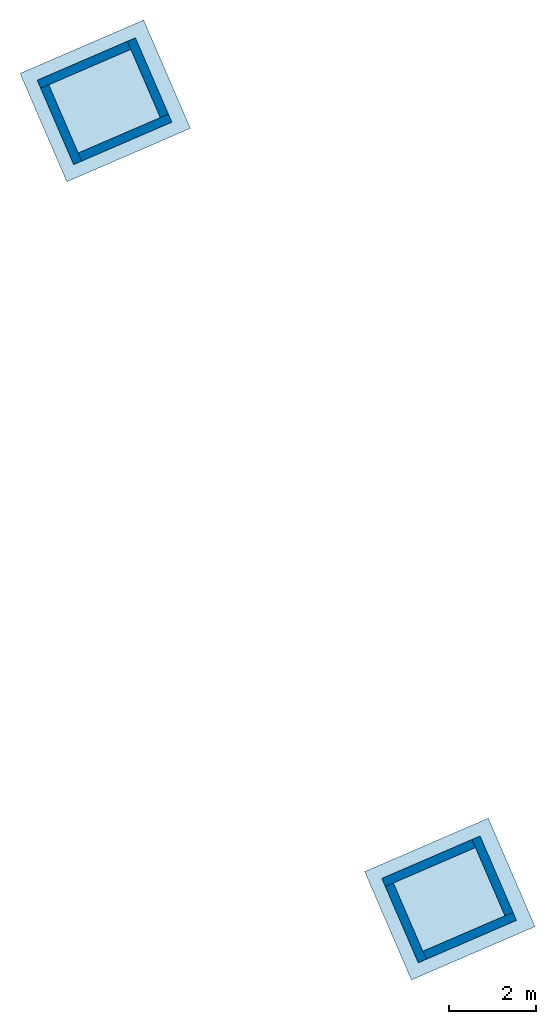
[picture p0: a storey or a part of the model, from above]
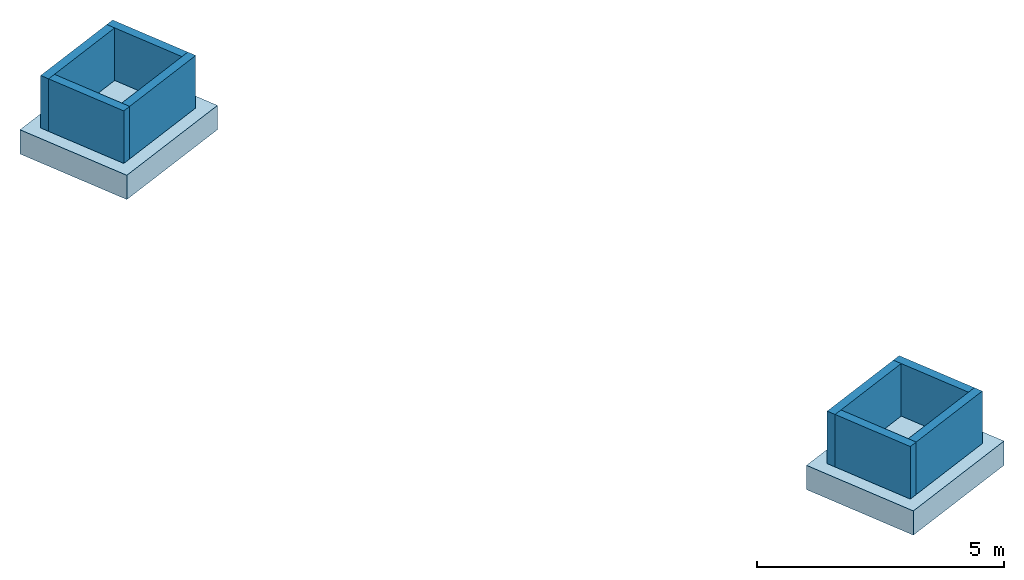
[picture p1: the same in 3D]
Properties of the parts of a building model (IFC4), part 1 of 4

# File
Description: ViewDefinition [ReferenceView_V1.2], RevitIdentifiers [ContentGUID: 2a206dc6-7e01-43c7-bab8-63df62a23673, VersionGUID: 60f15de3-2201-4711-b6eb-78f04dd25c04, NumberOfSaves: 5], CoordinateReference [CoordinateBase: Shared Coordinates, ProjectSite: Interno]
File name: C:\Users\Joaquin\Dropbox\BuildingProjects\2024 - Construcción Cesfam Coyhaique Con Sar Adosado\2_Modelos\all_models_2025-1-24_23.4.48\CCY_COOR-CCY_EST_Enriched.ifc
Time: 2025-11-28T11:11:42-03:00
Written by: IfcOpenShell 0.8.3-post1
Made in: Bonsai 0.8.3-post1

# IfcProject, 2016_03
LongName: CESFAM Coyhaique; Phase: 3

# IfcSite, Default
RefLatitude: 42, 21, 31, 181945; RefLongitude: -71, -3, -24, -263305; RefElevation: 0 m
Pset_SiteCommon - Reference: Project Information
Other - Category: Project Information; Client Name: Servicio de Salud Aysén; Project Address: Calle 2, s/n. Lote 1C.; Project Issue Date: Marzo 2017; Project Name: CESFAM Coyhaique; Project Number: 2016_03; Project Status: 3
Identity Data - Author: Astudillo y Aparicio Asociados Ltda.; Building Name: CESFAM Coyhaique; Organization Description: Arquitectura e ingeniería integrada; Organization Name: Astudillo y Aparicio Asociados Ltda.

# IfcBuilding, CESFAM Coyhaique
LongName: CESFAM Coyhaique
Pset_BuildingCommon - Reference: Project Information; NumberOfStoreys: 7
Pset_BuildingElementProxyCommon - Reference: Project Information; IsExternal: no
Pset_BuildingSystemCommon - Reference: Project Information
Other - Category: Project Information; Client Name: Servicio de Salud Aysén; Project Address: Calle 2, s/n. Lote 1C.; Project Issue Date: Marzo 2017; Project Name: CESFAM Coyhaique; Project Number: 2016_03; Project Status: 3
Identity Data - Author: Astudillo y Aparicio Asociados Ltda.; Building Name: CESFAM Coyhaique; Organization Description: Arquitectura e ingeniería integrada; Organization Name: Astudillo y Aparicio Asociados Ltda.

# IfcBuildingStorey: Level:8mm Head (7)
In: CESFAM Coyhaique
Other - Category: Levels; Family: Level; Family and Type: Level: 8mm Head; Type: 8mm Head; Type Id: 27
Dimensions - Computation Height: 0 m
Identity Data - Structural: no; Building Story: yes
Other(Type) - Category: Levels; Family Name: Level
Constraints(Type) - Elevation Base: Survey Point
Graphics(Type) - Color: 0; Line Pattern: Center; Line Weight: 1; Symbol: M_Level Head - Circle; Symbol at End 1 Default: no; Symbol at End 2 Default: yes
Identity Data(Type) - Type Name: 8mm Head
Name | LongName = Name | Elevation (m) | Constraints, Elevation (m)
Subterráneo 1 | Subterráneo 1 | -4.3 | 312.85
Base MHA ASC | Base MHA ASC | -1.35 | 315.8
d_Fundaciones | d_Fundaciones | -0.95 | 316.2
Nivel 1 | Nivel 1 | -0.05 | 317.1
Nivel 2 | Nivel 2 | 4.2 | 321.35
Nivel 3 | Nivel 3 | 8.45 | 325.6
Nivel 4 | Nivel 4 | 12.7 | 329.85

# IfcBeam: M_Concrete-Rectangular Beam:200 x 600mm (109)
In: d_Fundaciones
Type - PredefinedType: BEAM; Material: HA
Type - Other - Category: Structural Framing; Family Name: M_Concrete-Rectangular Beam
Type - Dimensions - b: 0.2 m; h: 0.6 m
Type - Identity Data - OmniClass Number: 23.25.30.11.14.14; OmniClass Title: Beams; Type Name: 200 x 600mm
Type - Structural - Section Shape: 0
Type - Pset_BeamCommon - LoadBearing: yes
Material: HA; HA
Pset_BeamCommon - IsExternal: no; Slope: 0 deg; Roll: 0 deg; Reference: M_Concrete-Rectangular Beam:200 x 600mm
Pset_EnvironmentalImpactIndicators - Reference: M_Concrete-Rectangular Beam:200 x 600mm; sets with these values: 2
Other - Family: M_Concrete-Rectangular Beam; Family and Type: M_Concrete-Rectangular Beam: 200 x 600mm; Type: 200 x 600mm; Type Id: 843100
Constraints - Cross-Section Rotation: 0 deg; End Level Offset: 0 m; Orientation: Normal; Start Level Offset: 0 m; Reference Level: d_Fundaciones; Reference Level Elevation: -0.95 m; Work Plane: Level : d_Fundaciones
Dimensions - Elevation at Bottom: -1.55 m; Elevation at Top: -0.95 m
Materials and Finishes - Structural Material: HA
Phasing - Phase Created: New Construction
Structural - Rebar Cover - Bottom Face: Rebar Cover 1 <25 mm>; Rebar Cover - Other Faces: Rebar Cover 1 <25 mm>; Rebar Cover - Top Face: Rebar Cover 1 <25 mm>; Structural Usage: Other
Geometric Position - Join Status: Both joins enabled; y Justification: Origin; yz Justification: Uniform; z Justification: Top; y Offset Value: 0 m; z Offset Value: 0 m
AboveGround - AboveGround: no
Name (M_Concrete-Rectangular Beam:200 x 600mm:...) | Span (m) = Qto_BeamBaseQuantities, Length (m) = Dimensions, Length (m) | CrossSectionArea (m2) | OuterSurfaceArea (m2) | GrossSurfaceArea (m2) = NetSurfaceArea (m2) | GrossVolume (m3) = NetVolume (m3) = Volume (m3) | Cut Length (m)
843053 | 7 | 0.12 | 7.44 | 7.68 | 0.558 | 4.65
843332 | 7.2 | 0.12 | 7.2 | 7.44 | 0.54 | 4.5
843365 | 7.2 | 0.12 | 7.84 | 8.08 | 0.588 | 4.9
843410 | 6 | 0.12 | 4.88 | 5.12 | 0.366 | 3.05
843443 | 4.8 | 0.12 | 3.36 | 3.6 | 0.252 | 2.1
843482 | 7.2 | 0.12 | 7.44 | 7.68 | 0.558 | 4.65
843516 | 7.2 | 0.12 | 6.8 | 7.04 | 0.51 | 4.25
843540 | 7.2 | 0.12 | 7.84 | 8.08 | 0.588 | 4.9
843578 | 6 | 0.12 | 5.52 | 5.76 | 0.414 | 3.45
843604 | 4.8 | 0.12 | 3.6 | 3.84 | 0.27 | 2.25
843622 | 7.2 | 0.12 | 7.04 | 7.28 | 0.528 | 4.4
843652 | 6 | 0.12 | 5.52 | 5.76 | 0.414 | 3.45
843674 | 4.8 | 0.12 | 3.6 | 3.84 | 0.27 | 2.25
843701 | 7.2 | 0.12 | 7.84 | 8.08 | 0.588 | 4.9
843743 | 7.2 | 0.12 | 7.44 | 7.68 | 0.558 | 4.65
843768 | 7.2 | 0.12 | 7.84 | 8.08 | 0.588 | 4.9
843804 | 3.6 | 0.12 | 2.08 | 2.32 | 0.156 | 1.3
843864 | 6 | 0.12 | 5.92 | 6.16 | 0.444 | 3.7
843889 | 4.8 | 0.12 | 4 | 4.24 | 0.3 | 2.5
843927 | 6 | 0.12 | 5.92 | 6.16 | 0.444 | 3.7
843970 | 6 | 0.12 | 5.92 | 6.16 | 0.444 | 3.7
843991 | 6 | 0.12 | 5.92 | 6.16 | 0.444 | 3.7
844033 | 6 | 0.12 | 5.92 | 6.16 | 0.444 | 3.7
844074 | 4.8 | 0.12 | 4 | 4.24 | 0.3 | 2.5
844154 | 7.2 | 0.12 | 7.2 | 7.44 | 0.54 | 4.5
844311 | 4.8 | 0.12 | 3.36 | 3.6 | 0.252 | 2.1
844338 | 6 | 0.12 | 5.28 | 5.52 | 0.396 | 3.3
844367 | 7.2 | 0.12 | 7.84 | 8.08 | 0.588 | 4.9
844407 | 7.2 | 0.12 | 6.8 | 7.04 | 0.51 | 4.25
844441 | 7.2 | 0.12 | 7.84 | 8.08 | 0.588 | 4.9
844473 | 4.8 | 0.12 | 3.6 | 3.84 | 0.27 | 2.25
844492 | 6 | 0.12 | 5.52 | 5.76 | 0.414 | 3.45
844532 | 7.2 | 0.12 | 7.04 | 7.28 | 0.528 | 4.4
844560 | 4.8 | 0.12 | 3.6 | 3.84 | 0.27 | 2.25
844590 | 6 | 0.12 | 5.52 | 5.76 | 0.414 | 3.45
844635 | 7.2 | 0.12 | 7.44 | 7.68 | 0.558 | 4.65
844664 | 7.2 | 0.12 | 4.72 | 4.96 | 0.354 | 2.95
844701 | 7.2 | 0.12 | 7.84 | 8.08 | 0.588 | 4.9
844761 | 3.6 | 0.12 | 2.08 | 2.32 | 0.156 | 1.3
844792 | 4.8 | 0.12 | 4 | 4.24 | 0.3 | 2.5
844820 | 6 | 0.12 | 5.92 | 6.16 | 0.444 | 3.7
844853 | 6 | 0.12 | 5.92 | 6.16 | 0.444 | 3.7
844994 | 6 | 0.12 | 5.92 | 6.16 | 0.444 | 3.7
845025 | 6 | 0.12 | 5.76 | 6 | 0.432 | 3.6
845063 | 6 | 0.12 | 5.72 | 5.96 | 0.429 | 3.575
845094 | 4.8 | 0.12 | 4 | 4.24 | 0.3 | 2.5
845142 | 3.85 | 0.12 | 2.48 | 2.72 | 0.186 | 1.55
845171 | 4.8 | 0.12 | 4 | 4.24 | 0.3 | 2.5
845220 | 6 | 0.12 | 5.92 | 6.16 | 0.444 | 3.7
845252 | 3.85 | 0.12 | 2.32 | 2.56 | 0.174 | 1.45
845282 | 3.95 | 0.12 | 2.64 | 2.88 | 0.198 | 1.65
845419 | 3.3 | 0.12 | 1.6 | 1.84 | 0.12 | 1
845455 | 3.3 | 0.12 | 1.6 | 1.84 | 0.12 | 1
845500 | 3.3 | 0.12 | 1.6 | 1.84 | 0.12 | 1
845532 | 4.8 | 0.12 | 4 | 4.24 | 0.3 | 2.5
845568 | 6 | 0.12 | 5.92 | 6.16 | 0.444 | 3.7
845618 | 7.2 | 0.12 | 7.84 | 8.08 | 0.588 | 4.9
845651 | 7.2 | 0.12 | 7.2 | 7.44 | 0.54 | 4.5
845681 | 7.2 | 0.12 | 7.84 | 8.08 | 0.588 | 4.9
845713 | 4.8 | 0.12 | 3.36 | 3.6 | 0.252 | 2.1
845773 | 6 | 0.12 | 5.28 | 5.52 | 0.396 | 3.3
845806 | 7.2 | 0.12 | 7.84 | 8.08 | 0.588 | 4.9
845851 | 7.2 | 0.12 | 6.8 | 7.04 | 0.51 | 4.25
845873 | 7.2 | 0.12 | 7.84 | 8.08 | 0.588 | 4.9
845921 | 6 | 0.12 | 5.52 | 5.76 | 0.414 | 3.45
845947 | 4.8 | 0.12 | 3.6 | 3.84 | 0.27 | 2.25
845974 | 7.2 | 0.12 | 7.04 | 7.28 | 0.528 | 4.4
846006 | 4.8 | 0.12 | 3.6 | 3.84 | 0.27 | 2.25
846026 | 6 | 0.12 | 5.52 | 5.76 | 0.414 | 3.45
846069 | 7.2 | 0.12 | 7.84 | 8.08 | 0.588 | 4.9
846101 | 7.2 | 0.12 | 7.44 | 7.68 | 0.558 | 4.65
846126 | 7.2 | 0.12 | 7.84 | 8.08 | 0.588 | 4.9
846211 | 3.6 | 0.12 | 2.08 | 2.32 | 0.156 | 1.3
846246 | 4.8 | 0.12 | 4 | 4.24 | 0.3 | 2.5
846265 | 6 | 0.12 | 5.927 | 6.167 | 0.444525 | 3.70437
846297 | 6 | 0.12 | 5.92 | 6.16 | 0.444 | 3.7
846333 | 6 | 0.12 | 5.92 | 6.16 | 0.444 | 3.7
846361 | 6 | 0.12 | 5.52 | 5.76 | 0.414 | 3.45
846392 | 4.8 | 0.12 | 3.6 | 3.84 | 0.27 | 2.25
846412 | 6 | 0.12 | 5.92 | 6.16 | 0.444 | 3.7
846469 | 3.85 | 0.12 | 2.48 | 2.72 | 0.186 | 1.55
846499 | 3.85 | 0.12 | 2.08 | 2.32 | 0.156 | 1.3
846534 | 3.85 | 0.12 | 2.48 | 2.72 | 0.186 | 1.55
846567 | 4.8 | 0.12 | 4 | 4.24 | 0.3 | 2.5
846587 | 6 | 0.12 | 5.92 | 6.16 | 0.444 | 3.7
846627 | 3.95 | 0.12 | 2.64 | 2.88 | 0.198 | 1.65
846676 | 3.95 | 0.12 | 2.64 | 2.88 | 0.198 | 1.65
846719 | 6 | 0.12 | 5.92 | 6.16 | 0.444 | 3.7
846754 | 3.95 | 0.12 | 2.64 | 2.88 | 0.198 | 1.65
846782 | 4.8 | 0.12 | 4 | 4.24 | 0.3 | 2.5
846829 | 8.55 | 0.12 | 9.4 | 9.64 | 0.705 | 5.875
846872 | 4.05 | 0.12 | 2.8 | 3.04 | 0.21 | 1.75
846899 | 4.5 | 0.12 | 3.52 | 3.76 | 0.264 | 2.2
846937 | 3.95 | 0.12 | 2.64 | 2.88 | 0.198 | 1.65
846964 | 4.05 | 0.12 | 2.8 | 3.04 | 0.21 | 1.75
846994 | 4.5 | 0.12 | 3.52 | 3.76 | 0.264 | 2.2
847058 | 8.55 | 0.12 | 10 | 10.24 | 0.75 | 6.25
847085 | 8.55 | 3.21002 | 2.82 | 9.24004 | 0.642004 | 6.25
847120 | 9 | 0.12 | 10.72 | 10.96 | 0.804 | 6.7
847147 | 9 | 0.12 | 10.72 | 10.96 | 0.804 | 6.7
847185 | 8.55 | 0.12 | 10 | 10.24 | 0.75 | 6.25
847220 | 9 | 0.12 | 10 | 10.24 | 0.75 | 6.25
847305 | 8.55 | 0.12 | 9.99988 | 10.2399 | 0.749991 | 6.24992
847336 | 8.55 | 0.12 | 10 | 10.24 | 0.75 | 6.25
847376 | 8.55 | 3.21002 | 2.82 | 9.24004 | 0.642004 | 6.25
847405 | 8.55 | 0.12 | 10 | 10.24 | 0.75 | 6.25
847433 | 8.55 | 0.12 | 10.72 | 10.96 | 0.804 | 6.7
847527 | 8.55 | 0.12 | 9.99988 | 10.2399 | 0.749991 | 6.24992
847567 | 8.55 | 0.12 | 9.99988 | 10.2399 | 0.749991 | 6.24992

# IfcBeam: M_Concrete-Rectangular Beam:300 x 500mm (6)
In: Nivel 2
Type - PredefinedType: BEAM; Material: HA
Type - Other - Category: Structural Framing; Family Name: M_Concrete-Rectangular Beam
Type - Dimensions - b: 0.3 m; h: 0.5 m
Type - Identity Data - OmniClass Number: 23.25.30.11.14.14; OmniClass Title: Beams; Type Name: 300 x 500mm
Type - Structural - Section Shape: 0
Type - Pset_BeamCommon - LoadBearing: yes
Classification: B1042 (FEMAP58); Material: HA; HA
Pset_BeamCommon - IsExternal: no; Roll: 0 deg; Reference: M_Concrete-Rectangular Beam:300 x 500mm
Pset_EnvironmentalImpactIndicators - Reference: M_Concrete-Rectangular Beam:300 x 500mm; sets with these values: 2
Other - Family: M_Concrete-Rectangular Beam; Family and Type: M_Concrete-Rectangular Beam: 300 x 500mm; Type: 300 x 500mm; Type Id: 856726
Constraints - Cross-Section Rotation: 0 deg; Reference Level: Nivel 2; Reference Level Elevation: 4.2 m
Materials and Finishes - Structural Material: HA
Phasing - Phase Created: New Construction
Structural - Rebar Cover - Other Faces: Rebar Cover 1 <25 mm>; Structural Usage: Other
Geometric Position - Join Status: Both joins enabled; y Justification: Origin; yz Justification: Uniform; z Justification: Top; y Offset Value: 0 m
AboveGround - AboveGround: yes
Name (M_Concrete-Rectangular Beam:300 x 500mm:...) | Span (m) = Qto_BeamBaseQuantities, Length (m) = Dimensions, Length (m) | Slope (deg) | CrossSectionArea (m2) | NetSurfaceArea (m2) | NetVolume (m3) = Volume (m3) | End Level Offset (m) | Start Level Offset (m) | Cut Length (m) | z Offset Value (m)
856684 | 15.1906 | 2.98107 | 12.3027 | 24.6053 | 2.27745 | -0.8 | -0.01 | 15.1906 | -0.15
858273 | 7.28375 | 3.00467 | 5.97751 | 11.955 | 1.09168 | -0.388481 | -0.00668652 | 7.28375 | -0.15
858695 | 8.16657 | 2.88408 | 6.68318 | 13.3664 | 1.225 | -0.799386 | -0.388481 | 8.16657 | -0.15 | Dimensions - Keep Concentric: yes
859191 | 3.8 | 0 | 2.91229 | 5.82458 | 0.507902 | -0.05 | -0.05 | 3.46459 | -0.72 | Dimensions - Elevation at Bottom: 2.93 m; Elevation at Top: 3.43 m; Structural - Rebar Cover - Bottom Face: Rebar Cover 1 <25 mm>; Rebar Cover - Top Face: Rebar Cover 1 <25 mm>
861732 | 3.8 | 0 | 2.91229 | 5.82458 | 0.507902 | -0.2 | -0.2 | 3.46459 | -0.85 | Dimensions - Elevation at Bottom: 2.65 m; Elevation at Top: 3.15 m; Structural - Rebar Cover - Bottom Face: Rebar Cover 1 <25 mm>; Rebar Cover - Top Face: Rebar Cover 1 <25 mm>
864425 | 5.88816 | 0 | 4.91817 | 9.83634 | 0.84127 | 0 | 0 | 5.88816 | -0.95 | Dimensions - Elevation at Bottom: 2.75 m; Elevation at Top: 3.25 m; Structural - Rebar Cover - Bottom Face: Rebar Cover 1 <25 mm>; Rebar Cover - Top Face: Rebar Cover 1 <25 mm>; Constraints - Orientation: Normal; Work Plane: Level : Nivel 2

# IfcBeam: M_W Shapes:W220X120mm (14)
Type - PredefinedType: BEAM; Material: Steel, 45-345
Type - Other - Category: Structural Framing; Family Name: M_W Shapes
Type - Identity Data - Code Name: AISC 14.1; OmniClass Number: 23.25.30.11.14.14; OmniClass Title: Beams; Section Name Key: W12x26; Type Name: W220X120mm
Type - Structural - Section Shape: 6
Type - Structural Analysis - Elastic Modulus strong axis: 0.000547 m3; Elastic Modulus weak axis: 0.0000875 m3; Moment of Inertia strong axis: 0.0000849 m4; Moment of Inertia weak axis: 0.0000072 m4; Nominal Weight: 379.516 kg/s2; Perimeter: 1.25 m; Plastic Modulus strong axis: 0.00061 m3; Plastic Modulus weak axis: 0.000134 m3; Section Area: 0.00494 m2; Torsional Moment of Inertia: 1.25e-07 m4; Warping Constant: 1.63e-07 m6
Type - Structural Section Geometry - Centroid Horizontal: 0.06 m; Centroid Vertical: 0.11 m; Flange Thickness: 0.00965 m; Height: 0.22 m; Web Fillet: 0.00765 m; Web Thickness: 0.00584 m; Width: 0.12 m
Type - Pset_BeamCommon - LoadBearing: yes
Classification: B103 (FEMAP58); Material: Steel, 45-345; Steel, 45-345
Pset_BeamCommon - IsExternal: no; Slope: 0 deg; Roll: 0 deg; Reference: M_W Shapes:W220X120mm
Pset_EnvironmentalImpactIndicators - Reference: M_W Shapes:W220X120mm; sets with these values: 2
Qto_BeamBaseQuantities - CrossSectionArea: 0.00353838 m2
Other - Family: M_W Shapes; Family and Type: M_W Shapes: W220X120mm; Type: W220X120mm; Type Id: 916167
Constraints - Cross-Section Rotation: 0 deg; End Level Offset: 0 m; Orientation: Normal; Start Level Offset: 0 m
Materials and Finishes - Structural Material: Steel, 45-345
Phasing - Phase Created: New Construction
Structural - End Attachment Type: End Elevation; Start Attachment Type: End Elevation; Stick Symbol Location: Center of Geometry; Structural Usage: Primary
Geometric Position - Join Status: Both joins enabled; Start Extension: 0 m; y Justification: Origin; yz Justification: Uniform; z Justification: Top; y Offset Value: 0 m; z Offset Value: -0.15 m
AboveGround - AboveGround: yes
Name (M_W Shapes:W220X120mm:...) | In | Span (m) = Qto_BeamBaseQuantities, Length (m) = Dimensions, Length (m) | OuterSurfaceArea (m2) | GrossSurfaceArea (m2) = NetSurfaceArea (m2) | GrossVolume (m3) | NetVolume (m3) = Volume (m3) | Reference Level | Reference Level Elevation (m) | Work Plane | Elevation at Bottom (m) | Elevation at Top (m) | Cut Length (m) | Weight (kg) | End Extension (m) | End Join Cutback (m) | Start Join Cutback (m) | Group
915953 | Nivel 2 | 1.9962 | 1.51027 | 1.51735 | 0.0059696 | 0.00596952 | Nivel 2 | 4.2 | Level : Nivel 2 | 3.83 | 4.05 | 1.6871 | 65.4161 | 0 | 0 | 0.0127 | Model Group:CAJA ASCENSOR (members excluded):916446
916065 | Nivel 2 | 2.245 | 1.81929 | 1.82636 | 0.00719104 | 0.00719095 | Nivel 2 | 4.2 | Level : Nivel 2 | 3.83 | 4.05 | 2.0323 | 78.801 | -0.476298 | 0.0127 | 0 | Model Group:CAJA ASCENSOR (members excluded):916446
916246 | Nivel 2 | 2.245 | 1.81929 | 1.82636 | 0.00719104 | 0.00719095 | Nivel 2 | 4.2 | Level : Nivel 2 | 3.83 | 4.05 | 2.0323 | 78.801 | -0.476298 | 0.0127 | 0 | Model Group:CAJA ASCENSOR (members excluded):916446
916312 | Nivel 2 | 1.8999 | 1.51036 | 1.51744 | 0.00596995 | 0.00596987 | Nivel 2 | 4.2 | Level : Nivel 2 | 3.83 | 4.05 | 1.6872 | 65.42 | 0 | 0 | 0.0127
916414 | Nivel 3 | 1.9962 | 1.51027 | 1.51735 | 0.0059696 | 0.00596952 | Nivel 3 | 8.45 | Level : Nivel 3 | 8.08 | 8.3 | 1.6871 | 65.4161 | 0 | 0 | 0.0127 | Model Group:CAJA ASCENSOR (members excluded):916446
916416 | Nivel 3 | 2.245 | 1.81929 | 1.82636 | 0.00719104 | 0.00719095 | Nivel 3 | 8.45 | Level : Nivel 3 | 8.08 | 8.3 | 2.0323 | 78.801 | -0.476298 | 0.0127 | 0 | Model Group:CAJA ASCENSOR (members excluded):916446
916418 | Nivel 3 | 2.245 | 1.81929 | 1.82636 | 0.00719104 | 0.00719095 | Nivel 3 | 8.45 | Level : Nivel 3 | 8.08 | 8.3 | 2.0323 | 78.801 | -0.476298 | 0.0127 | 0 | Model Group:CAJA ASCENSOR (members excluded):916446
916420 | Nivel 3 | 1.8999 | 1.51036 | 1.51744 | 0.00596995 | 0.00596987 | Nivel 3 | 8.45 | Level : Nivel 3 | 8.08 | 8.3 | 1.6872 | 65.42 | 0 | 0 | 0.0127
916597 | Nivel 2 | 1.9962 | 1.51027 | 1.51735 | 0.0059696 | 0.00596952 | Nivel 2 | 4.2 | Level : Nivel 2 | 3.83 | 4.05 | 1.6871 | 65.4161 | 0 | 0 | 0.0127 | Model Group:CAJA ASCENSOR (members excluded):916610
916599 | Nivel 2 | 2.245 | 1.81929 | 1.82636 | 0.00719104 | 0.00719095 | Nivel 2 | 4.2 | Level : Nivel 2 | 3.83 | 4.05 | 2.0323 | 78.801 | -0.476298 | 0.0127 | 0 | Model Group:CAJA ASCENSOR (members excluded):916610
916601 | Nivel 2 | 2.245 | 1.81929 | 1.82636 | 0.00719104 | 0.00719095 | Nivel 2 | 4.2 | Level : Nivel 2 | 3.83 | 4.05 | 2.0323 | 78.801 | -0.476298 | 0.0127 | 0 | Model Group:CAJA ASCENSOR (members excluded):916610
916604 | Nivel 3 | 1.9962 | 1.51027 | 1.51735 | 0.0059696 | 0.00596952 | Nivel 3 | 8.45 | Level : Nivel 3 | 8.08 | 8.3 | 1.6871 | 65.4161 | 0 | 0 | 0.0127 | Model Group:CAJA ASCENSOR (members excluded):916610
916606 | Nivel 3 | 2.245 | 1.81929 | 1.82636 | 0.00719104 | 0.00719095 | Nivel 3 | 8.45 | Level : Nivel 3 | 8.08 | 8.3 | 2.0323 | 78.801 | -0.476298 | 0.0127 | 0 | Model Group:CAJA ASCENSOR (members excluded):916610
916608 | Nivel 3 | 2.245 | 1.81929 | 1.82636 | 0.00719104 | 0.00719095 | Nivel 3 | 8.45 | Level : Nivel 3 | 8.08 | 8.3 | 2.0323 | 78.801 | -0.476298 | 0.0127 | 0 | Model Group:CAJA ASCENSOR (members excluded):916610

# IfcBeam: M_W Shapes:W240X120mm (40)
In: Nivel 3
Type - PredefinedType: BEAM; Material: Steel, 45-345
Type - Other - Category: Structural Framing; Family Name: M_W Shapes
Type - Identity Data - Code Name: AISC 14.1; OmniClass Number: 23.25.30.11.14.14; OmniClass Title: Beams; Section Name Key: W12x26; Type Name: W240X120mm
Type - Structural - Section Shape: 6
Type - Structural Analysis - Elastic Modulus strong axis: 0.000547 m3; Elastic Modulus weak axis: 0.0000875 m3; Moment of Inertia strong axis: 0.0000849 m4; Moment of Inertia weak axis: 0.0000072 m4; Nominal Weight: 379.516 kg/s2; Perimeter: 1.25 m; Plastic Modulus strong axis: 0.00061 m3; Plastic Modulus weak axis: 0.000134 m3; Section Area: 0.00494 m2; Torsional Moment of Inertia: 1.25e-07 m4; Warping Constant: 1.63e-07 m6
Type - Structural Section Geometry - Centroid Horizontal: 0.06 m; Centroid Vertical: 0.12 m; Flange Thickness: 0.00965 m; Height: 0.24 m; Web Fillet: 0.00765 m; Web Thickness: 0.00584 m; Width: 0.12 m
Type - Pset_BeamCommon - LoadBearing: yes
Classification: B103 (FEMAP58); Material: Steel, 45-345; Steel, 45-345
Pset_BeamCommon - IsExternal: no; Slope: 0 deg; Roll: 0 deg; Reference: M_W Shapes:W240X120mm
Pset_EnvironmentalImpactIndicators - Reference: M_W Shapes:W240X120mm; sets with these values: 2
Qto_BeamBaseQuantities - CrossSectionArea: 0.00365518 m2
Other - Family: M_W Shapes; Family and Type: M_W Shapes: W240X120mm; Type: W240X120mm; Type Id: 906066
Constraints - Cross-Section Rotation: 0 deg; End Level Offset: 0 m; Orientation: Normal; Start Level Offset: 0 m; Reference Level: Nivel 3; Reference Level Elevation: 8.45 m; Work Plane: Level : Nivel 3
Dimensions - Elevation at Bottom: 8.06 m; Elevation at Top: 8.3 m
Materials and Finishes - Structural Material: Steel, 45-345
Phasing - Phase Created: New Construction
Structural - Stick Symbol Location: Center of Geometry; Structural Usage: Primary
Geometric Position - End Extension: 0 m; Join Status: Both joins enabled; Start Extension: 0 m; y Justification: Origin; yz Justification: Uniform; z Justification: Top; y Offset Value: 0 m; End Join Cutback: 0.0127 m; Start Join Cutback: 0.0127 m; z Offset Value: -0.15 m
AboveGround - AboveGround: yes
Name (M_W Shapes:W240X120mm:...) | Span (m) = Qto_BeamBaseQuantities, Length (m) = Dimensions, Length (m) | OuterSurfaceArea (m2) | GrossSurfaceArea (m2) | NetSurfaceArea (m2) | GrossVolume (m3) | NetVolume (m3) = Volume (m3) | Cut Length (m) | Weight (kg)
906035 | 4.905 | 4.38565 | 4.39296 | 4.39296 | 0.0171413 | 0.0171445 | 4.6896 | 181.836
906178 | 4.905 | 4.38565 | 4.39296 | 4.39296 | 0.0171413 | 0.0171445 | 4.6896 | 181.836
906230 | 4.8 | 4.38565 | 4.39296 | 4.39296 | 0.0171413 | 0.0171411 | 4.6896 | 181.836
906250 | 4.8 | 4.38565 | 4.39296 | 4.39296 | 0.0171413 | 0.0171411 | 4.6896 | 181.836
906271 | 4.8 | 4.38565 | 4.39296 | 4.39296 | 0.0171413 | 0.0171411 | 4.6896 | 181.836
906292 | 4.8 | 4.38565 | 4.39296 | 4.39296 | 0.0171413 | 0.0171411 | 4.6896 | 181.836
906311 | 4.795 | 4.38097 | 4.38828 | 4.38829 | 0.0171231 | 0.0171262 | 4.6846 | 181.642
906331 | 4.795 | 4.38097 | 4.38828 | 4.38829 | 0.0171231 | 0.0171262 | 4.6846 | 181.642
906350 | 4.8 | 4.28746 | 4.29477 | 4.29477 | 0.0167575 | 0.0167606 | 4.5846 | 177.765
906371 | 4.8 | 4.28746 | 4.29477 | 4.29477 | 0.0167575 | 0.0167606 | 4.5846 | 177.765
906721 | 4.8 | 4.28746 | 4.29477 | 4.29477 | 0.0167575 | 0.0167606 | 4.5846 | 177.765
907510 | 4.8 | 4.28746 | 4.29477 | 4.29477 | 0.0167575 | 0.0167606 | 4.5846 | 177.765
907512 | 4.8 | 4.28746 | 4.29477 | 4.29477 | 0.0167575 | 0.0167606 | 4.5846 | 177.765
907595 | 4.795 | 4.38097 | 4.38828 | 4.38828 | 0.0171231 | 0.0171228 | 4.6846 | 181.642
907615 | 4.795 | 4.38097 | 4.38828 | 4.38828 | 0.0171231 | 0.0171228 | 4.6846 | 181.642
907634 | 4.8 | 4.38565 | 4.39296 | 4.39296 | 0.0171413 | 0.0171445 | 4.6896 | 181.836
907655 | 4.8 | 4.38565 | 4.39296 | 4.39296 | 0.0171413 | 0.0171445 | 4.6896 | 181.836
907674 | 4.8 | 4.38565 | 4.39296 | 4.39296 | 0.0171413 | 0.0171445 | 4.6896 | 181.836
907695 | 4.8 | 4.38565 | 4.39296 | 4.39296 | 0.0171413 | 0.0171445 | 4.6896 | 181.836
907716 | 4.905 | 4.38565 | 4.39296 | 4.39296 | 0.0171413 | 0.0171445 | 4.6896 | 181.836
907735 | 4.905 | 4.38565 | 4.39296 | 4.39296 | 0.0171413 | 0.0171445 | 4.6896 | 181.836
907754 | 4.905 | 4.38565 | 4.39296 | 4.39296 | 0.0171413 | 0.0171445 | 4.6896 | 181.836
907773 | 4.8 | 4.38565 | 4.39296 | 4.39296 | 0.0171413 | 0.0171445 | 4.6896 | 181.836
908223 | 4.8 | 4.28746 | 4.29477 | 4.29477 | 0.0167575 | 0.0167606 | 4.5846 | 177.765
908298 | 4.8 | 4.28746 | 4.29477 | 4.29477 | 0.0167575 | 0.0167606 | 4.5846 | 177.765
908426 | 4.8 | 4.28746 | 4.29477 | 4.29477 | 0.0167575 | 0.0167606 | 4.5846 | 177.765
908464 | 4.8 | 4.28746 | 4.29477 | 4.29477 | 0.0167575 | 0.0167606 | 4.5846 | 177.765
908757 | 4.8 | 4.28746 | 4.29477 | 4.29477 | 0.0167575 | 0.0167606 | 4.5846 | 177.765
908776 | 4.795 | 4.38097 | 4.38828 | 4.38828 | 0.0171231 | 0.0171228 | 4.6846 | 181.642
908795 | 4.795 | 4.38097 | 4.38828 | 4.38828 | 0.0171231 | 0.0171228 | 4.6846 | 181.642
908814 | 4.8 | 4.38565 | 4.39296 | 4.39296 | 0.0171413 | 0.0171445 | 4.6896 | 181.836
908835 | 4.8 | 4.38565 | 4.39296 | 4.39296 | 0.0171413 | 0.0171445 | 4.6896 | 181.836
908854 | 4.8 | 4.38565 | 4.39296 | 4.39296 | 0.0171413 | 0.0171445 | 4.6896 | 181.836
908873 | 4.8 | 4.38565 | 4.39296 | 4.39296 | 0.0171413 | 0.0171445 | 4.6896 | 181.836
908892 | 4.8 | 4.28746 | 4.29477 | 4.29477 | 0.0167575 | 0.0167606 | 4.5846 | 177.765
909061 | 4.8 | 4.28746 | 4.29477 | 4.29477 | 0.0167575 | 0.0167606 | 4.5846 | 177.765
909212 | 4.8 | 4.28746 | 4.29477 | 4.29477 | 0.0167575 | 0.0167606 | 4.5846 | 177.765
909256 | 1.5699 | 1.33217 | 1.33948 | 1.33948 | 0.0052068 | 0.00520673 | 1.4245 | 55.234
909343 | 1.5699 | 1.33217 | 1.33948 | 1.33948 | 0.0052068 | 0.00520673 | 1.4245 | 55.234
909404 | 4.8 | 4.38565 | 4.39296 | 4.39296 | 0.0171413 | 0.0171445 | 4.6896 | 181.836

# IfcBeam: M_W Shapes:W270X140mm (61)
Type - PredefinedType: BEAM; Material: Steel, 45-345
Type - Other - Category: Structural Framing; Family Name: M_W Shapes
Type - Identity Data - Code Name: AISC 14.1; OmniClass Number: 23.25.30.11.14.14; OmniClass Title: Beams; Section Name Key: W12x26; Type Name: W270X140mm
Type - Structural - Section Shape: 6
Type - Structural Analysis - Elastic Modulus strong axis: 0.000547 m3; Elastic Modulus weak axis: 0.0000875 m3; Moment of Inertia strong axis: 0.0000849 m4; Moment of Inertia weak axis: 0.0000072 m4; Nominal Weight: 379.516 kg/s2; Perimeter: 1.25 m; Plastic Modulus strong axis: 0.00061 m3; Plastic Modulus weak axis: 0.000134 m3; Section Area: 0.00494 m2; Torsional Moment of Inertia: 1.25e-07 m4; Warping Constant: 1.63e-07 m6
Type - Structural Section Geometry - Centroid Horizontal: 0.07 m; Centroid Vertical: 0.135 m; Flange Thickness: 0.00965 m; Height: 0.27 m; Web Fillet: 0.00765 m; Web Thickness: 0.00584 m; Width: 0.14 m
Type - Pset_BeamCommon - LoadBearing: yes
Classification: B103 (FEMAP58); Material: Steel, 45-345; Steel, 45-345
Pset_BeamCommon - IsExternal: no; Slope: 0 deg; Roll: 0 deg; Reference: M_W Shapes:W270X140mm
Pset_EnvironmentalImpactIndicators - Reference: M_W Shapes:W270X140mm; sets with these values: 2
Qto_BeamBaseQuantities - CrossSectionArea: 0.00421638 m2
Other - Family: M_W Shapes; Family and Type: M_W Shapes: W270X140mm; Type: W270X140mm; Type Id: 901091
Constraints - Cross-Section Rotation: 0 deg; End Level Offset: 0 m; Orientation: Normal; Start Level Offset: 0 m
Materials and Finishes - Structural Material: Steel, 45-345
Phasing - Phase Created: New Construction
Structural - Stick Symbol Location: Center of Geometry; Structural Usage: Primary
Geometric Position - Join Status: Both joins enabled; Start Extension: 0 m; y Justification: Origin; yz Justification: Uniform; z Justification: Top; z Offset Value: -0.15 m
AboveGround - AboveGround: yes
Name (M_W Shapes:W270X140mm:...) | In | Span (m) = Qto_BeamBaseQuantities, Length (m) = Dimensions, Length (m) | OuterSurfaceArea (m2) | GrossSurfaceArea (m2) | NetSurfaceArea (m2) | GrossVolume (m3) | NetVolume (m3) = Volume (m3) | Reference Level | Reference Level Elevation (m) | Work Plane | Elevation at Bottom (m) | Elevation at Top (m) | Cut Length (m) | Weight (kg) | End Extension (m) | y Offset Value (m) | End Join Cutback (m) | Start Join Cutback (m)
901071 | Nivel 2 | 4.9 | 5.03682 | 5.04525 | 5.04526 | 0.0197521 | 0.0197552 | Nivel 2 | 4.2 | Level : Nivel 2 | 3.78 | 4.05 | 4.6846 | 181.642 | 0 | 0 | 0.0127 | 0.0127
901157 | Nivel 2 | 4.9 | 5.03682 | 5.04525 | 5.04526 | 0.0197521 | 0.0197552 | Nivel 2 | 4.2 | Level : Nivel 2 | 3.78 | 4.05 | 4.6846 | 181.642 | 0 | 0 | 0.0127 | 0.0127
901209 | Nivel 2 | 4.9 | 5.03682 | 5.04525 | 5.04526 | 0.0197521 | 0.0197552 | Nivel 2 | 4.2 | Level : Nivel 2 | 3.78 | 4.05 | 4.6846 | 181.642 | 0 | 0 | 0.0127 | 0.0127
901268 | Nivel 2 | 4.8 | 4.9293 | 4.93773 | 4.93773 | 0.0193304 | 0.0193302 | Nivel 2 | 4.2 | Level : Nivel 2 | 3.78 | 4.05 | 4.5846 | 177.765 | 0 | 0 | 0.0127 | 0.0127
901272 | Nivel 2 | 4.8 | 4.9293 | 4.93773 | 4.93773 | 0.0193304 | 0.0193302 | Nivel 2 | 4.2 | Level : Nivel 2 | 3.78 | 4.05 | 4.5846 | 177.765 | 0 | 0 | 0.0127 | 0.0127
901384 | Nivel 2 | 4.8 | 4.9293 | 4.93773 | 4.93774 | 0.0193304 | 0.0193335 | Nivel 2 | 4.2 | Level : Nivel 2 | 3.78 | 4.05 | 4.5846 | 177.765 | 0 | 0 | 0.0127 | 0.0127
903800 | Nivel 2 | 4.9 | 5.03682 | 5.04525 | 5.04526 | 0.0197521 | 0.0197552 | Nivel 2 | 4.2 | Level : Nivel 2 | 3.78 | 4.05 | 4.6846 | 181.642 | 0 | 0 | 0.0127 | 0.0127
903885 | Nivel 2 | 4.795 | 5.03682 | 5.04525 | 5.04526 | 0.0197521 | 0.0197552 | Nivel 2 | 4.2 | Level : Nivel 2 | 3.78 | 4.05 | 4.6846 | 181.642 | 0 | 0 | 0.0127 | 0.0127
904811 | Nivel 2 | 4.9 | 5.15262 | 5.16105 | 5.16105 | 0.0202062 | 0.0202059 | Nivel 2 | 4.2 | Level : Nivel 2 | 3.78 | 4.05 | 4.7923 | 185.818 | 0 | 0 | 0.0127
904834 | Nivel 2 | 4.9 | 5.15262 | 5.16105 | 5.16105 | 0.0202062 | 0.0202059 | Nivel 2 | 4.2 | Level : Nivel 2 | 3.78 | 4.05 | 4.7923 | 185.818 | 0 | 0 | 0.0127
904853 | Nivel 2 | 4.8 | 5.04219 | 5.05063 | 5.05063 | 0.0197732 | 0.0197763 | Nivel 2 | 4.2 | Level : Nivel 2 | 3.78 | 4.05 | 4.6896 | 181.836 | 0 | 0 | 0.0127 | 0.0127
904873 | Nivel 2 | 4.8 | 5.04219 | 5.05063 | 5.05063 | 0.0197732 | 0.0197763 | Nivel 2 | 4.2 | Level : Nivel 2 | 3.78 | 4.05 | 4.6896 | 181.836 | 0 | 0 | 0.0127 | 0.0127
904892 | Nivel 2 | 4.795 | 5.03682 | 5.04525 | 5.04526 | 0.0197521 | 0.0197552 | Nivel 2 | 4.2 | Level : Nivel 2 | 3.78 | 4.05 | 4.6846 | 181.642 | 0 | 0 | 0.0127 | 0.0127
904911 | Nivel 2 | 4.795 | 5.03682 | 5.04525 | 5.04526 | 0.0197521 | 0.0197552 | Nivel 2 | 4.2 | Level : Nivel 2 | 3.78 | 4.05 | 4.6846 | 181.642 | 0 | 0 | 0.0127 | 0.0127
904930 | Nivel 2 | 4.795 | 5.03682 | 5.04525 | 5.04526 | 0.0197521 | 0.0197552 | Nivel 2 | 4.2 | Level : Nivel 2 | 3.78 | 4.05 | 4.6846 | 181.642 | 0 | 0 | 0.0127 | 0.0127
904949 | Nivel 2 | 4.795 | 5.03972 | 5.04815 | 5.04816 | 0.0197635 | 0.0197666 | Nivel 2 | 4.2 | Level : Nivel 2 | 3.78 | 4.05 | 4.6873 | 181.747 | 0 | 0 | 0.0127
904970 | Nivel 2 | 4.795 | 5.03972 | 5.04815 | 5.04816 | 0.0197635 | 0.0197666 | Nivel 2 | 4.2 | Level : Nivel 2 | 3.78 | 4.05 | 4.6873 | 181.747 | 0 | 0 | 0.0127
905678 | Nivel 3 | 5.995 | 6.32704 | 6.33547 | 6.33547 | 0.0248117 | 0.0248114 | Nivel 3 | 8.45 | Level : Nivel 3 | 8.03 | 8.3 | 5.8846 | 228.171 | 0 | 0 | 0.0127 | 0.0127
905768 | Nivel 3 | 5.995 | 6.32704 | 6.33547 | 6.33547 | 0.0248117 | 0.0248114 | Nivel 3 | 8.45 | Level : Nivel 3 | 8.03 | 8.3 | 5.8846 | 228.171 | 0 | 0 | 0.0127 | 0.0127
905816 | Nivel 3 | 1.24 | 1.1554 | 1.16383 | 1.16383 | 0.00453093 | 0.00453087 | Nivel 3 | 8.45 | Level : Nivel 3 | 8.03 | 8.3 | 1.0746 | 41.6669 | 0 | 0.105 | 0.0127 | 0.0127
905939 | Nivel 3 | 5.995 | 6.32704 | 6.33547 | 6.33547 | 0.0248117 | 0.0248114 | Nivel 3 | 8.45 | Level : Nivel 3 | 8.03 | 8.3 | 5.8846 | 228.171 | 0 | 0 | 0.0127 | 0.0127
906228 | Nivel 3 | 5.995 | 6.32704 | 6.33547 | 6.33547 | 0.0248117 | 0.0248114 | Nivel 3 | 8.45 | Level : Nivel 3 | 8.03 | 8.3 | 5.8846 | 228.171 | 0 | 0 | 0.0127 | 0.0127
906248 | Nivel 3 | 5.995 | 6.32704 | 6.33547 | 6.33547 | 0.0248117 | 0.0248114 | Nivel 3 | 8.45 | Level : Nivel 3 | 8.03 | 8.3 | 5.8846 | 228.171 | 0 | 0 | 0.0127 | 0.0127
906269 | Nivel 3 | 5.995 | 6.32704 | 6.33547 | 6.33547 | 0.0248117 | 0.0248114 | Nivel 3 | 8.45 | Level : Nivel 3 | 8.03 | 8.3 | 5.8846 | 228.171 | 0 | 0 | 0.0127 | 0.0127
906290 | Nivel 3 | 5.995 | 6.32704 | 6.33547 | 6.33547 | 0.0248117 | 0.0248114 | Nivel 3 | 8.45 | Level : Nivel 3 | 8.03 | 8.3 | 5.8846 | 228.171 | 0 | 0 | 0.0127 | 0.0127
906309 | Nivel 3 | 5.995 | 6.32704 | 6.33547 | 6.33547 | 0.0248117 | 0.0248114 | Nivel 3 | 8.45 | Level : Nivel 3 | 8.03 | 8.3 | 5.8846 | 228.171 | 0 | 0 | 0.0127 | 0.0127
906329 | Nivel 3 | 5.995 | 6.32704 | 6.33547 | 6.33547 | 0.0248117 | 0.0248114 | Nivel 3 | 8.45 | Level : Nivel 3 | 8.03 | 8.3 | 5.8846 | 228.171 | 0 | 0 | 0.0127 | 0.0127
906348 | Nivel 3 | 5.995 | 6.32704 | 6.33547 | 6.33547 | 0.0248117 | 0.0248114 | Nivel 3 | 8.45 | Level : Nivel 3 | 8.03 | 8.3 | 5.8846 | 228.171 | 0 | 0 | 0.0127 | 0.0127
906369 | Nivel 3 | 4.2 | 4.39999 | 4.40842 | 4.40842 | 0.0172547 | 0.0172574 | Nivel 3 | 8.45 | Level : Nivel 3 | 8.03 | 8.3 | 4.0923 | 158.676 | 0 | 0 | 0.0127
906641 | Nivel 3 | 6.1 | 6.44284 | 6.45127 | 6.45128 | 0.0252658 | 0.0252698 | Nivel 3 | 8.45 | Level : Nivel 3 | 8.03 | 8.3 | 5.9923 | 232.347 | 0 | 0 | 0.0127
906776 | Nivel 3 | 6.105 | 6.33242 | 6.34085 | 6.34085 | 0.0248328 | 0.0248367 | Nivel 3 | 8.45 | Level : Nivel 3 | 8.03 | 8.3 | 5.8896 | 228.365 | 0 | 0 | 0.0127 | 0.0127
906865 | Nivel 3 | 5.995 | 6.32704 | 6.33547 | 6.33547 | 0.0248117 | 0.0248114 | Nivel 3 | 8.45 | Level : Nivel 3 | 8.03 | 8.3 | 5.8846 | 228.171 | 0 | 0 | 0.0127 | 0.0127
906944 | Nivel 3 | 1.44 | 1.37043 | 1.37887 | 1.37887 | 0.0053742 | 0.00537505 | Nivel 3 | 8.45 | Level : Nivel 3 | 8.03 | 8.3 | 1.2746 | 49.4217 | 0 | 0 | 0.0127 | 0.0127
907386 | Nivel 3 | 1.6995 | 1.82728 | 1.83571 | 1.83572 | 0.00716575 | 0.00716687 | Nivel 3 | 8.45 | Level : Nivel 3 | 8.03 | 8.3 | 1.6995 | 65.8969 | 0 | 0.105
907451 | Nivel 3 | 6.105 | 6.33242 | 6.34085 | 6.34085 | 0.0248328 | 0.0248367 | Nivel 3 | 8.45 | Level : Nivel 3 | 8.03 | 8.3 | 5.8896 | 228.365 | 0 | 0 | 0.0127 | 0.0127
907465 | Nivel 3 | 6.105 | 6.33242 | 6.34085 | 6.34085 | 0.0248328 | 0.0248367 | Nivel 3 | 8.45 | Level : Nivel 3 | 8.03 | 8.3 | 5.8896 | 228.365 | 0 | 0 | 0.0127 | 0.0127
907593 | Nivel 3 | 5.995 | 6.32704 | 6.33547 | 6.33547 | 0.0248117 | 0.0248114 | Nivel 3 | 8.45 | Level : Nivel 3 | 8.03 | 8.3 | 5.8846 | 228.171 | 0 | 0 | 0.0127 | 0.0127
907613 | Nivel 3 | 5.995 | 6.32704 | 6.33547 | 6.33547 | 0.0248117 | 0.0248114 | Nivel 3 | 8.45 | Level : Nivel 3 | 8.03 | 8.3 | 5.8846 | 228.171 | 0 | 0 | 0.0127 | 0.0127
907632 | Nivel 3 | 6 | 6.33242 | 6.34085 | 6.34085 | 0.0248328 | 0.0248367 | Nivel 3 | 8.45 | Level : Nivel 3 | 8.03 | 8.3 | 5.8896 | 228.365 | 0 | 0 | 0.0127 | 0.0127
907653 | Nivel 3 | 6 | 6.33242 | 6.34085 | 6.34085 | 0.0248328 | 0.0248367 | Nivel 3 | 8.45 | Level : Nivel 3 | 8.03 | 8.3 | 5.8896 | 228.365 | 0 | 0 | 0.0127 | 0.0127
907672 | Nivel 3 | 6 | 6.33242 | 6.34085 | 6.34085 | 0.0248328 | 0.0248367 | Nivel 3 | 8.45 | Level : Nivel 3 | 8.03 | 8.3 | 5.8896 | 228.365 | 0 | 0 | 0.0127 | 0.0127
907693 | Nivel 3 | 6 | 6.33242 | 6.34085 | 6.34085 | 0.0248328 | 0.0248367 | Nivel 3 | 8.45 | Level : Nivel 3 | 8.03 | 8.3 | 5.8896 | 228.365 | 0 | 0 | 0.0127 | 0.0127
907714 | Nivel 3 | 6.105 | 6.33242 | 6.34085 | 6.34085 | 0.0248328 | 0.0248367 | Nivel 3 | 8.45 | Level : Nivel 3 | 8.03 | 8.3 | 5.8896 | 228.365 | 0 | 0 | 0.0127 | 0.0127
907733 | Nivel 3 | 6.105 | 6.33242 | 6.34085 | 6.34085 | 0.0248328 | 0.0248367 | Nivel 3 | 8.45 | Level : Nivel 3 | 8.03 | 8.3 | 5.8896 | 228.365 | 0 | 0 | 0.0127 | 0.0127
907752 | Nivel 3 | 6.105 | 6.33242 | 6.34085 | 6.34085 | 0.0248328 | 0.0248367 | Nivel 3 | 8.45 | Level : Nivel 3 | 8.03 | 8.3 | 5.8896 | 228.365 | 0 | 0 | 0.0127 | 0.0127
907771 | Nivel 3 | 6.105 | 6.33242 | 6.34085 | 6.34085 | 0.0248328 | 0.0248367 | Nivel 3 | 8.45 | Level : Nivel 3 | 8.03 | 8.3 | 5.8896 | 228.365 | 0 | 0 | 0.0127 | 0.0127
908346 | Nivel 3 | 5.995 | 6.32704 | 6.33547 | 6.33547 | 0.0248117 | 0.0248114 | Nivel 3 | 8.45 | Level : Nivel 3 | 8.03 | 8.3 | 5.8846 | 228.171 | 0 | 0 | 0.0127 | 0.0127
908428 | Nivel 3 | 5.995 | 6.32704 | 6.33547 | 6.33547 | 0.0248117 | 0.0248114 | Nivel 3 | 8.45 | Level : Nivel 3 | 8.03 | 8.3 | 5.8846 | 228.171 | 0 | 0 | 0.0127 | 0.0127
908466 | Nivel 3 | 4.12 | 4.2143 | 4.22273 | 4.22273 | 0.0165265 | 0.0165263 | Nivel 3 | 8.45 | Level : Nivel 3 | 8.03 | 8.3 | 3.9196 | 151.98 | 0 | 0 | 0.0127 | 0.0127
908759 | Nivel 3 | 6 | 6.33242 | 6.34085 | 6.34085 | 0.0248328 | 0.0248367 | Nivel 3 | 8.45 | Level : Nivel 3 | 8.03 | 8.3 | 5.8896 | 228.365 | 0 | 0 | 0.0127 | 0.0127
908778 | Nivel 3 | 5.995 | 6.32704 | 6.33547 | 6.33547 | 0.0248117 | 0.0248114 | Nivel 3 | 8.45 | Level : Nivel 3 | 8.03 | 8.3 | 5.8846 | 228.171 | 0 | 0 | 0.0127 | 0.0127
908797 | Nivel 3 | 5.995 | 6.32704 | 6.33547 | 6.33547 | 0.0248117 | 0.0248114 | Nivel 3 | 8.45 | Level : Nivel 3 | 8.03 | 8.3 | 5.8846 | 228.171 | 0 | 0 | 0.0127 | 0.0127
908816 | Nivel 3 | 5.995 | 6.32704 | 6.33547 | 6.33547 | 0.0248117 | 0.0248114 | Nivel 3 | 8.45 | Level : Nivel 3 | 8.03 | 8.3 | 5.8846 | 228.171 | 0 | 0 | 0.0127 | 0.0127
908837 | Nivel 3 | 5.995 | 6.32704 | 6.33547 | 6.33547 | 0.0248117 | 0.0248114 | Nivel 3 | 8.45 | Level : Nivel 3 | 8.03 | 8.3 | 5.8846 | 228.171 | 0 | 0 | 0.0127 | 0.0127
908856 | Nivel 3 | 5.995 | 6.32704 | 6.33547 | 6.33547 | 0.0248117 | 0.0248114 | Nivel 3 | 8.45 | Level : Nivel 3 | 8.03 | 8.3 | 5.8846 | 228.171 | 0 | 0 | 0.0127 | 0.0127
908875 | Nivel 3 | 5.995 | 6.32704 | 6.33547 | 6.33547 | 0.0248117 | 0.0248114 | Nivel 3 | 8.45 | Level : Nivel 3 | 8.03 | 8.3 | 5.8846 | 228.171 | 0 | 0 | 0.0127 | 0.0127
908894 | Nivel 3 | 5.995 | 6.32704 | 6.33547 | 6.33547 | 0.0248117 | 0.0248114 | Nivel 3 | 8.45 | Level : Nivel 3 | 8.03 | 8.3 | 5.8846 | 228.171 | 0 | 0 | 0.0127 | 0.0127
908947 | Nivel 3 | 5.995 | 6.32704 | 6.33547 | 6.33547 | 0.0248117 | 0.0248114 | Nivel 3 | 8.45 | Level : Nivel 3 | 8.03 | 8.3 | 5.8846 | 228.171 | 0 | 0 | 0.0127 | 0.0127
909406 | Nivel 3 | 5.995 | 6.32704 | 6.33547 | 6.33547 | 0.0248117 | 0.0248114 | Nivel 3 | 8.45 | Level : Nivel 3 | 8.03 | 8.3 | 5.8846 | 228.171 | 0 | 0 | 0.0127 | 0.0127
909448 | Nivel 3 | 2.3998 | 2.37552 | 2.38395 | 2.38395 | 0.00931568 | 0.00931556 | Nivel 3 | 8.45 | Level : Nivel 3 | 8.03 | 8.3 | 2.2094 | 85.6679 | 0 | 0 | 0.0127 | 0.0127
909899 | Nivel 3 | 0.6569 | 0.502005 | 0.510437 | 0.510437 | 0.00196863 | 0.00196861 | Nivel 3 | 8.45 | Level : Nivel 3 | 8.03 | 8.3 | 0.4669 | 18.1037 | -0.095 | 0 |  | 0

# IfcBeam: M_W Shapes:W330X160mm (89)
Type - PredefinedType: BEAM; Material: Steel, 45-345
Type - Other - Category: Structural Framing; Family Name: M_W Shapes
Type - Identity Data - Code Name: AISC 14.1; OmniClass Number: 23.25.30.11.14.14; OmniClass Title: Beams; Section Name Key: W12x26; Type Name: W330X160mm
Type - Structural - Section Shape: 6
Type - Structural Analysis - Elastic Modulus strong axis: 0.000547 m3; Elastic Modulus weak axis: 0.0000875 m3; Moment of Inertia strong axis: 0.0000849 m4; Moment of Inertia weak axis: 0.0000072 m4; Nominal Weight: 379.516 kg/s2; Perimeter: 1.25 m; Plastic Modulus strong axis: 0.00061 m3; Plastic Modulus weak axis: 0.000134 m3; Section Area: 0.00494 m2; Torsional Moment of Inertia: 1.25e-07 m4; Warping Constant: 1.63e-07 m6
Type - Structural Section Geometry - Centroid Horizontal: 0.08 m; Centroid Vertical: 0.165 m; Flange Thickness: 0.00965 m; Height: 0.33 m; Web Fillet: 0.00765 m; Web Thickness: 0.00584 m; Width: 0.16 m
Type - Pset_BeamCommon - LoadBearing: yes
Classification: B103 (FEMAP58); Material: Steel, 45-345; Steel, 45-345
Pset_BeamCommon - IsExternal: no; Slope: 0 deg; Roll: 0 deg; Reference: M_W Shapes:W330X160mm
Pset_EnvironmentalImpactIndicators - Reference: M_W Shapes:W330X160mm; sets with these values: 2
Qto_BeamBaseQuantities - CrossSectionArea: 0.00495279 m2
Other - Family: M_W Shapes; Family and Type: M_W Shapes: W330X160mm; Type: W330X160mm; Type Id: 901017
Constraints - Cross-Section Rotation: 0 deg; End Level Offset: 0 m; Orientation: Normal; Start Level Offset: 0 m
Materials and Finishes - Structural Material: Steel, 45-345
Phasing - Phase Created: New Construction
Structural - Stick Symbol Location: Center of Geometry; Structural Usage: Primary
Geometric Position - End Extension: 0 m; Join Status: Both joins enabled; Start Extension: 0 m; y Justification: Origin; yz Justification: Uniform; z Justification: Top; z Offset Value: -0.15 m
AboveGround - AboveGround: yes
Name (M_W Shapes:W330X160mm:...) | In | Span (m) = Qto_BeamBaseQuantities, Length (m) = Dimensions, Length (m) | OuterSurfaceArea (m2) | GrossSurfaceArea (m2) | NetSurfaceArea (m2) | GrossVolume (m3) | NetVolume (m3) = Volume (m3) | Reference Level | Reference Level Elevation (m) | Work Plane | Elevation at Bottom (m) | Elevation at Top (m) | Cut Length (m) | Weight (kg) | y Offset Value (m) | End Join Cutback (m) | Start Join Cutback (m)
900224 | Nivel 2 | 3.595 | 4.43076 | 4.44067 | 4.44067 | 0.017209 | 0.0172088 | Nivel 2 | 4.2 | Level : Nivel 2 | 3.72 | 4.05 | 3.4746 | 134.725 | 0 | 0.0127 | 0.0127
900366 | Nivel 2 | 3.595 | 4.43076 | 4.44067 | 4.44067 | 0.017209 | 0.0172088 | Nivel 2 | 4.2 | Level : Nivel 2 | 3.72 | 4.05 | 3.4746 | 134.725 | 0 | 0.0127 | 0.0127
900405 | Nivel 2 | 2.85 | 3.38855 | 3.39846 | 3.39846 | 0.0131611 | 0.0131609 | Nivel 2 | 4.2 | Level : Nivel 2 | 3.72 | 4.05 | 2.6573 | 103.035 | 0 | 0 | 0.0127
900452 | Nivel 2 | 2.95 | 3.51607 | 3.52598 | 3.52598 | 0.0136563 | 0.0136562 | Nivel 2 | 4.2 | Level : Nivel 2 | 3.72 | 4.05 | 2.7573 | 106.912 | 0 | 0.0127 | 0
900538 | Nivel 2 | 2.954 | 3.64525 | 3.65515 | 3.65515 | 0.0141581 | 0.0141579 | Nivel 2 | 4.2 | Level : Nivel 2 | 3.72 | 4.05 | 2.8586 | 110.84 | 0 | 0.0127 | 0.0127
900741 | Nivel 2 | 4.045 | 5.13836 | 5.14827 | 5.14827 | 0.0199573 | 0.019957 | Nivel 2 | 4.2 | Level : Nivel 2 | 3.72 | 4.05 | 4.0295 | 156.241 | 0 | 0.0127 | 0.0127
900743 | Nivel 2 | 4.5 | 5.58468 | 5.59458 | 5.59458 | 0.0216908 | 0.0216905 | Nivel 2 | 4.2 | Level : Nivel 2 | 3.72 | 4.05 | 4.3795 | 169.812 | 0 | 0.0127 | 0.0127
900796 | Nivel 2 | 4.8 | 5.84622 | 5.85613 | 5.85613 | 0.0227066 | 0.0227063 | Nivel 2 | 4.2 | Level : Nivel 2 | 3.72 | 4.05 | 4.5846 | 177.765 | 0 | 0.0127 | 0.0127
900834 | Nivel 2 | 5.995 | 7.50396 | 7.51387 | 7.51387 | 0.0291452 | 0.0291448 | Nivel 2 | 4.2 | Level : Nivel 2 | 3.72 | 4.05 | 5.8846 | 228.171 | 0 | 0.0127 | 0.0127
900915 | Nivel 2 | 3.595 | 4.43076 | 4.44067 | 4.44067 | 0.017209 | 0.0172088 | Nivel 2 | 4.2 | Level : Nivel 2 | 3.72 | 4.05 | 3.4746 | 134.725 | 0 | 0.0127 | 0.0127
900919 | Nivel 2 | 3.85 | 4.62204 | 4.63195 | 4.63195 | 0.0179519 | 0.0179517 | Nivel 2 | 4.2 | Level : Nivel 2 | 3.72 | 4.05 | 3.6246 | 140.541 | 0 | 0.0127 | 0.0127
900983 | Nivel 2 | 3.595 | 4.43076 | 4.44067 | 4.44067 | 0.017209 | 0.0172088 | Nivel 2 | 4.2 | Level : Nivel 2 | 3.72 | 4.05 | 3.4746 | 134.725 | 0 | 0.0127 | 0.0127
900985 | Nivel 2 | 3.85 | 4.62204 | 4.63195 | 4.63195 | 0.0179519 | 0.0179517 | Nivel 2 | 4.2 | Level : Nivel 2 | 3.72 | 4.05 | 3.6246 | 140.541 | 0 | 0.0127 | 0.0127
901073 | Nivel 2 | 6.1 | 7.50396 | 7.51387 | 7.51387 | 0.0291452 | 0.0291448 | Nivel 2 | 4.2 | Level : Nivel 2 | 3.72 | 4.05 | 5.8846 | 228.171 | 0 | 0.0127 | 0.0127
901159 | Nivel 2 | 6.1 | 7.50396 | 7.51387 | 7.51387 | 0.0291452 | 0.0291448 | Nivel 2 | 4.2 | Level : Nivel 2 | 3.72 | 4.05 | 5.8846 | 228.171 | 0 | 0.0127 | 0.0127
901211 | Nivel 2 | 6.1 | 7.50396 | 7.51387 | 7.51387 | 0.0291452 | 0.0291448 | Nivel 2 | 4.2 | Level : Nivel 2 | 3.72 | 4.05 | 5.8846 | 228.171 | 0 | 0.0127 | 0.0127
901266 | Nivel 2 | 6.1 | 7.6413 | 7.6512 | 7.6512 | 0.0296786 | 0.0296783 | Nivel 2 | 4.2 | Level : Nivel 2 | 3.72 | 4.05 | 5.9923 | 232.347 | 0 | 0.0127
901270 | Nivel 2 | 4.12 | 4.99822 | 5.00813 | 5.00813 | 0.019413 | 0.0194127 | Nivel 2 | 4.2 | Level : Nivel 2 | 3.72 | 4.05 | 3.9196 | 151.98 | 0 | 0.0127 | 0.0127
901326 | Nivel 2 | 4.8 | 5.84622 | 5.85613 | 5.85613 | 0.0227066 | 0.0227096 | Nivel 2 | 4.2 | Level : Nivel 2 | 3.72 | 4.05 | 4.5846 | 177.765 | 0 | 0.0127 | 0.0127
901328 | Nivel 2 | 5.995 | 7.50396 | 7.51387 | 7.51387 | 0.0291452 | 0.0291448 | Nivel 2 | 4.2 | Level : Nivel 2 | 3.72 | 4.05 | 5.8846 | 228.171 | 0 | 0.0127 | 0.0127
901818 | Nivel 2 | 5.995 | 7.50396 | 7.51387 | 7.51387 | 0.0291452 | 0.0291448 | Nivel 2 | 4.2 | Level : Nivel 2 | 3.72 | 4.05 | 5.8846 | 228.171 | 0 | 0.0127 | 0.0127
901820 | Nivel 2 | 4.9 | 5.97374 | 5.98364 | 5.98365 | 0.0232019 | 0.0232049 | Nivel 2 | 4.2 | Level : Nivel 2 | 3.72 | 4.05 | 4.6846 | 181.642 | 0 | 0.0127 | 0.0127
901872 | Nivel 2 | 5.995 | 7.50396 | 7.51387 | 7.51387 | 0.0291452 | 0.0291448 | Nivel 2 | 4.2 | Level : Nivel 2 | 3.72 | 4.05 | 5.8846 | 228.171 | 0 | 0.0127 | 0.0127
901874 | Nivel 2 | 4.9 | 5.97374 | 5.98364 | 5.98365 | 0.0232019 | 0.0232049 | Nivel 2 | 4.2 | Level : Nivel 2 | 3.72 | 4.05 | 4.6846 | 181.642 | 0 | 0.0127 | 0.0127
901908 | Nivel 2 | 5.995 | 7.50396 | 7.51387 | 7.51387 | 0.0291452 | 0.0291448 | Nivel 2 | 4.2 | Level : Nivel 2 | 3.72 | 4.05 | 5.8846 | 228.171 | 0 | 0.0127 | 0.0127
901910 | Nivel 2 | 4.795 | 5.97374 | 5.98364 | 5.98365 | 0.0232019 | 0.0232049 | Nivel 2 | 4.2 | Level : Nivel 2 | 3.72 | 4.05 | 4.6846 | 181.642 | 0 | 0.0127 | 0.0127
901927 | Nivel 2 | 5.995 | 7.50396 | 7.51387 | 7.51387 | 0.0291452 | 0.0291448 | Nivel 2 | 4.2 | Level : Nivel 2 | 3.72 | 4.05 | 5.8846 | 228.171 | 0 | 0.0127 | 0.0127
901929 | Nivel 2 | 4.795 | 5.97374 | 5.98364 | 5.98365 | 0.0232019 | 0.0232049 | Nivel 2 | 4.2 | Level : Nivel 2 | 3.72 | 4.05 | 4.6846 | 181.642 | 0 | 0.0127 | 0.0127
901945 | Nivel 2 | 5.995 | 7.50396 | 7.51387 | 7.51387 | 0.0291452 | 0.0291448 | Nivel 2 | 4.2 | Level : Nivel 2 | 3.72 | 4.05 | 5.8846 | 228.171 | 0 | 0.0127 | 0.0127
901947 | Nivel 2 | 4.795 | 5.97374 | 5.98364 | 5.98365 | 0.0232019 | 0.0232049 | Nivel 2 | 4.2 | Level : Nivel 2 | 3.72 | 4.05 | 4.6846 | 181.642 | 0 | 0.0127 | 0.0127
901965 | Nivel 2 | 5.995 | 7.50396 | 7.51387 | 7.51387 | 0.0291452 | 0.0291448 | Nivel 2 | 4.2 | Level : Nivel 2 | 3.72 | 4.05 | 5.8846 | 228.171 | 0 | 0.0127 | 0.0127
901967 | Nivel 2 | 4.795 | 5.97374 | 5.98364 | 5.98365 | 0.0232019 | 0.0232049 | Nivel 2 | 4.2 | Level : Nivel 2 | 3.72 | 4.05 | 4.6846 | 181.642 | 0 | 0.0127 | 0.0127
901983 | Nivel 2 | 5.995 | 7.50396 | 7.51387 | 7.51387 | 0.0291452 | 0.0291448 | Nivel 2 | 4.2 | Level : Nivel 2 | 3.72 | 4.05 | 5.8846 | 228.171 | 0 | 0.0127 | 0.0127
901985 | Nivel 2 | 4.795 | 5.97374 | 5.98364 | 5.98365 | 0.0232019 | 0.0232049 | Nivel 2 | 4.2 | Level : Nivel 2 | 3.72 | 4.05 | 4.6846 | 181.642 | 0 | 0.0127 | 0.0127
902001 | Nivel 2 | 5.995 | 7.50396 | 7.51387 | 7.51387 | 0.0291452 | 0.0291448 | Nivel 2 | 4.2 | Level : Nivel 2 | 3.72 | 4.05 | 5.8846 | 228.171 | 0 | 0.0127 | 0.0127
902003 | Nivel 2 | 4.795 | 5.97374 | 5.98364 | 5.98365 | 0.0232019 | 0.0232049 | Nivel 2 | 4.2 | Level : Nivel 2 | 3.72 | 4.05 | 4.6846 | 181.642 | 0 | 0.0127 | 0.0127
902019 | Nivel 2 | 5.995 | 7.50396 | 7.51387 | 7.51387 | 0.0291452 | 0.0291448 | Nivel 2 | 4.2 | Level : Nivel 2 | 3.72 | 4.05 | 5.8846 | 228.171 | 0 | 0.0127 | 0.0127
902021 | Nivel 2 | 4.8 | 5.84622 | 5.85613 | 5.85613 | 0.0227066 | 0.0227096 | Nivel 2 | 4.2 | Level : Nivel 2 | 3.72 | 4.05 | 4.5846 | 177.765 | 0 | 0.0127 | 0.0127
902037 | Nivel 2 | 5.995 | 7.50396 | 7.51387 | 7.51387 | 0.0291452 | 0.0291448 | Nivel 2 | 4.2 | Level : Nivel 2 | 3.72 | 4.05 | 5.8846 | 228.171 | 0 | 0.0127 | 0.0127
902039 | Nivel 2 | 4.8 | 5.84622 | 5.85613 | 5.85613 | 0.0227066 | 0.0227096 | Nivel 2 | 4.2 | Level : Nivel 2 | 3.72 | 4.05 | 4.5846 | 177.765 | 0 | 0.0127 | 0.0127
902055 | Nivel 2 | 5.3106 | 6.65035 | 6.66026 | 6.66026 | 0.0258298 | 0.0258332 | Nivel 2 | 4.2 | Level : Nivel 2 | 3.72 | 4.05 | 5.2152 | 202.216 | 0 | 0.0127 | 0.0127
902057 | Nivel 2 | 4.8 | 5.84622 | 5.85613 | 5.85613 | 0.0227066 | 0.0227096 | Nivel 2 | 4.2 | Level : Nivel 2 | 3.72 | 4.05 | 4.5846 | 177.765 | 0 | 0.0127 | 0.0127
902101 | Nivel 2 | 3.315 | 4.10559 | 4.1155 | 4.1155 | 0.015946 | 0.0159481 | Nivel 2 | 4.2 | Level : Nivel 2 | 3.72 | 4.05 | 3.2196 | 124.838 | 0 | 0.0127 | 0.0127
902190 | Nivel 2 | 4.795 | 5.97374 | 5.98364 | 5.98365 | 0.0232019 | 0.0232049 | Nivel 2 | 4.2 | Level : Nivel 2 | 3.72 | 4.05 | 4.6846 | 181.642 | 0 | 0.0127 | 0.0127
902805 | Nivel 2 | 6.1 | 7.50396 | 7.51387 | 7.51387 | 0.0291452 | 0.0291448 | Nivel 2 | 4.2 | Level : Nivel 2 | 3.72 | 4.05 | 5.8846 | 228.171 | 0 | 0.0127 | 0.0127
903025 | Nivel 2 | 5.995 | 7.50396 | 7.51387 | 7.51387 | 0.0291452 | 0.0291448 | Nivel 2 | 4.2 | Level : Nivel 2 | 3.72 | 4.05 | 5.8846 | 228.171 | 0 | 0.0127 | 0.0127
903113 | Nivel 2 | 5.995 | 7.50396 | 7.51387 | 7.51387 | 0.0291452 | 0.0291448 | Nivel 2 | 4.2 | Level : Nivel 2 | 3.72 | 4.05 | 5.8846 | 228.171 | 0 | 0.0127 | 0.0127
903159 | Nivel 2 | 4.8 | 5.84622 | 5.85613 | 5.85613 | 0.0227066 | 0.0227096 | Nivel 2 | 4.2 | Level : Nivel 2 | 3.72 | 4.05 | 4.5846 | 177.765 | 0 | 0.0127 | 0.0127
903281 | Nivel 2 | 4 | 4.8452 | 4.8551 | 4.8551 | 0.0188186 | 0.0188184 | Nivel 2 | 4.2 | Level : Nivel 2 | 3.72 | 4.05 | 3.7996 | 147.327 | 0 | 0.0127 | 0.0127
903349 | Nivel 2 | 1.8749 | 2.26919 | 2.2791 | 2.2791 | 0.0088135 | 0.00881339 | Nivel 2 | 4.2 | Level : Nivel 2 | 3.72 | 4.05 | 1.7795 | 68.9989 | 0 | 0.0127 | 0.0127
903640 | Nivel 2 | 5.995 | 7.50396 | 7.51387 | 7.51387 | 0.0291452 | 0.0291448 | Nivel 2 | 4.2 | Level : Nivel 2 | 3.72 | 4.05 | 5.8846 | 228.171 | 0 | 0.0127 | 0.0127
903642 | Nivel 2 | 4.795 | 5.97374 | 5.98364 | 5.98365 | 0.0232019 | 0.0232049 | Nivel 2 | 4.2 | Level : Nivel 2 | 3.72 | 4.05 | 4.6846 | 181.642 | 0 | 0.0127 | 0.0127
903705 | Nivel 2 | 5.995 | 7.50396 | 7.51387 | 7.51387 | 0.0291452 | 0.0291448 | Nivel 2 | 4.2 | Level : Nivel 2 | 3.72 | 4.05 | 5.8846 | 228.171 | 0 | 0.0127 | 0.0127
903707 | Nivel 2 | 4.795 | 5.97374 | 5.98364 | 5.98365 | 0.0232019 | 0.0232049 | Nivel 2 | 4.2 | Level : Nivel 2 | 3.72 | 4.05 | 4.6846 | 181.642 | 0 | 0.0127 | 0.0127
903726 | Nivel 2 | 5.995 | 7.50396 | 7.51387 | 7.51387 | 0.0291452 | 0.0291448 | Nivel 2 | 4.2 | Level : Nivel 2 | 3.72 | 4.05 | 5.8846 | 228.171 | 0 | 0.0127 | 0.0127
903728 | Nivel 2 | 4.795 | 5.97374 | 5.98364 | 5.98365 | 0.0232019 | 0.0232049 | Nivel 2 | 4.2 | Level : Nivel 2 | 3.72 | 4.05 | 4.6846 | 181.642 | 0 | 0.0127 | 0.0127
903744 | Nivel 2 | 5.995 | 7.50396 | 7.51387 | 7.51387 | 0.0291452 | 0.0291448 | Nivel 2 | 4.2 | Level : Nivel 2 | 3.72 | 4.05 | 5.8846 | 228.171 | 0 | 0.0127 | 0.0127
903746 | Nivel 2 | 4.795 | 5.97374 | 5.98364 | 5.98365 | 0.0232019 | 0.0232049 | Nivel 2 | 4.2 | Level : Nivel 2 | 3.72 | 4.05 | 4.6846 | 181.642 | 0 | 0.0127 | 0.0127
903762 | Nivel 2 | 5.995 | 7.50396 | 7.51387 | 7.51387 | 0.0291452 | 0.0291448 | Nivel 2 | 4.2 | Level : Nivel 2 | 3.72 | 4.05 | 5.8846 | 228.171 | 0 | 0.0127 | 0.0127
903764 | Nivel 2 | 4.795 | 5.97374 | 5.98364 | 5.98365 | 0.0232019 | 0.0232049 | Nivel 2 | 4.2 | Level : Nivel 2 | 3.72 | 4.05 | 4.6846 | 181.642 | 0 | 0.0127 | 0.0127
903780 | Nivel 2 | 5.995 | 7.50396 | 7.51387 | 7.51387 | 0.0291452 | 0.0291448 | Nivel 2 | 4.2 | Level : Nivel 2 | 3.72 | 4.05 | 5.8846 | 228.171 | 0 | 0.0127 | 0.0127
903782 | Nivel 2 | 4.795 | 5.97374 | 5.98364 | 5.98365 | 0.0232019 | 0.0232049 | Nivel 2 | 4.2 | Level : Nivel 2 | 3.72 | 4.05 | 4.6846 | 181.642 | 0 | 0.0127 | 0.0127
903798 | Nivel 2 | 5.995 | 7.50396 | 7.51387 | 7.51387 | 0.0291452 | 0.0291448 | Nivel 2 | 4.2 | Level : Nivel 2 | 3.72 | 4.05 | 5.8846 | 228.171 | 0 | 0.0127 | 0.0127
903816 | Nivel 2 | 5.995 | 7.50396 | 7.51387 | 7.51387 | 0.0291452 | 0.0291448 | Nivel 2 | 4.2 | Level : Nivel 2 | 3.72 | 4.05 | 5.8846 | 228.171 | 0 | 0.0127 | 0.0127
903818 | Nivel 2 | 4.9 | 5.97374 | 5.98364 | 5.98365 | 0.0232019 | 0.0232049 | Nivel 2 | 4.2 | Level : Nivel 2 | 3.72 | 4.05 | 4.6846 | 181.642 | 0 | 0.0127 | 0.0127
903834 | Nivel 2 | 5.995 | 7.50396 | 7.51387 | 7.51387 | 0.0291452 | 0.0291448 | Nivel 2 | 4.2 | Level : Nivel 2 | 3.72 | 4.05 | 5.8846 | 228.171 | 0 | 0.0127 | 0.0127
903836 | Nivel 2 | 4.795 | 5.97374 | 5.98364 | 5.98365 | 0.0232019 | 0.0232049 | Nivel 2 | 4.2 | Level : Nivel 2 | 3.72 | 4.05 | 4.6846 | 181.642 | 0 | 0.0127 | 0.0127
903955 | Nivel 2 | 4.12 | 5.11643 | 5.12634 | 5.12634 | 0.0198721 | 0.0198718 | Nivel 2 | 4.2 | Level : Nivel 2 | 3.72 | 4.05 | 4.0123 | 155.574 | 0 |  | 0.0127
904002 | Nivel 2 | 2.38 | 2.7794 | 2.7893 | 2.7893 | 0.0107951 | 0.010795 | Nivel 2 | 4.2 | Level : Nivel 2 | 3.72 | 4.05 | 2.1796 | 84.5124 | -0.105 | 0.0127 | 0.0127
904813 | Nivel 2 | 6 | 7.51034 | 7.52024 | 7.52025 | 0.02917 | 0.0291738 | Nivel 2 | 4.2 | Level : Nivel 2 | 3.72 | 4.05 | 5.8896 | 228.365 | 0 | 0.0127 | 0.0127
904836 | Nivel 2 | 6 | 7.51034 | 7.52024 | 7.52025 | 0.02917 | 0.0291738 | Nivel 2 | 4.2 | Level : Nivel 2 | 3.72 | 4.05 | 5.8896 | 228.365 | 0 | 0.0127 | 0.0127
904855 | Nivel 2 | 5.995 | 7.50396 | 7.51387 | 7.51387 | 0.0291452 | 0.0291448 | Nivel 2 | 4.2 | Level : Nivel 2 | 3.72 | 4.05 | 5.8846 | 228.171 | 0 | 0.0127 | 0.0127
904875 | Nivel 2 | 5.995 | 7.50396 | 7.51387 | 7.51387 | 0.0291452 | 0.0291448 | Nivel 2 | 4.2 | Level : Nivel 2 | 3.72 | 4.05 | 5.8846 | 228.171 | 0 | 0.0127 | 0.0127
904894 | Nivel 2 | 5.995 | 7.50396 | 7.51387 | 7.51387 | 0.0291452 | 0.0291448 | Nivel 2 | 4.2 | Level : Nivel 2 | 3.72 | 4.05 | 5.8846 | 228.171 | 0 | 0.0127 | 0.0127
904913 | Nivel 2 | 5.995 | 7.50396 | 7.51387 | 7.51387 | 0.0291452 | 0.0291448 | Nivel 2 | 4.2 | Level : Nivel 2 | 3.72 | 4.05 | 5.8846 | 228.171 | 0 | 0.0127 | 0.0127
904932 | Nivel 2 | 5.995 | 7.5074 | 7.51731 | 7.51731 | 0.0291586 | 0.0291624 | Nivel 2 | 4.2 | Level : Nivel 2 | 3.72 | 4.05 | 5.8873 | 228.276 | 0 |  | 0.0127
904951 | Nivel 2 | 5.995 | 7.5074 | 7.51731 | 7.51731 | 0.0291586 | 0.0291624 | Nivel 2 | 4.2 | Level : Nivel 2 | 3.72 | 4.05 | 5.8873 | 228.276 | 0 |  | 0.0127
904972 | Nivel 2 | 5.995 | 7.5074 | 7.51731 | 7.51731 | 0.0291586 | 0.0291624 | Nivel 2 | 4.2 | Level : Nivel 2 | 3.72 | 4.05 | 5.8873 | 228.276 | 0 |  | 0.0127
905135 | Nivel 2 | 1.02 | 1.06427 | 1.07418 | 1.07418 | 0.0041336 | 0.00413355 | Nivel 2 | 4.2 | Level : Nivel 2 | 3.72 | 4.05 | 0.8346 | 32.361 | 0 | 0.0127 | 0.0127
906447 | Nivel 3 | 2.98 | 3.54451 | 3.55441 | 3.55442 | 0.0137668 | 0.0137686 | Nivel 3 | 8.45 | Level : Nivel 3 | 7.97 | 8.3 | 2.7796 | 107.777 | 0.105 | 0.0127 | 0.0127
906533 | Nivel 3 | 5.995 | 7.50396 | 7.51387 | 7.51387 | 0.0291452 | 0.0291448 | Nivel 3 | 8.45 | Level : Nivel 3 | 7.97 | 8.3 | 5.8846 | 228.171 | 0 | 0.0127 | 0.0127
907869 | Nivel 3 | 3.595 | 4.44351 | 4.45342 | 4.45342 | 0.0172585 | 0.0172608 | Nivel 3 | 8.45 | Level : Nivel 3 | 7.97 | 8.3 | 3.4846 | 135.113 | 0 | 0.0127 | 0.0127
907975 | Nivel 3 | 3.595 | 4.44351 | 4.45342 | 4.45342 | 0.0172585 | 0.0172608 | Nivel 3 | 8.45 | Level : Nivel 3 | 7.97 | 8.3 | 3.4846 | 135.113 | 0 | 0.0127 | 0.0127
908051 | Nivel 3 | 3.595 | 4.44351 | 4.45342 | 4.45342 | 0.0172585 | 0.0172608 | Nivel 3 | 8.45 | Level : Nivel 3 | 7.97 | 8.3 | 3.4846 | 135.113 | 0 | 0.0127 | 0.0127
908055 | Nivel 3 | 3.85 | 4.76869 | 4.77859 | 4.7786 | 0.0185215 | 0.0185239 | Nivel 3 | 8.45 | Level : Nivel 3 | 7.97 | 8.3 | 3.7396 | 145 | 0 | 0.0127 | 0.0127
908160 | Nivel 3 | 3.595 | 4.44351 | 4.45342 | 4.45342 | 0.0172585 | 0.0172608 | Nivel 3 | 8.45 | Level : Nivel 3 | 7.97 | 8.3 | 3.4846 | 135.113 | 0 | 0.0127 | 0.0127
908164 | Nivel 3 | 3.85 | 4.76869 | 4.77859 | 4.7786 | 0.0185215 | 0.0185239 | Nivel 3 | 8.45 | Level : Nivel 3 | 7.97 | 8.3 | 3.7396 | 145 | 0 | 0.0127 | 0.0127
908447 | Nivel 3 | 5.995 | 7.50396 | 7.51387 | 7.51387 | 0.0291452 | 0.0291448 | Nivel 3 | 8.45 | Level : Nivel 3 | 7.97 | 8.3 | 5.8846 | 228.171 | 0 | 0.0127 | 0.0127
908528 | Nivel 3 | 2.98 | 3.54451 | 3.55441 | 3.55442 | 0.0137668 | 0.0137686 | Nivel 3 | 8.45 | Level : Nivel 3 | 7.97 | 8.3 | 2.7796 | 107.777 | 0 | 0.0127 | 0.0127

# IfcBeam: M_W Shapes:W360X170mm (8)
Type - PredefinedType: BEAM; Material: Steel, 45-345
Type - Other - Category: Structural Framing; Family Name: M_W Shapes
Type - Identity Data - Code Name: AISC 14.1; OmniClass Number: 23.25.30.11.14.14; OmniClass Title: Beams; Section Name Key: W12x26; Type Name: W360X170mm
Type - Structural - Section Shape: 6
Type - Structural Analysis - Elastic Modulus strong axis: 0.000547 m3; Elastic Modulus weak axis: 0.0000875 m3; Moment of Inertia strong axis: 0.0000849 m4; Moment of Inertia weak axis: 0.0000072 m4; Nominal Weight: 379.516 kg/s2; Perimeter: 1.25 m; Plastic Modulus strong axis: 0.00061 m3; Plastic Modulus weak axis: 0.000134 m3; Section Area: 0.00494 m2; Torsional Moment of Inertia: 1.25e-07 m4; Warping Constant: 1.63e-07 m6
Type - Structural Section Geometry - Centroid Horizontal: 0.085 m; Centroid Vertical: 0.18 m; Flange Thickness: 0.00965 m; Height: 0.36 m; Web Fillet: 0.00765 m; Web Thickness: 0.00584 m; Width: 0.17 m
Type - Pset_BeamCommon - LoadBearing: yes
Classification: B103 (FEMAP58); Material: Steel, 45-345; Steel, 45-345
Pset_BeamCommon - IsExternal: no; Slope: 0 deg; Roll: 0 deg; Reference: M_W Shapes:W360X170mm
Pset_EnvironmentalImpactIndicators - Reference: M_W Shapes:W360X170mm; sets with these values: 2
Qto_BeamBaseQuantities - CrossSectionArea: 0.005321 m2
Other - Family: M_W Shapes; Family and Type: M_W Shapes: W360X170mm; Type: W360X170mm; Type Id: 903538
Constraints - Cross-Section Rotation: 0 deg; End Level Offset: 0 m; Orientation: Normal; Start Level Offset: 0 m
Materials and Finishes - Structural Material: Steel, 45-345
Phasing - Phase Created: New Construction
Structural - Stick Symbol Location: Center of Geometry; Structural Usage: Primary
Geometric Position - End Extension: 0 m; Join Status: Both joins enabled; Start Extension: 0 m; y Justification: Origin; yz Justification: Uniform; z Justification: Top; y Offset Value: 0 m; End Join Cutback: 0.0127 m; Start Join Cutback: 0.0127 m; z Offset Value: -0.15 m
AboveGround - AboveGround: yes
Name (M_W Shapes:W360X170mm:...) | In | Span (m) = Qto_BeamBaseQuantities, Length (m) = Dimensions, Length (m) | OuterSurfaceArea (m2) | GrossSurfaceArea (m2) = NetSurfaceArea (m2) | GrossVolume (m3) | NetVolume (m3) = Volume (m3) | Reference Level | Reference Level Elevation (m) | Work Plane | Elevation at Bottom (m) | Elevation at Top (m) | Cut Length (m) | Weight (kg)
900226 | Nivel 2 | 5.995 | 8.07867 | 8.08931 | 0.0312587 | 0.0312583 | Nivel 2 | 4.2 | Level : Nivel 2 | 3.69 | 4.05 | 5.8746 | 227.783
900368 | Nivel 2 | 5.995 | 8.07867 | 8.08931 | 0.0312587 | 0.0312583 | Nivel 2 | 4.2 | Level : Nivel 2 | 3.69 | 4.05 | 5.8746 | 227.783
900917 | Nivel 2 | 6 | 7.9274 | 7.93804 | 0.0306734 | 0.030673 | Nivel 2 | 4.2 | Level : Nivel 2 | 3.69 | 4.05 | 5.7646 | 223.518
900987 | Nivel 2 | 6 | 7.9274 | 7.93804 | 0.0306734 | 0.030673 | Nivel 2 | 4.2 | Level : Nivel 2 | 3.69 | 4.05 | 5.7646 | 223.518
907871 | Nivel 3 | 6 | 8.0993 | 8.10994 | 0.0313386 | 0.0313382 | Nivel 3 | 8.45 | Level : Nivel 3 | 7.94 | 8.3 | 5.8896 | 228.365
907977 | Nivel 3 | 6 | 8.0993 | 8.10994 | 0.0313386 | 0.0313382 | Nivel 3 | 8.45 | Level : Nivel 3 | 7.94 | 8.3 | 5.8896 | 228.365
908053 | Nivel 3 | 6 | 7.9549 | 7.96555 | 0.0307798 | 0.0307795 | Nivel 3 | 8.45 | Level : Nivel 3 | 7.94 | 8.3 | 5.7846 | 224.294
908162 | Nivel 3 | 6 | 7.9549 | 7.96555 | 0.0307798 | 0.0307795 | Nivel 3 | 8.45 | Level : Nivel 3 | 7.94 | 8.3 | 5.7846 | 224.294

# IfcBeam: M_W Shapes:W450X190mm (285)
Type - PredefinedType: BEAM; Material: Steel, 45-345
Type - Other - Category: Structural Framing; Family Name: M_W Shapes
Type - Identity Data - Code Name: AISC 14.1; OmniClass Number: 23.25.30.11.14.14; OmniClass Title: Beams; Section Name Key: W12x26; Type Name: W450X190mm
Type - Structural - Section Shape: 6
Type - Structural Analysis - Elastic Modulus strong axis: 0.000547 m3; Elastic Modulus weak axis: 0.0000875 m3; Moment of Inertia strong axis: 0.0000849 m4; Moment of Inertia weak axis: 0.0000072 m4; Nominal Weight: 379.516 kg/s2; Perimeter: 1.25 m; Plastic Modulus strong axis: 0.00061 m3; Plastic Modulus weak axis: 0.000134 m3; Section Area: 0.00494 m2; Torsional Moment of Inertia: 1.25e-07 m4; Warping Constant: 1.63e-07 m6
Type - Structural Section Geometry - Centroid Horizontal: 0.095 m; Centroid Vertical: 0.225 m; Flange Thickness: 0.00965 m; Height: 0.45 m; Web Fillet: 0.00765 m; Web Thickness: 0.00584 m; Width: 0.19 m
Type - Pset_BeamCommon - LoadBearing: yes
Classification: B103 (FEMAP58); Material: Steel, 45-345; Steel, 45-345
Pset_BeamCommon - IsExternal: no; Reference: M_W Shapes:W450X190mm; Slope: 0 deg; Roll: 0 deg
Pset_EnvironmentalImpactIndicators - Reference: M_W Shapes:W450X190mm; sets with these values: 2
Qto_BeamBaseQuantities - CrossSectionArea: 0.00623261 m2
Other - Family: M_W Shapes; Family and Type: M_W Shapes: W450X190mm; Type: W450X190mm; Type Id: 809586
Constraints - Cross-Section Rotation: 0 deg; End Level Offset: 0 m; Orientation: Normal; Start Level Offset: 0 m
Materials and Finishes - Structural Material: Steel, 45-345
Phasing - Phase Created: New Construction
Structural - Stick Symbol Location: Center of Geometry; Structural Usage: Primary
Geometric Position - Join Status: Both joins enabled; y Justification: Origin; yz Justification: Uniform; z Justification: Top; z Offset Value: -0.15 m
AboveGround - AboveGround: yes
Name (M_W Shapes:W450X190mm:...) | In | Span (m) = Qto_BeamBaseQuantities, Length (m) = Dimensions, Length (m) | OuterSurfaceArea (m2) | GrossSurfaceArea (m2) | NetSurfaceArea (m2) | GrossVolume (m3) | NetVolume (m3) = Volume (m3) | Reference Level | Reference Level Elevation (m) | Work Plane | Elevation at Bottom (m) | Elevation at Top (m) | Cut Length (m) | End Attachment Type | Start Attachment Type | Weight (kg) | End Extension (m) | End Join Cutback (m) | Start Extension (m) | Start Join Cutback (m) | y Offset Value (m)
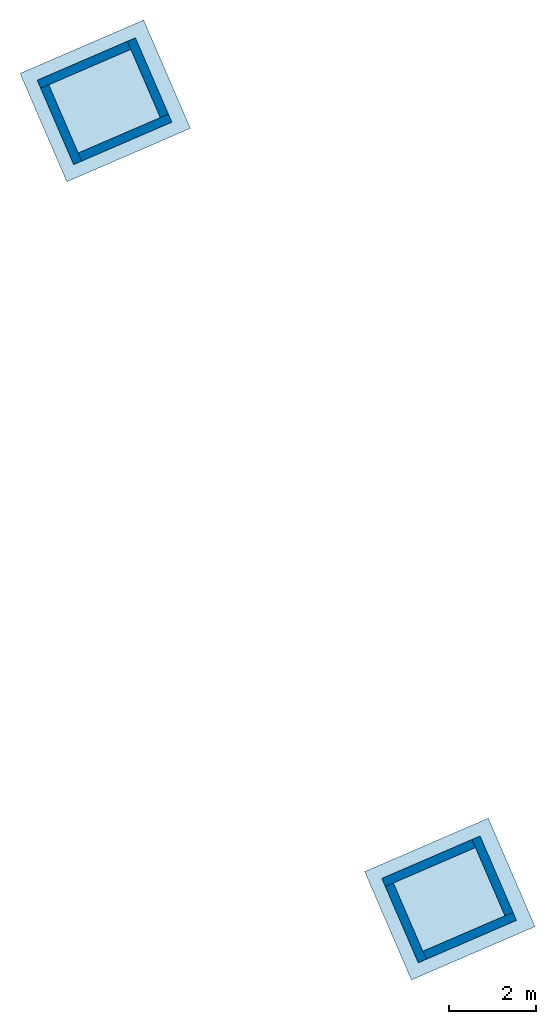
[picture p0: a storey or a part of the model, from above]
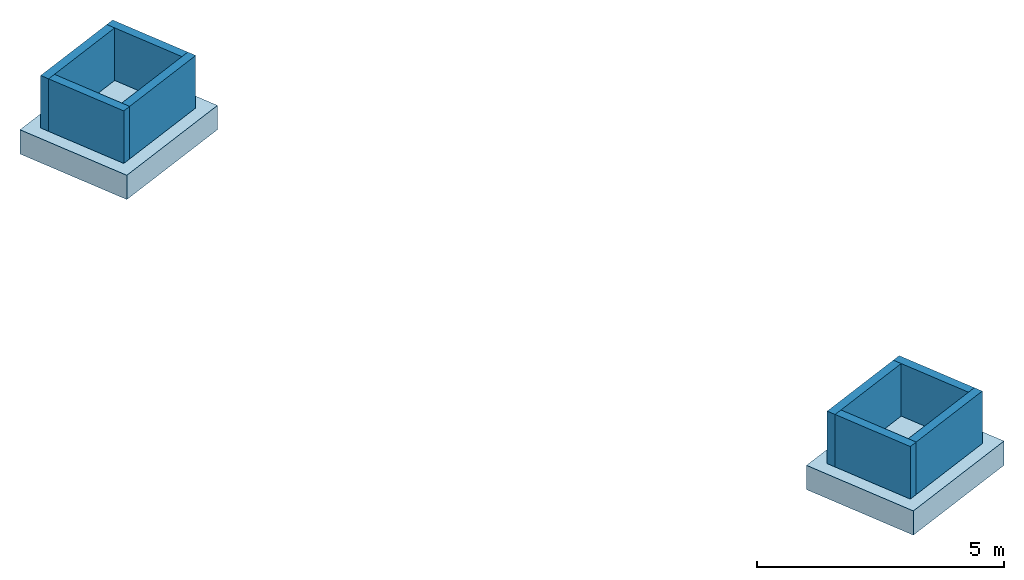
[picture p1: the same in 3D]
Properties of the parts of a building model (IFC4), part 2 of 4

# IfcBeam: M_W Shapes:W450X190mm (285)
Name (M_W Shapes:W450X190mm:...) | In | Span (m) = Qto_BeamBaseQuantities, Length (m) = Dimensions, Length (m) | OuterSurfaceArea (m2) | GrossSurfaceArea (m2) | NetSurfaceArea (m2) | GrossVolume (m3) | NetVolume (m3) = Volume (m3) | Reference Level | Reference Level Elevation (m) | Work Plane | Elevation at Bottom (m) | Elevation at Top (m) | Cut Length (m) | End Attachment Type | Start Attachment Type | Weight (kg) | End Extension (m) | End Join Cutback (m) | Start Extension (m) | Start Join Cutback (m) | y Offset Value (m)
763880 | Nivel 2 | 6 | 9.11551 | 9.12798 | 9.12798 | 0.0347443 | 0.0347439 | Nivel 2 | 4.2 | Level : Nivel 2 | 3.6 | 4.05 | 5.5746 | End Elevation | End Elevation | 216.151 | 0 | 0.0127 | 0 | 0.0127 | 0.105
763954 | Nivel 2 | 6 | 9.11551 | 9.12798 | 9.12798 | 0.0347443 | 0.0347439 | Nivel 2 | 4.2 | Level : Nivel 2 | 3.6 | 4.05 | 5.5746 | End Elevation | End Elevation | 216.151 | 0 | 0.0127 | 0 | 0.0127 | 0
763964 | Nivel 2 | 6 | 9.11551 | 9.12798 | 9.12798 | 0.0347443 | 0.0347439 | Nivel 2 | 4.2 | Level : Nivel 2 | 3.6 | 4.05 | 5.5746 | End Elevation | End Elevation | 216.151 | 0 | 0.0127 | 0 | 0.0127 | 0
763974 | Nivel 2 | 6 | 9.11551 | 9.12798 | 9.12798 | 0.0347443 | 0.0347439 | Nivel 2 | 4.2 | Level : Nivel 2 | 3.6 | 4.05 | 5.5746 | End Elevation | End Elevation | 216.151 | 0 | 0.0127 | 0 | 0.0127 | 0
763986 | Nivel 2 | 4.14 | 5.4429 | 5.45537 | 5.45537 | 0.020746 | 0.0207457 | Nivel 2 | 4.2 | Level : Nivel 2 | 3.6 | 4.05 | 3.32861 |  | End Elevation | 129.065 | -0.598686 |  | 0 | 0.0127 | 0
763996 | Nivel 2 | 6 | 9.11551 | 9.12798 | 9.12798 | 0.0347443 | 0.0347439 | Nivel 2 | 4.2 | Level : Nivel 2 | 3.6 | 4.05 | 5.5746 | End Elevation | End Elevation | 216.151 | 0 | 0.0127 | 0 | 0.0127 | -0.105
764055 | Nivel 2 | 4.8 | 7.15329 | 7.16575 | 7.16576 | 0.0272652 | 0.027268 | Nivel 2 | 4.2 | Level : Nivel 2 | 3.6 | 4.05 | 4.3746 | End Elevation | End Elevation | 169.622 | 0 | 0.0127 | 0 | 0.0127 | 0.105
764114 | Nivel 2 | 4.8 | 7.15329 | 7.16575 | 7.16576 | 0.0272652 | 0.027268 | Nivel 2 | 4.2 | Level : Nivel 2 | 3.6 | 4.05 | 4.3746 | End Elevation | End Elevation | 169.622 | 0 | 0.0127 | 0 | 0.0127 | 0
764124 | Nivel 2 | 4.8 | 7.15329 | 7.16575 | 7.16576 | 0.0272652 | 0.027268 | Nivel 2 | 4.2 | Level : Nivel 2 | 3.6 | 4.05 | 4.3746 | End Elevation | End Elevation | 169.622 | 0 | 0.0127 | 0 | 0.0127 | 0
764134 | Nivel 2 | 4.8 | 7.15329 | 7.16575 | 7.16576 | 0.0272652 | 0.027268 | Nivel 2 | 4.2 | Level : Nivel 2 | 3.6 | 4.05 | 4.3746 | End Elevation | End Elevation | 169.622 | 0 | 0.0127 | 0 | 0.0127 | 0
764146 | Nivel 2 | 4.8 | 7.15329 | 7.16575 | 7.16576 | 0.0272652 | 0.027268 | Nivel 2 | 4.2 | Level : Nivel 2 | 3.6 | 4.05 | 4.3746 | End Elevation | End Elevation | 169.622 | 0 | 0.0127 | 0 | 0.0127 | 0
764156 | Nivel 2 | 4.8 | 7.15329 | 7.16575 | 7.16576 | 0.0272652 | 0.027268 | Nivel 2 | 4.2 | Level : Nivel 2 | 3.6 | 4.05 | 4.3746 | End Elevation | End Elevation | 169.622 | 0 | 0.0127 | 0 | 0.0127 | -0.105
764197 | Nivel 2 | 7.2 | 11.0777 | 11.0902 | 11.0902 | 0.0422235 | 0.0422278 | Nivel 2 | 4.2 | Level : Nivel 2 | 3.6 | 4.05 | 6.7746 | End Elevation | End Elevation | 262.68 | 0 | 0.0127 | 0 | 0.0127 | 0.105
764254 | Nivel 2 | 7.2 | 11.0777 | 11.0902 | 11.0902 | 0.0422235 | 0.0422278 | Nivel 2 | 4.2 | Level : Nivel 2 | 3.6 | 4.05 | 6.7746 | End Elevation | End Elevation | 262.68 | 0 | 0.0127 | 0 | 0.0127 | 0
764262 | Nivel 2 | 7.2 | 11.0777 | 11.0902 | 11.0902 | 0.0422235 | 0.0422278 | Nivel 2 | 4.2 | Level : Nivel 2 | 3.6 | 4.05 | 6.7746 | End Elevation | End Elevation | 262.68 | 0 | 0.0127 | 0 | 0.0127 | 0
764272 | Nivel 2 | 7.2 | 11.0777 | 11.0902 | 11.0902 | 0.0422235 | 0.0422278 | Nivel 2 | 4.2 | Level : Nivel 2 | 3.6 | 4.05 | 6.7746 | End Elevation | End Elevation | 262.68 | 0 | 0.0127 | 0 | 0.0127 | 0
764282 | Nivel 2 | 7.2 | 11.0777 | 11.0902 | 11.0902 | 0.0422235 | 0.0422278 | Nivel 2 | 4.2 | Level : Nivel 2 | 3.6 | 4.05 | 6.7746 | End Elevation | End Elevation | 262.68 | 0 | 0.0127 | 0 | 0.0127 | 0
764292 | Nivel 2 | 7.2 | 11.0777 | 11.0902 | 11.0902 | 0.0422235 | 0.0422278 | Nivel 2 | 4.2 | Level : Nivel 2 | 3.6 | 4.05 | 6.7746 | End Elevation | End Elevation | 262.68 | 0 | 0.0127 | 0 | 0.0127 | 0
764302 | Nivel 2 | 7.2 | 11.0777 | 11.0902 | 11.0902 | 0.0422235 | 0.0422278 | Nivel 2 | 4.2 | Level : Nivel 2 | 3.6 | 4.05 | 6.7746 | End Elevation | End Elevation | 262.68 | 0 | 0.0127 | 0 | 0.0127 | 0
764312 | Nivel 2 | 7.2 | 11.0777 | 11.0902 | 11.0902 | 0.0422235 | 0.0422278 | Nivel 2 | 4.2 | Level : Nivel 2 | 3.6 | 4.05 | 6.7746 | End Elevation | End Elevation | 262.68 | 0 | 0.0127 | 0 | 0.0127 | 0
764320 | Nivel 2 | 7.2 | 11.0777 | 11.0902 | 11.0902 | 0.0422235 | 0.0422278 | Nivel 2 | 4.2 | Level : Nivel 2 | 3.6 | 4.05 | 6.7746 | End Elevation | End Elevation | 262.68 | 0 | 0.0127 | 0 | 0.0127 | -0.105
764577 | Nivel 2 | 8.55 | 13.2852 | 13.2977 | 13.2977 | 0.0506375 | 0.0506426 | Nivel 2 | 4.2 | Level : Nivel 2 | 3.6 | 4.05 | 8.1246 | End Elevation | End Elevation | 315.026 | 0 | 0.0127 | 0 | 0.0127 | 0.105
764587 | Nivel 2 | 8.55 | 13.2852 | 13.2977 | 13.2977 | 0.0506375 | 0.0506426 | Nivel 2 | 4.2 | Level : Nivel 2 | 3.6 | 4.05 | 8.1246 | End Elevation | End Elevation | 315.026 | 0 | 0.0127 | 0 | 0.0127 | -0.105
764649 | Nivel 2 | 4.8 | 7.15329 | 7.16575 | 7.16576 | 0.0272652 | 0.027268 | Nivel 2 | 4.2 | Level : Nivel 2 | 3.6 | 4.05 | 4.3746 | End Elevation | End Elevation | 169.622 | 0 | 0.0127 | 0 | 0.0127 | 0.105
764709 | Nivel 2 | 4.8 | 7.15329 | 7.16575 | 7.16576 | 0.0272652 | 0.027268 | Nivel 2 | 4.2 | Level : Nivel 2 | 3.6 | 4.05 | 4.3746 | End Elevation | End Elevation | 169.622 | 0 | 0.0127 | 0 | 0.0127 | 0
764719 | Nivel 2 | 4.8 | 7.15329 | 7.16575 | 7.16576 | 0.0272652 | 0.027268 | Nivel 2 | 4.2 | Level : Nivel 2 | 3.6 | 4.05 | 4.3746 | End Elevation | End Elevation | 169.622 | 0 | 0.0127 | 0 | 0.0127 | 0
764729 | Nivel 2 | 4.8 | 7.15329 | 7.16575 | 7.16576 | 0.0272652 | 0.027268 | Nivel 2 | 4.2 | Level : Nivel 2 | 3.6 | 4.05 | 4.3746 | End Elevation | End Elevation | 169.622 | 0 | 0.0127 | 0 | 0.0127 | 0
764741 | Nivel 2 | 4.8 | 7.15329 | 7.16575 | 7.16576 | 0.0272652 | 0.027268 | Nivel 2 | 4.2 | Level : Nivel 2 | 3.6 | 4.05 | 4.3746 | End Elevation | End Elevation | 169.622 | 0 | 0.0127 | 0 | 0.0127 | 0
764751 | Nivel 2 | 4.8 | 7.15329 | 7.16575 | 7.16576 | 0.0272652 | 0.027268 | Nivel 2 | 4.2 | Level : Nivel 2 | 3.6 | 4.05 | 4.3746 | End Elevation | End Elevation | 169.622 | 0 | 0.0127 | 0 | 0.0127 | 0
764818 | Nivel 2 | 7.2 | 11.0777 | 11.0902 | 11.0902 | 0.0422235 | 0.0422278 | Nivel 2 | 4.2 | Level : Nivel 2 | 3.6 | 4.05 | 6.7746 | End Elevation | End Elevation | 262.68 | 0 | 0.0127 | 0 | 0.0127 | 0.105
764847 | Nivel 2 | 7.2 | 11.0777 | 11.0902 | 11.0902 | 0.0422235 | 0.0422278 | Nivel 2 | 4.2 | Level : Nivel 2 | 3.6 | 4.05 | 6.7746 | End Elevation | End Elevation | 262.68 | 0 | 0.0127 | 0 | 0.0127 | 0
764890 | Nivel 2 | 7.2 | 11.0777 | 11.0902 | 11.0902 | 0.0422235 | 0.0422278 | Nivel 2 | 4.2 | Level : Nivel 2 | 3.6 | 4.05 | 6.7746 | End Elevation | End Elevation | 262.68 | 0 | 0.0127 | 0 | 0.0127 | -0.105
764938 | Nivel 2 | 7.2 | 11.0777 | 11.0902 | 11.0902 | 0.0422235 | 0.0422278 | Nivel 2 | 4.2 | Level : Nivel 2 | 3.6 | 4.05 | 6.7746 | End Elevation | End Elevation | 262.68 | 0 | 0.0127 | 0 | 0.0127 | 0.105
764963 | Nivel 2 | 7.2 | 11.0777 | 11.0902 | 11.0902 | 0.0422235 | 0.0422278 | Nivel 2 | 4.2 | Level : Nivel 2 | 3.6 | 4.05 | 6.7746 | End Elevation | End Elevation | 262.68 | 0 | 0.0127 | 0 | 0.0127 | 0
765004 | Nivel 2 | 7.2 | 11.0777 | 11.0902 | 11.0902 | 0.0422235 | 0.0422278 | Nivel 2 | 4.2 | Level : Nivel 2 | 3.6 | 4.05 | 6.7746 | End Elevation | End Elevation | 262.68 | 0 | 0.0127 | 0 | 0.0127 | -0.105
765054 | Nivel 2 | 7.2 | 11.0777 | 11.0902 | 11.0902 | 0.0422235 | 0.0422278 | Nivel 2 | 4.2 | Level : Nivel 2 | 3.6 | 4.05 | 6.7746 | End Elevation | End Elevation | 262.68 | 0 | 0.0127 | 0 | 0.0127 | 0.105
765076 | Nivel 2 | 7.2 | 11.0777 | 11.0902 | 11.0902 | 0.0422235 | 0.0422278 | Nivel 2 | 4.2 | Level : Nivel 2 | 3.6 | 4.05 | 6.7746 | End Elevation | End Elevation | 262.68 | 0 | 0.0127 | 0 | 0.0127 | 0
765108 | Nivel 2 | 7.2 | 11.0777 | 11.0902 | 11.0902 | 0.0422235 | 0.0422278 | Nivel 2 | 4.2 | Level : Nivel 2 | 3.6 | 4.05 | 6.7746 | End Elevation | End Elevation | 262.68 | 0 | 0.0127 | 0 | 0.0127 | -0.105
765156 | Nivel 2 | 7.2 | 11.0777 | 11.0902 | 11.0902 | 0.0422235 | 0.0422278 | Nivel 2 | 4.2 | Level : Nivel 2 | 3.6 | 4.05 | 6.7746 | End Elevation | End Elevation | 262.68 | 0 | 0.0127 | 0 | 0.0127 | 0.105
765182 | Nivel 2 | 7.2 | 11.0777 | 11.0902 | 11.0902 | 0.0422235 | 0.0422278 | Nivel 2 | 4.2 | Level : Nivel 2 | 3.6 | 4.05 | 6.7746 | End Elevation | End Elevation | 262.68 | 0 | 0.0127 | 0 | 0.0127 | 0
765227 | Nivel 2 | 3.6 | 5.19106 | 5.20353 | 5.20353 | 0.019786 | 0.0197881 | Nivel 2 | 4.2 | Level : Nivel 2 | 3.6 | 4.05 | 3.1746 | End Elevation | End Elevation | 123.093 | 0 | 0.0127 | 0 | 0.0127 | 0.105
765250 | Nivel 2 | 3.6 | 5.19106 | 5.20353 | 5.20353 | 0.019786 | 0.0197881 | Nivel 2 | 4.2 | Level : Nivel 2 | 3.6 | 4.05 | 3.1746 | End Elevation | End Elevation | 123.093 | 0 | 0.0127 | 0 | 0.0127 | 0
765292 | Nivel 2 | 3.6 | 5.19106 | 5.20353 | 5.20353 | 0.019786 | 0.0197881 | Nivel 2 | 4.2 | Level : Nivel 2 | 3.6 | 4.05 | 3.1746 | End Elevation | End Elevation | 123.093 | 0 | 0.0127 | 0 | 0.0127 | 0
765330 | Nivel 2 | 3.6 | 5.19106 | 5.20353 | 5.20353 | 0.019786 | 0.0197881 | Nivel 2 | 4.2 | Level : Nivel 2 | 3.6 | 4.05 | 3.1746 | End Elevation | End Elevation | 123.093 | 0 | 0.0127 | 0 | 0.0127 | 0
765367 | Nivel 2 | 3.6 | 5.19106 | 5.20353 | 5.20353 | 0.019786 | 0.0197881 | Nivel 2 | 4.2 | Level : Nivel 2 | 3.6 | 4.05 | 3.1746 | End Elevation | End Elevation | 123.093 | 0 | 0.0127 | 0 | 0.0127 | 0
765454 | Nivel 2 | 7.2 | 11.0777 | 11.0902 | 11.0902 | 0.0422235 | 0.0422278 | Nivel 2 | 4.2 | Level : Nivel 2 | 3.6 | 4.05 | 6.7746 | End Elevation | End Elevation | 262.68 | 0 | 0.0127 | 0 | 0.0127 | 0.105
765499 | Nivel 2 | 7.2 | 11.0777 | 11.0902 | 11.0902 | 0.0422235 | 0.0422278 | Nivel 2 | 4.2 | Level : Nivel 2 | 3.6 | 4.05 | 6.7746 | End Elevation | End Elevation | 262.68 | 0 | 0.0127 | 0 | 0.0127 | 0
765533 | Nivel 2 | 7.2 | 11.0777 | 11.0902 | 11.0902 | 0.0422235 | 0.0422278 | Nivel 2 | 4.2 | Level : Nivel 2 | 3.6 | 4.05 | 6.7746 | End Elevation | End Elevation | 262.68 | 0 | 0.0127 | 0 | 0.0127 | 0.105
765563 | Nivel 2 | 7.2 | 11.0777 | 11.0902 | 11.0902 | 0.0422235 | 0.0422278 | Nivel 2 | 4.2 | Level : Nivel 2 | 3.6 | 4.05 | 6.7746 | End Elevation | End Elevation | 262.68 | 0 | 0.0127 | 0 | 0.0127 | 0
765614 | Nivel 2 | 2.25 | 3.14708 | 3.15954 | 3.15955 | 0.0119953 | 0.0119965 | Nivel 2 | 4.2 | Level : Nivel 2 | 3.6 | 4.05 | 1.9246 | End Elevation | End Elevation | 74.625 | 0 | 0.0127 | 0 | 0.0127 | 0.105
765671 | Nivel 2 | 6 | 9.11551 | 9.12798 | 9.12798 | 0.0347443 | 0.0347439 | Nivel 2 | 4.2 | Level : Nivel 2 | 3.6 | 4.05 | 5.5746 | End Elevation | End Elevation | 216.151 | 0 | 0.0127 | 0 | 0.0127 | 0
765694 | Nivel 2 | 7.2 | 11.0777 | 11.0902 | 11.0902 | 0.0422235 | 0.0422278 | Nivel 2 | 4.2 | Level : Nivel 2 | 3.6 | 4.05 | 6.7746 | End Elevation | End Elevation | 262.68 | 0 | 0.0127 | 0 | 0.0127 | -0.105
765727 | Nivel 2 | 6 | 9.11551 | 9.12798 | 9.12798 | 0.0347443 | 0.0347439 | Nivel 2 | 4.2 | Level : Nivel 2 | 3.6 | 4.05 | 5.5746 | End Elevation | End Elevation | 216.151 | 0 | 0.0127 | 0 | 0.0127 | 0
765763 | Nivel 2 | 7.2 | 11.0777 | 11.0902 | 11.0902 | 0.0422235 | 0.0422278 | Nivel 2 | 4.2 | Level : Nivel 2 | 3.6 | 4.05 | 6.7746 | End Elevation | End Elevation | 262.68 | 0 | 0.0127 | 0 | 0.0127 | -0.105
765788 | Nivel 2 | 6 | 9.11551 | 9.12798 | 9.12798 | 0.0347443 | 0.0347439 | Nivel 2 | 4.2 | Level : Nivel 2 | 3.6 | 4.05 | 5.5746 | End Elevation | End Elevation | 216.151 | 0 | 0.0127 | 0 | 0.0127 | 0
765824 | Nivel 2 | 6 | 9.11551 | 9.12798 | 9.12798 | 0.0347443 | 0.0347439 | Nivel 2 | 4.2 | Level : Nivel 2 | 3.6 | 4.05 | 5.5746 | End Elevation | End Elevation | 216.151 | 0 | 0.0127 | 0 | 0.0127 | 0
765852 | Nivel 2 | 7.2 | 11.0777 | 11.0902 | 11.0902 | 0.0422235 | 0.0422278 | Nivel 2 | 4.2 | Level : Nivel 2 | 3.6 | 4.05 | 6.7746 | End Elevation | End Elevation | 262.68 | 0 | 0.0127 | 0 | 0.0127 | -0.105
765930 | Nivel 2 | 7.2 | 11.0777 | 11.0902 | 11.0902 | 0.0422235 | 0.0422278 | Nivel 2 | 4.2 | Level : Nivel 2 | 3.6 | 4.05 | 6.7746 | End Elevation | End Elevation | 262.68 | 0 | 0.0127 | 0 | 0.0127 | 0.105
765937 | Nivel 2 | 7.2 | 11.0777 | 11.0902 | 11.0902 | 0.0422235 | 0.0422278 | Nivel 2 | 4.2 | Level : Nivel 2 | 3.6 | 4.05 | 6.7746 | End Elevation | End Elevation | 262.68 | 0 | 0.0127 | 0 | 0.0127 | 0
765946 | Nivel 2 | 7.2 | 11.0777 | 11.0902 | 11.0902 | 0.0422235 | 0.0422278 | Nivel 2 | 4.2 | Level : Nivel 2 | 3.6 | 4.05 | 6.7746 | End Elevation | End Elevation | 262.68 | 0 | 0.0127 | 0 | 0.0127 | -0.105
765999 | Nivel 2 | 3.6 | 5.19106 | 5.20353 | 5.20353 | 0.019786 | 0.0197881 | Nivel 2 | 4.2 | Level : Nivel 2 | 3.6 | 4.05 | 3.1746 | End Elevation | End Elevation | 123.093 | 0 | 0.0127 | 0 | 0.0127 | 0
766023 | Nivel 2 | 3.6 | 5.19106 | 5.20353 | 5.20353 | 0.019786 | 0.0197881 | Nivel 2 | 4.2 | Level : Nivel 2 | 3.6 | 4.05 | 3.1746 | End Elevation | End Elevation | 123.093 | 0 | 0.0127 | 0 | 0.0127 | 0
766033 | Nivel 2 | 3.6 | 5.19106 | 5.20353 | 5.20353 | 0.019786 | 0.0197881 | Nivel 2 | 4.2 | Level : Nivel 2 | 3.6 | 4.05 | 3.1746 | End Elevation | End Elevation | 123.093 | 0 | 0.0127 | 0 | 0.0127 | 0
766043 | Nivel 2 | 3.6 | 5.19106 | 5.20353 | 5.20353 | 0.019786 | 0.0197881 | Nivel 2 | 4.2 | Level : Nivel 2 | 3.6 | 4.05 | 3.1746 | End Elevation | End Elevation | 123.093 | 0 | 0.0127 | 0 | 0.0127 | -0.105
766226 | Nivel 2 | 8.55 | 13.2852 | 13.2977 | 13.2977 | 0.0506375 | 0.0506426 | Nivel 2 | 4.2 | Level : Nivel 2 | 3.6 | 4.05 | 8.1246 | End Elevation | End Elevation | 315.026 | 0 | 0.0127 | 0 | 0.0127 | 0.105
766334 | Nivel 2 | 4.05 | 5.9269 | 5.93936 | 5.93937 | 0.0225907 | 0.022593 | Nivel 2 | 4.2 | Level : Nivel 2 | 3.6 | 4.05 | 3.6246 | End Elevation | End Elevation | 140.541 | 0 | 0.0127 | 0 | 0.0127 | -0.105
766390 | Nivel 2 | 6 | 9.11551 | 9.12798 | 9.12798 | 0.0347443 | 0.0347439 | Nivel 2 | 4.2 | Level : Nivel 2 | 3.6 | 4.05 | 5.5746 | End Elevation | End Elevation | 216.151 | 0 | 0.0127 | 0 | 0.0127 | 0
766468 | Nivel 2 | 3.85 | 5.59986 | 5.61232 | 5.61233 | 0.0213442 | 0.0213464 | Nivel 2 | 4.2 | Level : Nivel 2 | 3.6 | 4.05 | 3.4246 | End Elevation | End Elevation | 132.786 | 0 | 0.0127 | 0 | 0.0127 | 0
766544 | Nivel 2 | 7.8 | 12.0588 | 12.0713 | 12.0713 | 0.045963 | 0.0459677 | Nivel 2 | 4.2 | Level : Nivel 2 | 3.6 | 4.05 | 7.3746 | End Elevation | End Elevation | 285.945 | 0 | 0.0127 | 0 | 0.0127 | 0
766554 | Nivel 2 | 7.8 | 12.0588 | 12.0713 | 12.0713 | 0.045963 | 0.0459677 | Nivel 2 | 4.2 | Level : Nivel 2 | 3.6 | 4.05 | 7.3746 | End Elevation | End Elevation | 285.945 | 0 | 0.0127 | 0 | 0.0127 | 0
766562 | Nivel 2 | 3.85 | 5.62063 | 5.63309 | 5.63309 | 0.0214234 | 0.0214231 | Nivel 2 | 4.2 | Level : Nivel 2 | 3.6 | 4.05 | 3.4373 | End Elevation | End Elevation | 133.279 | 0 | 0.0127 | 0 | 0 | -0.105
766642 | Nivel 2 | 7.2 | 11.0777 | 11.0902 | 11.0902 | 0.0422235 | 0.0422278 | Nivel 2 | 4.2 | Level : Nivel 2 | 3.6 | 4.05 | 6.7746 | End Elevation | End Elevation | 262.68 | 0 | 0.0127 | 0 | 0.0127 | 0.105
766644 | Nivel 2 | 7.2 | 11.0777 | 11.0902 | 11.0902 | 0.0422235 | 0.0422278 | Nivel 2 | 4.2 | Level : Nivel 2 | 3.6 | 4.05 | 6.7746 | End Elevation | End Elevation | 262.68 | 0 | 0.0127 | 0 | 0.0127 | 0.105
766654 | Nivel 2 | 7.2 | 11.0777 | 11.0902 | 11.0902 | 0.0422235 | 0.0422278 | Nivel 2 | 4.2 | Level : Nivel 2 | 3.6 | 4.05 | 6.7746 | End Elevation | End Elevation | 262.68 | 0 | 0.0127 | 0 | 0.0127 | 0
766656 | Nivel 2 | 7.2 | 11.0777 | 11.0902 | 11.0902 | 0.0422235 | 0.0422278 | Nivel 2 | 4.2 | Level : Nivel 2 | 3.6 | 4.05 | 6.7746 | End Elevation | End Elevation | 262.68 | 0 | 0.0127 | 0 | 0.0127 | 0
766666 | Nivel 2 | 7.2 | 11.0777 | 11.0902 | 11.0902 | 0.0422235 | 0.0422278 | Nivel 2 | 4.2 | Level : Nivel 2 | 3.6 | 4.05 | 6.7746 | End Elevation | End Elevation | 262.68 | 0 | 0.0127 | 0 | 0.0127 | -0.105
766668 | Nivel 2 | 7.2 | 11.0777 | 11.0902 | 11.0902 | 0.0422235 | 0.0422278 | Nivel 2 | 4.2 | Level : Nivel 2 | 3.6 | 4.05 | 6.7746 | End Elevation | End Elevation | 262.68 | 0 | 0.0127 | 0 | 0.0127 | -0.105
766717 | Nivel 2 | 4.8 | 7.15329 | 7.16575 | 7.16576 | 0.0272652 | 0.027268 | Nivel 2 | 4.2 | Level : Nivel 2 | 3.6 | 4.05 | 4.3746 | End Elevation | End Elevation | 169.622 | 0 | 0.0127 | 0 | 0.0127 | -0.105
766742 | Nivel 2 | 6 | 9.11551 | 9.12798 | 9.12798 | 0.0347443 | 0.0347439 | Nivel 2 | 4.2 | Level : Nivel 2 | 3.6 | 4.05 | 5.5746 | End Elevation | End Elevation | 216.151 | 0 | 0.0127 | 0 | 0.0127 | -0.105
766821 | Nivel 2 | 4.8 | 7.15329 | 7.16575 | 7.16576 | 0.0272652 | 0.027268 | Nivel 2 | 4.2 | Level : Nivel 2 | 3.6 | 4.05 | 4.3746 | End Elevation | End Elevation | 169.622 | 0 | 0.0127 | 0 | 0.0127 | 0
766823 | Nivel 2 | 6 | 9.11551 | 9.12798 | 9.12798 | 0.0347443 | 0.0347439 | Nivel 2 | 4.2 | Level : Nivel 2 | 3.6 | 4.05 | 5.5746 | End Elevation | End Elevation | 216.151 | 0 | 0.0127 | 0 | 0.0127 | 0
766834 | Nivel 2 | 4.8 | 7.15329 | 7.16575 | 7.16576 | 0.0272652 | 0.027268 | Nivel 2 | 4.2 | Level : Nivel 2 | 3.6 | 4.05 | 4.3746 | End Elevation | End Elevation | 169.622 | 0 | 0.0127 | 0 | 0.0127 | 0
766836 | Nivel 2 | 2.25 | 3.14708 | 3.15954 | 3.15955 | 0.0119953 | 0.0119965 | Nivel 2 | 4.2 | Level : Nivel 2 | 3.6 | 4.05 | 1.9246 | End Elevation | End Elevation | 74.625 | 0 | 0.0127 | 0 | 0.0127 | 0
766849 | Nivel 2 | 4.8 | 7.15329 | 7.16575 | 7.16576 | 0.0272652 | 0.027268 | Nivel 2 | 4.2 | Level : Nivel 2 | 3.6 | 4.05 | 4.3746 | End Elevation | End Elevation | 169.622 | 0 | 0.0127 | 0 | 0.0127 | 0
766851 | Nivel 2 | 6 | 9.11551 | 9.12798 | 9.12798 | 0.0347443 | 0.0347439 | Nivel 2 | 4.2 | Level : Nivel 2 | 3.6 | 4.05 | 5.5746 | End Elevation | End Elevation | 216.151 | 0 | 0.0127 | 0 | 0.0127 | 0
766862 | Nivel 2 | 4.8 | 7.15329 | 7.16575 | 7.16576 | 0.0272652 | 0.027268 | Nivel 2 | 4.2 | Level : Nivel 2 | 3.6 | 4.05 | 4.3746 | End Elevation | End Elevation | 169.622 | 0 | 0.0127 | 0 | 0.0127 | 0
766864 | Nivel 2 | 6 | 9.11551 | 9.12798 | 9.12798 | 0.0347443 | 0.0347439 | Nivel 2 | 4.2 | Level : Nivel 2 | 3.6 | 4.05 | 5.5746 | End Elevation | End Elevation | 216.151 | 0 | 0.0127 | 0 | 0.0127 | 0
766875 | Nivel 2 | 4.8 | 7.15329 | 7.16575 | 7.16576 | 0.0272652 | 0.027268 | Nivel 2 | 4.2 | Level : Nivel 2 | 3.6 | 4.05 | 4.3746 | End Elevation | End Elevation | 169.622 | 0 | 0.0127 | 0 | 0.0127 | 0
766877 | Nivel 2 | 6 | 9.11551 | 9.12798 | 9.12798 | 0.0347443 | 0.0347439 | Nivel 2 | 4.2 | Level : Nivel 2 | 3.6 | 4.05 | 5.5746 | End Elevation | End Elevation | 216.151 | 0 | 0.0127 | 0 | 0.0127 | 0
766888 | Nivel 2 | 4.8 | 7.15329 | 7.16575 | 7.16576 | 0.0272652 | 0.027268 | Nivel 2 | 4.2 | Level : Nivel 2 | 3.6 | 4.05 | 4.3746 | End Elevation | End Elevation | 169.622 | 0 | 0.0127 | 0 | 0.0127 | 0
766890 | Nivel 2 | 6 | 9.11551 | 9.12798 | 9.12798 | 0.0347443 | 0.0347439 | Nivel 2 | 4.2 | Level : Nivel 2 | 3.6 | 4.05 | 5.5746 | End Elevation | End Elevation | 216.151 | 0 | 0.0127 | 0 | 0.0127 | 0
767591 | Nivel 3 | 6 | 9.11551 | 9.12798 | 9.12798 | 0.0347443 | 0.0347439 | Nivel 3 | 8.45 | Level : Nivel 3 | 7.85 | 8.3 | 5.5746 | End Elevation | End Elevation | 216.151 | 0 | 0.0127 | 0 | 0.0127 | 0
767593 | Nivel 3 | 6 | 9.11551 | 9.12798 | 9.12798 | 0.0347443 | 0.0347439 | Nivel 3 | 8.45 | Level : Nivel 3 | 7.85 | 8.3 | 5.5746 | End Elevation | End Elevation | 216.151 | 0 | 0.0127 | 0 | 0.0127 | 0
767595 | Nivel 3 | 6 | 9.11551 | 9.12798 | 9.12798 | 0.0347443 | 0.0347439 | Nivel 3 | 8.45 | Level : Nivel 3 | 7.85 | 8.3 | 5.5746 | End Elevation | End Elevation | 216.151 | 0 | 0.0127 | 0 | 0.0127 | 0
767597 | Nivel 3 | 3.75 | 5.59986 | 5.61232 | 5.61233 | 0.0213442 | 0.0213464 | Nivel 3 | 8.45 | Level : Nivel 3 | 7.85 | 8.3 | 3.4246 | End Elevation | End Elevation | 132.786 | 0 | 0.0127 | 0 | 0.0127 | 0
767599 | Nivel 3 | 6 | 9.11551 | 9.12798 | 9.12798 | 0.0347443 | 0.0347439 | Nivel 3 | 8.45 | Level : Nivel 3 | 7.85 | 8.3 | 5.5746 | End Elevation | End Elevation | 216.151 | 0 | 0.0127 | 0 | 0.0127 | 0
767601 | Nivel 3 | 6 | 9.11551 | 9.12798 | 9.12798 | 0.0347443 | 0.0347439 | Nivel 3 | 8.45 | Level : Nivel 3 | 7.85 | 8.3 | 5.5746 | End Elevation | End Elevation | 216.151 | 0 | 0.0127 | 0 | 0.0127 | -0.105
767603 | Nivel 3 | 4.8 | 7.15329 | 7.16575 | 7.16576 | 0.0272652 | 0.027268 | Nivel 3 | 8.45 | Level : Nivel 3 | 7.85 | 8.3 | 4.3746 | End Elevation | End Elevation | 169.622 | 0 | 0.0127 | 0 | 0.0127 | 0
767605 | Nivel 3 | 4.8 | 7.15329 | 7.16575 | 7.16576 | 0.0272652 | 0.027268 | Nivel 3 | 8.45 | Level : Nivel 3 | 7.85 | 8.3 | 4.3746 | End Elevation | End Elevation | 169.622 | 0 | 0.0127 | 0 | 0.0127 | 0
767607 | Nivel 3 | 4.8 | 7.15329 | 7.16575 | 7.16576 | 0.0272652 | 0.027268 | Nivel 3 | 8.45 | Level : Nivel 3 | 7.85 | 8.3 | 4.3746 | End Elevation | End Elevation | 169.622 | 0 | 0.0127 | 0 | 0.0127 | 0
767609 | Nivel 3 | 4.8 | 7.15329 | 7.16575 | 7.16576 | 0.0272652 | 0.027268 | Nivel 3 | 8.45 | Level : Nivel 3 | 7.85 | 8.3 | 4.3746 | End Elevation | End Elevation | 169.622 | 0 | 0.0127 | 0 | 0.0127 | 0
767611 | Nivel 3 | 4.8 | 7.15329 | 7.16575 | 7.16576 | 0.0272652 | 0.027268 | Nivel 3 | 8.45 | Level : Nivel 3 | 7.85 | 8.3 | 4.3746 | End Elevation | End Elevation | 169.622 | 0 | 0.0127 | 0 | 0.0127 | 0
767613 | Nivel 3 | 4.8 | 7.15329 | 7.16575 | 7.16576 | 0.0272652 | 0.027268 | Nivel 3 | 8.45 | Level : Nivel 3 | 7.85 | 8.3 | 4.3746 | End Elevation | End Elevation | 169.622 | 0 | 0.0127 | 0 | 0.0127 | -0.105
767615 | Nivel 3 | 7.2 | 11.0777 | 11.0902 | 11.0902 | 0.0422235 | 0.0422278 | Nivel 3 | 8.45 | Level : Nivel 3 | 7.85 | 8.3 | 6.7746 | End Elevation | End Elevation | 262.68 | 0 | 0.0127 | 0 | 0.0127 | 0.105
767617 | Nivel 3 | 7.2 | 11.0777 | 11.0902 | 11.0902 | 0.0422235 | 0.0422278 | Nivel 3 | 8.45 | Level : Nivel 3 | 7.85 | 8.3 | 6.7746 | End Elevation | End Elevation | 262.68 | 0 | 0.0127 | 0 | 0.0127 | 0
767619 | Nivel 3 | 7.2 | 11.0777 | 11.0902 | 11.0902 | 0.0422235 | 0.0422278 | Nivel 3 | 8.45 | Level : Nivel 3 | 7.85 | 8.3 | 6.7746 | End Elevation | End Elevation | 262.68 | 0 | 0.0127 | 0 | 0.0127 | -0.105
767621 | Nivel 3 | 7.2 | 11.0777 | 11.0902 | 11.0902 | 0.0422235 | 0.0422278 | Nivel 3 | 8.45 | Level : Nivel 3 | 7.85 | 8.3 | 6.7746 | End Elevation | End Elevation | 262.68 | 0 | 0.0127 | 0 | 0.0127 | 0.105
767623 | Nivel 3 | 7.2 | 11.0777 | 11.0902 | 11.0902 | 0.0422235 | 0.0422278 | Nivel 3 | 8.45 | Level : Nivel 3 | 7.85 | 8.3 | 6.7746 | End Elevation | End Elevation | 262.68 | 0 | 0.0127 | 0 | 0.0127 | 0
767625 | Nivel 3 | 7.2 | 11.0777 | 11.0902 | 11.0902 | 0.0422235 | 0.0422278 | Nivel 3 | 8.45 | Level : Nivel 3 | 7.85 | 8.3 | 6.7746 | End Elevation | End Elevation | 262.68 | 0 | 0.0127 | 0 | 0.0127 | -0.105
767627 | Nivel 3 | 7.2 | 11.0777 | 11.0902 | 11.0902 | 0.0422235 | 0.0422278 | Nivel 3 | 8.45 | Level : Nivel 3 | 7.85 | 8.3 | 6.7746 | End Elevation | End Elevation | 262.68 | 0 | 0.0127 | 0 | 0.0127 | 0.105
767629 | Nivel 3 | 7.2 | 11.0777 | 11.0902 | 11.0902 | 0.0422235 | 0.0422278 | Nivel 3 | 8.45 | Level : Nivel 3 | 7.85 | 8.3 | 6.7746 | End Elevation | End Elevation | 262.68 | 0 | 0.0127 | 0 | 0.0127 | 0
767631 | Nivel 3 | 7.2 | 11.0777 | 11.0902 | 11.0902 | 0.0422235 | 0.0422278 | Nivel 3 | 8.45 | Level : Nivel 3 | 7.85 | 8.3 | 6.7746 | End Elevation | End Elevation | 262.68 | 0 | 0.0127 | 0 | 0.0127 | -0.105
767633 | Nivel 3 | 8.55 | 13.2852 | 13.2977 | 13.2977 | 0.0506375 | 0.0506426 | Nivel 3 | 8.45 | Level : Nivel 3 | 7.85 | 8.3 | 8.1246 | End Elevation | End Elevation | 315.026 | 0 | 0.0127 | 0 | 0.0127 | -0.105
767635 | Nivel 3 | 8.55 | 13.2852 | 13.2977 | 13.2977 | 0.0506375 | 0.0506426 | Nivel 3 | 8.45 | Level : Nivel 3 | 7.85 | 8.3 | 8.1246 | End Elevation | End Elevation | 315.026 | 0 | 0.0127 | 0 | 0.0127 | 0.105
767637 | Nivel 3 | 8.55 | 13.2852 | 13.2977 | 13.2977 | 0.0506375 | 0.0506426 | Nivel 3 | 8.45 | Level : Nivel 3 | 7.85 | 8.3 | 8.1246 | End Elevation | End Elevation | 315.026 | 0 | 0.0127 | 0 | 0.0127 | 0
767639 | Nivel 3 | 8.55 | 13.2852 | 13.2977 | 13.2977 | 0.0506375 | 0.0506426 | Nivel 3 | 8.45 | Level : Nivel 3 | 7.85 | 8.3 | 8.1246 | End Elevation | End Elevation | 315.026 | 0 | 0.0127 | 0 | 0.0127 | -0.105
767641 | Nivel 3 | 4.8 | 7.15329 | 7.16575 | 7.16576 | 0.0272652 | 0.027268 | Nivel 3 | 8.45 | Level : Nivel 3 | 7.85 | 8.3 | 4.3746 | End Elevation | End Elevation | 169.622 | 0 | 0.0127 | 0 | 0.0127 | 0
767643 | Nivel 3 | 4.8 | 7.15329 | 7.16575 | 7.16576 | 0.0272652 | 0.027268 | Nivel 3 | 8.45 | Level : Nivel 3 | 7.85 | 8.3 | 4.3746 | End Elevation | End Elevation | 169.622 | 0 | 0.0127 | 0 | 0.0127 | 0
767645 | Nivel 3 | 4.8 | 7.15329 | 7.16575 | 7.16576 | 0.0272652 | 0.027268 | Nivel 3 | 8.45 | Level : Nivel 3 | 7.85 | 8.3 | 4.3746 | End Elevation | End Elevation | 169.622 | 0 | 0.0127 | 0 | 0.0127 | 0
767647 | Nivel 3 | 4.8 | 7.15329 | 7.16575 | 7.16576 | 0.0272652 | 0.027268 | Nivel 3 | 8.45 | Level : Nivel 3 | 7.85 | 8.3 | 4.3746 | End Elevation | End Elevation | 169.622 | 0 | 0.0127 | 0 | 0.0127 | 0
767649 | Nivel 3 | 4.8 | 7.15329 | 7.16575 | 7.16576 | 0.0272652 | 0.027268 | Nivel 3 | 8.45 | Level : Nivel 3 | 7.85 | 8.3 | 4.3746 | End Elevation | End Elevation | 169.622 | 0 | 0.0127 | 0 | 0.0127 | 0
767651 | Nivel 3 | 4.8 | 7.15329 | 7.16575 | 7.16576 | 0.0272652 | 0.027268 | Nivel 3 | 8.45 | Level : Nivel 3 | 7.85 | 8.3 | 4.3746 | End Elevation | End Elevation | 169.622 | 0 | 0.0127 | 0 | 0.0127 | 0
767653 | Nivel 3 | 7.2 | 11.0777 | 11.0902 | 11.0902 | 0.0422235 | 0.0422278 | Nivel 3 | 8.45 | Level : Nivel 3 | 7.85 | 8.3 | 6.7746 | End Elevation | End Elevation | 262.68 | 0 | 0.0127 | 0 | 0.0127 | 0.105
767655 | Nivel 3 | 7.2 | 11.0777 | 11.0902 | 11.0902 | 0.0422235 | 0.0422278 | Nivel 3 | 8.45 | Level : Nivel 3 | 7.85 | 8.3 | 6.7746 | End Elevation | End Elevation | 262.68 | 0 | 0.0127 | 0 | 0.0127 | 0
767657 | Nivel 3 | 7.2 | 11.0777 | 11.0902 | 11.0902 | 0.0422235 | 0.0422278 | Nivel 3 | 8.45 | Level : Nivel 3 | 7.85 | 8.3 | 6.7746 | End Elevation | End Elevation | 262.68 | 0 | 0.0127 | 0 | 0.0127 | -0.105
767659 | Nivel 3 | 7.2 | 11.0777 | 11.0902 | 11.0902 | 0.0422235 | 0.0422278 | Nivel 3 | 8.45 | Level : Nivel 3 | 7.85 | 8.3 | 6.7746 | End Elevation | End Elevation | 262.68 | 0 | 0.0127 | 0 | 0.0127 | 0.105
767661 | Nivel 3 | 7.2 | 11.0777 | 11.0902 | 11.0902 | 0.0422235 | 0.0422278 | Nivel 3 | 8.45 | Level : Nivel 3 | 7.85 | 8.3 | 6.7746 | End Elevation | End Elevation | 262.68 | 0 | 0.0127 | 0 | 0.0127 | 0
767663 | Nivel 3 | 7.2 | 11.0777 | 11.0902 | 11.0902 | 0.0422235 | 0.0422278 | Nivel 3 | 8.45 | Level : Nivel 3 | 7.85 | 8.3 | 6.7746 | End Elevation | End Elevation | 262.68 | 0 | 0.0127 | 0 | 0.0127 | -0.105
767665 | Nivel 3 | 3.6 | 5.19106 | 5.20353 | 5.20353 | 0.019786 | 0.0197881 | Nivel 3 | 8.45 | Level : Nivel 3 | 7.85 | 8.3 | 3.1746 | End Elevation | End Elevation | 123.093 | 0 | 0.0127 | 0 | 0.0127 | 0.105
767667 | Nivel 3 | 3.6 | 5.19106 | 5.20353 | 5.20353 | 0.019786 | 0.0197881 | Nivel 3 | 8.45 | Level : Nivel 3 | 7.85 | 8.3 | 3.1746 | End Elevation | End Elevation | 123.093 | 0 | 0.0127 | 0 | 0.0127 | 0
767669 | Nivel 3 | 3.6 | 5.19106 | 5.20353 | 5.20353 | 0.019786 | 0.0197881 | Nivel 3 | 8.45 | Level : Nivel 3 | 7.85 | 8.3 | 3.1746 | End Elevation | End Elevation | 123.093 | 0 | 0.0127 | 0 | 0.0127 | 0
767671 | Nivel 3 | 3.6 | 5.19106 | 5.20353 | 5.20353 | 0.019786 | 0.0197881 | Nivel 3 | 8.45 | Level : Nivel 3 | 7.85 | 8.3 | 3.1746 | End Elevation | End Elevation | 123.093 | 0 | 0.0127 | 0 | 0.0127 | 0
767673 | Nivel 3 | 3.6 | 5.19106 | 5.20353 | 5.20353 | 0.019786 | 0.0197881 | Nivel 3 | 8.45 | Level : Nivel 3 | 7.85 | 8.3 | 3.1746 | End Elevation | End Elevation | 123.093 | 0 | 0.0127 | 0 | 0.0127 | 0
767675 | Nivel 3 | 6 | 9.11551 | 9.12798 | 9.12798 | 0.0347443 | 0.0347439 | Nivel 3 | 8.45 | Level : Nivel 3 | 7.85 | 8.3 | 5.5746 | End Elevation | End Elevation | 216.151 | 0 | 0.0127 | 0 | 0.0127 | 0.105
767677 | Nivel 3 | 6 | 9.11551 | 9.12798 | 9.12798 | 0.0347443 | 0.0347439 | Nivel 3 | 8.45 | Level : Nivel 3 | 7.85 | 8.3 | 5.5746 | End Elevation | End Elevation | 216.151 | 0 | 0.0127 | 0 | 0.0127 | 0
767679 | Nivel 3 | 6 | 9.11551 | 9.12798 | 9.12798 | 0.0347443 | 0.0347439 | Nivel 3 | 8.45 | Level : Nivel 3 | 7.85 | 8.3 | 5.5746 | End Elevation | End Elevation | 216.151 | 0 | 0.0127 | 0 | 0.0127 | 0
767681 | Nivel 3 | 6 | 9.11551 | 9.12798 | 9.12798 | 0.0347443 | 0.0347439 | Nivel 3 | 8.45 | Level : Nivel 3 | 7.85 | 8.3 | 5.5746 | End Elevation | End Elevation | 216.151 | 0 | 0.0127 | 0 | 0.0127 | 0
767683 | Nivel 3 | 6 | 9.11551 | 9.12798 | 9.12798 | 0.0347443 | 0.0347439 | Nivel 3 | 8.45 | Level : Nivel 3 | 7.85 | 8.3 | 5.5746 | End Elevation | End Elevation | 216.151 | 0 | 0.0127 | 0 | 0.0127 | 0
767685 | Nivel 3 | 7.2 | 11.0777 | 11.0902 | 11.0902 | 0.0422235 | 0.0422278 | Nivel 3 | 8.45 | Level : Nivel 3 | 7.85 | 8.3 | 6.7746 | End Elevation | End Elevation | 262.68 | 0 | 0.0127 | 0 | 0.0127 | 0.105
767687 | Nivel 3 | 7.2 | 11.0777 | 11.0902 | 11.0902 | 0.0422235 | 0.0422278 | Nivel 3 | 8.45 | Level : Nivel 3 | 7.85 | 8.3 | 6.7746 | End Elevation | End Elevation | 262.68 | 0 | 0.0127 | 0 | 0.0127 | 0
767689 | Nivel 3 | 7.2 | 11.0777 | 11.0902 | 11.0902 | 0.0422235 | 0.0422278 | Nivel 3 | 8.45 | Level : Nivel 3 | 7.85 | 8.3 | 6.7746 | End Elevation | End Elevation | 262.68 | 0 | 0.0127 | 0 | 0.0127 | 0.105
767691 | Nivel 3 | 7.2 | 11.0777 | 11.0902 | 11.0902 | 0.0422235 | 0.0422278 | Nivel 3 | 8.45 | Level : Nivel 3 | 7.85 | 8.3 | 6.7746 | End Elevation | End Elevation | 262.68 | 0 | 0.0127 | 0 | 0.0127 | 0
767693 | Nivel 3 | 3.6429 | 5.47379 | 5.48625 | 5.48625 | 0.0208637 | 0.0208634 | Nivel 3 | 8.45 | Level : Nivel 3 | 7.85 | 8.3 | 3.3475 | End Elevation |  | 129.797 | 0 | 0.0127 | 0 | 0.0127 | 0
767695 | Nivel 3 | 6 | 9.11551 | 9.12798 | 9.12798 | 0.0347443 | 0.0347439 | Nivel 3 | 8.45 | Level : Nivel 3 | 7.85 | 8.3 | 5.5746 | End Elevation | End Elevation | 216.151 | 0 | 0.0127 | 0 | 0.0127 | 0
767697 | Nivel 3 | 7.2 | 11.0777 | 11.0902 | 11.0902 | 0.0422235 | 0.0422278 | Nivel 3 | 8.45 | Level : Nivel 3 | 7.85 | 8.3 | 6.7746 | End Elevation | End Elevation | 262.68 | 0 | 0.0127 | 0 | 0.0127 | -0.105
767699 | Nivel 3 | 6 | 9.11551 | 9.12798 | 9.12798 | 0.0347443 | 0.0347439 | Nivel 3 | 8.45 | Level : Nivel 3 | 7.85 | 8.3 | 5.5746 | End Elevation | End Elevation | 216.151 | 0 | 0.0127 | 0 | 0.0127 | 0
767701 | Nivel 3 | 7.2 | 11.0777 | 11.0902 | 11.0902 | 0.0422235 | 0.0422278 | Nivel 3 | 8.45 | Level : Nivel 3 | 7.85 | 8.3 | 6.7746 | End Elevation | End Elevation | 262.68 | 0 | 0.0127 | 0 | 0.0127 | -0.105
767703 | Nivel 3 | 6 | 9.11551 | 9.12798 | 9.12798 | 0.0347443 | 0.0347439 | Nivel 3 | 8.45 | Level : Nivel 3 | 7.85 | 8.3 | 5.5746 | End Elevation | End Elevation | 216.151 | 0 | 0.0127 | 0 | 0.0127 | 0
767705 | Nivel 3 | 6 | 9.11551 | 9.12798 | 9.12798 | 0.0347443 | 0.0347439 | Nivel 3 | 8.45 | Level : Nivel 3 | 7.85 | 8.3 | 5.5746 | End Elevation | End Elevation | 216.151 | 0 | 0.0127 | 0 | 0.0127 | 0
767707 | Nivel 3 | 3.6 | 5.19106 | 5.20353 | 5.20353 | 0.019786 | 0.0197881 | Nivel 3 | 8.45 | Level : Nivel 3 | 7.85 | 8.3 | 3.1746 | End Elevation | End Elevation | 123.093 | 0 | 0.0127 | 0 | 0.0127 | 0
767709 | Nivel 3 | 3.6 | 5.19106 | 5.20353 | 5.20353 | 0.019786 | 0.0197881 | Nivel 3 | 8.45 | Level : Nivel 3 | 7.85 | 8.3 | 3.1746 | End Elevation | End Elevation | 123.093 | 0 | 0.0127 | 0 | 0.0127 | 0
767711 | Nivel 3 | 3.6 | 5.19106 | 5.20353 | 5.20353 | 0.019786 | 0.0197881 | Nivel 3 | 8.45 | Level : Nivel 3 | 7.85 | 8.3 | 3.1746 | End Elevation | End Elevation | 123.093 | 0 | 0.0127 | 0 | 0.0127 | 0
767713 | Nivel 3 | 3.6 | 5.19106 | 5.20353 | 5.20353 | 0.019786 | 0.0197881 | Nivel 3 | 8.45 | Level : Nivel 3 | 7.85 | 8.3 | 3.1746 | End Elevation | End Elevation | 123.093 | 0 | 0.0127 | 0 | 0.0127 | -0.105
767717 | Nivel 3 | 6 | 9.11551 | 9.12798 | 9.12798 | 0.0347443 | 0.0347439 | Nivel 3 | 8.45 | Level : Nivel 3 | 7.85 | 8.3 | 5.5746 | End Elevation | End Elevation | 216.151 | 0 | 0.0127 | 0 | 0.0127 | 0
767719 | Nivel 3 | 6 | 9.11551 | 9.12798 | 9.12798 | 0.0347443 | 0.0347439 | Nivel 3 | 8.45 | Level : Nivel 3 | 7.85 | 8.3 | 5.5746 | End Elevation | End Elevation | 216.151 | 0 | 0.0127 | 0 | 0.0127 | 0
767721 | Nivel 3 | 6 | 9.11551 | 9.12798 | 9.12798 | 0.0347443 | 0.0347439 | Nivel 3 | 8.45 | Level : Nivel 3 | 7.85 | 8.3 | 5.5746 | End Elevation | End Elevation | 216.151 | 0 | 0.0127 | 0 | 0.0127 | -0.105
767723 | Nivel 3 | 8.55 | 13.2852 | 13.2977 | 13.2977 | 0.0506375 | 0.0506426 | Nivel 3 | 8.45 | Level : Nivel 3 | 7.85 | 8.3 | 8.1246 | End Elevation | End Elevation | 315.026 | 0 | 0.0127 | 0 | 0.0127 | -0.105
767725 | Nivel 3 | 8.55 | 13.2852 | 13.2977 | 13.2977 | 0.0506375 | 0.0506426 | Nivel 3 | 8.45 | Level : Nivel 3 | 7.85 | 8.3 | 8.1246 | End Elevation | End Elevation | 315.026 | 0 | 0.0127 | 0 | 0.0127 | 0.105
767727 | Nivel 3 | 8.55 | 13.2852 | 13.2977 | 13.2977 | 0.0506375 | 0.0506426 | Nivel 3 | 8.45 | Level : Nivel 3 | 7.85 | 8.3 | 8.1246 | End Elevation | End Elevation | 315.026 | 0 | 0.0127 | 0 | 0.0127 | 0
767729 | Nivel 3 | 8.55 | 13.2852 | 13.2977 | 13.2977 | 0.0506375 | 0.0506426 | Nivel 3 | 8.45 | Level : Nivel 3 | 7.85 | 8.3 | 8.1246 | End Elevation | End Elevation | 315.026 | 0 | 0.0127 | 0 | 0.0127 | 0
767731 | Nivel 3 | 8.55 | 13.2852 | 13.2977 | 13.2977 | 0.0506375 | 0.0506426 | Nivel 3 | 8.45 | Level : Nivel 3 | 7.85 | 8.3 | 8.1246 | End Elevation | End Elevation | 315.026 | 0 | 0.0127 | 0 | 0.0127 | -0.105
767733 | Nivel 3 | 6 | 9.11551 | 9.12798 | 9.12798 | 0.0347443 | 0.0347439 | Nivel 3 | 8.45 | Level : Nivel 3 | 7.85 | 8.3 | 5.5746 | End Elevation | End Elevation | 216.151 | 0 | 0.0127 | 0 | 0.0127 | 0
767743 | Nivel 3 | 7.2 | 11.0777 | 11.0902 | 11.0902 | 0.0422235 | 0.0422278 | Nivel 3 | 8.45 | Level : Nivel 3 | 7.85 | 8.3 | 6.7746 | End Elevation | End Elevation | 262.68 | 0 | 0.0127 | 0 | 0.0127 | 0.105
767745 | Nivel 3 | 7.2 | 11.0777 | 11.0902 | 11.0902 | 0.0422235 | 0.0422278 | Nivel 3 | 8.45 | Level : Nivel 3 | 7.85 | 8.3 | 6.7746 | End Elevation | End Elevation | 262.68 | 0 | 0.0127 | 0 | 0.0127 | 0.105
767747 | Nivel 3 | 7.2 | 11.0777 | 11.0902 | 11.0902 | 0.0422235 | 0.0422278 | Nivel 3 | 8.45 | Level : Nivel 3 | 7.85 | 8.3 | 6.7746 | End Elevation | End Elevation | 262.68 | 0 | 0.0127 | 0 | 0.0127 | 0
767749 | Nivel 3 | 7.2 | 11.0777 | 11.0902 | 11.0902 | 0.0422235 | 0.0422278 | Nivel 3 | 8.45 | Level : Nivel 3 | 7.85 | 8.3 | 6.7746 | End Elevation | End Elevation | 262.68 | 0 | 0.0127 | 0 | 0.0127 | 0
767751 | Nivel 3 | 7.2 | 11.0777 | 11.0902 | 11.0902 | 0.0422235 | 0.0422278 | Nivel 3 | 8.45 | Level : Nivel 3 | 7.85 | 8.3 | 6.7746 | End Elevation | End Elevation | 262.68 | 0 | 0.0127 | 0 | 0.0127 | -0.105
767753 | Nivel 3 | 7.2 | 11.0777 | 11.0902 | 11.0902 | 0.0422235 | 0.0422278 | Nivel 3 | 8.45 | Level : Nivel 3 | 7.85 | 8.3 | 6.7746 | End Elevation | End Elevation | 262.68 | 0 | 0.0127 | 0 | 0.0127 | -0.105
767755 | Nivel 3 | 4.8 | 7.15329 | 7.16575 | 7.16576 | 0.0272652 | 0.027268 | Nivel 3 | 8.45 | Level : Nivel 3 | 7.85 | 8.3 | 4.3746 | End Elevation | End Elevation | 169.622 | 0 | 0.0127 | 0 | 0.0127 | -0.105
767757 | Nivel 3 | 6 | 9.11551 | 9.12798 | 9.12798 | 0.0347443 | 0.0347439 | Nivel 3 | 8.45 | Level : Nivel 3 | 7.85 | 8.3 | 5.5746 | End Elevation | End Elevation | 216.151 | 0 | 0.0127 | 0 | 0.0127 | -0.105
767759 | Nivel 3 | 4.8 | 7.15329 | 7.16575 | 7.16576 | 0.0272652 | 0.027268 | Nivel 3 | 8.45 | Level : Nivel 3 | 7.85 | 8.3 | 4.3746 | End Elevation | End Elevation | 169.622 | 0 | 0.0127 | 0 | 0.0127 | 0
767761 | Nivel 3 | 6 | 9.11551 | 9.12798 | 9.12798 | 0.0347443 | 0.0347439 | Nivel 3 | 8.45 | Level : Nivel 3 | 7.85 | 8.3 | 5.5746 | End Elevation | End Elevation | 216.151 | 0 | 0.0127 | 0 | 0.0127 | 0
767763 | Nivel 3 | 4.8 | 7.15329 | 7.16575 | 7.16576 | 0.0272652 | 0.027268 | Nivel 3 | 8.45 | Level : Nivel 3 | 7.85 | 8.3 | 4.3746 | End Elevation | End Elevation | 169.622 | 0 | 0.0127 | 0 | 0.0127 | 0
767765 | Nivel 3 | 6 | 9.11551 | 9.12798 | 9.12798 | 0.0347443 | 0.0347439 | Nivel 3 | 8.45 | Level : Nivel 3 | 7.85 | 8.3 | 5.5746 | End Elevation | End Elevation | 216.151 | 0 | 0.0127 | 0 | 0.0127 | 0
767767 | Nivel 3 | 4.8 | 7.15329 | 7.16575 | 7.16576 | 0.0272652 | 0.027268 | Nivel 3 | 8.45 | Level : Nivel 3 | 7.85 | 8.3 | 4.3746 | End Elevation | End Elevation | 169.622 | 0 | 0.0127 | 0 | 0.0127 | 0
767769 | Nivel 3 | 2.25 | 3.14708 | 3.15954 | 3.15955 | 0.0119953 | 0.0119965 | Nivel 3 | 8.45 | Level : Nivel 3 | 7.85 | 8.3 | 1.9246 | End Elevation | End Elevation | 74.625 | 0 | 0.0127 | 0 | 0.0127 | 0
767771 | Nivel 3 | 4.8 | 7.15329 | 7.16575 | 7.16576 | 0.0272652 | 0.027268 | Nivel 3 | 8.45 | Level : Nivel 3 | 7.85 | 8.3 | 4.3746 | End Elevation | End Elevation | 169.622 | 0 | 0.0127 | 0 | 0.0127 | 0
767773 | Nivel 3 | 6 | 9.11551 | 9.12798 | 9.12798 | 0.0347443 | 0.0347439 | Nivel 3 | 8.45 | Level : Nivel 3 | 7.85 | 8.3 | 5.5746 | End Elevation | End Elevation | 216.151 | 0 | 0.0127 | 0 | 0.0127 | 0
767775 | Nivel 3 | 4.8 | 7.15329 | 7.16575 | 7.16576 | 0.0272652 | 0.027268 | Nivel 3 | 8.45 | Level : Nivel 3 | 7.85 | 8.3 | 4.3746 | End Elevation | End Elevation | 169.622 | 0 | 0.0127 | 0 | 0.0127 | 0
767777 | Nivel 3 | 6 | 9.11551 | 9.12798 | 9.12798 | 0.0347443 | 0.0347439 | Nivel 3 | 8.45 | Level : Nivel 3 | 7.85 | 8.3 | 5.5746 | End Elevation | End Elevation | 216.151 | 0 | 0.0127 | 0 | 0.0127 | 0
767779 | Nivel 3 | 4.8 | 7.15329 | 7.16575 | 7.16576 | 0.0272652 | 0.027268 | Nivel 3 | 8.45 | Level : Nivel 3 | 7.85 | 8.3 | 4.3746 | End Elevation | End Elevation | 169.622 | 0 | 0.0127 | 0 | 0.0127 | 0
767781 | Nivel 3 | 6 | 9.11551 | 9.12798 | 9.12798 | 0.0347443 | 0.0347439 | Nivel 3 | 8.45 | Level : Nivel 3 | 7.85 | 8.3 | 5.5746 | End Elevation | End Elevation | 216.151 | 0 | 0.0127 | 0 | 0.0127 | 0
782049 | Nivel 3 | 3.85 | 5.59986 | 5.61232 | 5.61233 | 0.0213442 | 0.0213464 | Nivel 3 | 8.45 | Level : Nivel 3 | 7.85 | 8.3 | 3.4246 | End Elevation | End Elevation | 132.786 | 0 | 0.0127 | 0 | 0.0127 | 0
782051 | Nivel 3 | 3.85 | 5.59986 | 5.61232 | 5.61233 | 0.0213442 | 0.0213464 | Nivel 3 | 8.45 | Level : Nivel 3 | 7.85 | 8.3 | 3.4246 | End Elevation | End Elevation | 132.786 | 0 | 0.0127 | 0 | 0.0127 | 0
782053 | Nivel 3 | 3.85 | 5.59986 | 5.61232 | 5.61233 | 0.0213442 | 0.0213464 | Nivel 3 | 8.45 | Level : Nivel 3 | 7.85 | 8.3 | 3.4246 | End Elevation | End Elevation | 132.786 | 0 | 0.0127 | 0 | 0.0127 | -0.105
782096 | Nivel 3 | 3.8 | 5.59986 | 5.61232 | 5.61232 | 0.0213442 | 0.0213439 | Nivel 3 | 8.45 | Level : Nivel 3 | 7.85 | 8.3 | 3.4246 | End Elevation | End Elevation | 132.786 | 0 | 0.0127 | 0 | 0.0127 | 0.105
782098 | Nivel 3 | 3.8 | 5.59986 | 5.61232 | 5.61232 | 0.0213442 | 0.0213439 | Nivel 3 | 8.45 | Level : Nivel 3 | 7.85 | 8.3 | 3.4246 | End Elevation | End Elevation | 132.786 | 0 | 0.0127 | 0 | 0.0127 | 0
782402 | Nivel 3 | 6 | 9.11551 | 9.12798 | 9.12798 | 0.0347443 | 0.0347439 | Nivel 3 | 8.45 | Level : Nivel 3 | 7.85 | 8.3 | 5.5746 | End Elevation | End Elevation | 216.151 | 0 | 0.0127 | 0 | 0.0127 | 0.105
782404 | Nivel 3 | 4.8 | 7.15329 | 7.16575 | 7.16576 | 0.0272652 | 0.027268 | Nivel 3 | 8.45 | Level : Nivel 3 | 7.85 | 8.3 | 4.3746 | End Elevation | End Elevation | 169.622 | 0 | 0.0127 | 0 | 0.0127 | 0.105
782406 | Nivel 3 | 8.445 | 13.2852 | 13.2977 | 13.2977 | 0.0506375 | 0.0506426 | Nivel 3 | 8.45 | Level : Nivel 3 | 7.85 | 8.3 | 8.1246 | End Elevation |  | 315.026 | 0 | 0.0127 | 0 | 0.0127 | 0.105
782408 | Nivel 3 | 4.8 | 7.15329 | 7.16575 | 7.16576 | 0.0272652 | 0.027268 | Nivel 3 | 8.45 | Level : Nivel 3 | 7.85 | 8.3 | 4.3746 | End Elevation | End Elevation | 169.622 | 0 | 0.0127 | 0 | 0.0127 | 0.105
782410 | Nivel 3 | 2.25 | 3.14708 | 3.15954 | 3.15955 | 0.0119953 | 0.0119965 | Nivel 3 | 8.45 | Level : Nivel 3 | 7.85 | 8.3 | 1.9246 | End Elevation | End Elevation | 74.625 | 0 | 0.0127 | 0 | 0.0127 | 0.105
782412 | Nivel 3 | 8.55 | 13.4569 | 13.4694 | 13.4694 | 0.0512919 | 0.0512971 | Nivel 3 | 8.45 | Level : Nivel 3 | 7.85 | 8.3 | 88.5827 |  | End Elevation | 319.097 | 0 | 0.0127 | 0 | 0.0127 | 0.105
782414 | Nivel 3 | 4.8 | 7.15329 | 7.16575 | 7.16576 | 0.0272652 | 0.027268 | Nivel 3 | 8.45 | Level : Nivel 3 | 7.85 | 8.3 | 4.3746 | End Elevation | End Elevation | 169.622 | 0 | 0.0127 | 0 | 0.0127 | 0
782416 | Nivel 3 | 6 | 9.11551 | 9.12798 | 9.12798 | 0.0347443 | 0.0347439 | Nivel 3 | 8.45 | Level : Nivel 3 | 7.85 | 8.3 | 5.5746 | End Elevation | End Elevation | 216.151 | 0 | 0.0127 | 0 | 0.0127 | 0
782486 | Nivel 3 | 7.2 | 11.0777 | 11.0902 | 11.0902 | 0.0422235 | 0.0422278 | Nivel 3 | 8.45 | Level : Nivel 3 | 7.85 | 8.3 | 6.7746 | End Elevation | End Elevation | 262.68 | 0 | 0.0127 | 0 | 0.0127 | 0.105
782488 | Nivel 3 | 7.2 | 11.0777 | 11.0902 | 11.0902 | 0.0422235 | 0.0422278 | Nivel 3 | 8.45 | Level : Nivel 3 | 7.85 | 8.3 | 6.7746 | End Elevation | End Elevation | 262.68 | 0 | 0.0127 | 0 | 0.0127 | 0
782490 | Nivel 3 | 7.2 | 11.0777 | 11.0902 | 11.0902 | 0.0422235 | 0.0422278 | Nivel 3 | 8.45 | Level : Nivel 3 | 7.85 | 8.3 | 6.7746 | End Elevation | End Elevation | 262.68 | 0 | 0.0127 | 0 | 0.0127 | 0
782492 | Nivel 3 | 7.2 | 11.0777 | 11.0902 | 11.0902 | 0.0422235 | 0.0422278 | Nivel 3 | 8.45 | Level : Nivel 3 | 7.85 | 8.3 | 6.7746 | End Elevation | End Elevation | 262.68 | 0 | 0.0127 | 0 | 0.0127 | 0
782494 | Nivel 3 | 7.2 | 11.0777 | 11.0902 | 11.0902 | 0.0422235 | 0.0422278 | Nivel 3 | 8.45 | Level : Nivel 3 | 7.85 | 8.3 | 6.7746 | End Elevation | End Elevation | 262.68 | 0 | 0.0127 | 0 | 0.0127 | 0
782496 | Nivel 3 | 7.2 | 11.0777 | 11.0902 | 11.0902 | 0.0422235 | 0.0422278 | Nivel 3 | 8.45 | Level : Nivel 3 | 7.85 | 8.3 | 6.7746 | End Elevation | End Elevation | 262.68 | 0 | 0.0127 | 0 | 0.0127 | 0
782498 | Nivel 3 | 7.2 | 11.0777 | 11.0902 | 11.0902 | 0.0422235 | 0.0422278 | Nivel 3 | 8.45 | Level : Nivel 3 | 7.85 | 8.3 | 6.7746 | End Elevation | End Elevation | 262.68 | 0 | 0.0127 | 0 | 0.0127 | 0
782500 | Nivel 3 | 7.2 | 11.0777 | 11.0902 | 11.0902 | 0.0422235 | 0.0422278 | Nivel 3 | 8.45 | Level : Nivel 3 | 7.85 | 8.3 | 6.7746 | End Elevation | End Elevation | 262.68 | 0 | 0.0127 | 0 | 0.0127 | 0
782502 | Nivel 3 | 7.2 | 11.0777 | 11.0902 | 11.0902 | 0.0422235 | 0.0422278 | Nivel 3 | 8.45 | Level : Nivel 3 | 7.85 | 8.3 | 6.7746 | End Elevation | End Elevation | 262.68 | 0 | 0.0127 | 0 | 0.0127 | -0.105
782529 | Nivel 3 | 3.2999 | 4.70034 | 4.71281 | 4.71281 | 0.0179156 | 0.0179175 | Nivel 3 | 8.45 | Level : Nivel 3 | 7.85 | 8.3 | 2.8745 | End Elevation | End Elevation | 111.457 | 0 | 0.0127 | 0 | 0.0127 | 0.105
782531 | Nivel 3 | 3.2999 | 4.70034 | 4.71281 | 4.71281 | 0.0179156 | 0.0179175 | Nivel 3 | 8.45 | Level : Nivel 3 | 7.85 | 8.3 | 2.8745 | End Elevation | End Elevation | 111.457 | 0 | 0.0127 | 0 | 0.0127 | 0
782533 | Nivel 3 | 3.2999 | 4.70034 | 4.71281 | 4.71281 | 0.0179156 | 0.0179175 | Nivel 3 | 8.45 | Level : Nivel 3 | 7.85 | 8.3 | 2.8745 | End Elevation | End Elevation | 111.457 | 0 | 0.0127 | 0 | 0.0127 | -0.105
782598 | Nivel 3 | 4.8 | 7.15329 | 7.16575 | 7.16576 | 0.0272652 | 0.027268 | Nivel 3 | 8.45 | Level : Nivel 3 | 7.85 | 8.3 | 4.3746 | End Elevation | End Elevation | 169.622 | 0 | 0.0127 | 0 | 0.0127 | 0.105
782600 | Nivel 3 | 6 | 9.11551 | 9.12798 | 9.12798 | 0.0347443 | 0.0347439 | Nivel 3 | 8.45 | Level : Nivel 3 | 7.85 | 8.3 | 5.5746 | End Elevation | End Elevation | 216.151 | 0 | 0.0127 | 0 | 0.0127 | 0.105
783903 | Nivel 2 | 6 | 9.11551 | 9.12798 | 9.12798 | 0.0347443 | 0.0347439 | Nivel 2 | 4.2 | Level : Nivel 2 | 3.6 | 4.05 | 5.5746 | End Elevation | End Elevation | 216.151 | 0 | 0.0127 | 0 | 0.0127 | 0
783905 | Nivel 2 | 4.8 | 7.15329 | 7.16575 | 7.16576 | 0.0272652 | 0.027268 | Nivel 2 | 4.2 | Level : Nivel 2 | 3.6 | 4.05 | 4.3746 | End Elevation | End Elevation | 169.622 | 0 | 0.0127 | 0 | 0.0127 | 0
783909 | Nivel 2 | 4.8 | 7.15329 | 7.16575 | 7.16576 | 0.0272652 | 0.027268 | Nivel 2 | 4.2 | Level : Nivel 2 | 3.6 | 4.05 | 4.3746 | End Elevation | End Elevation | 169.622 | 0 | 0.0127 | 0 | 0.0127 | 0
783911 | Nivel 2 | 6 | 9.11551 | 9.12798 | 9.12798 | 0.0347443 | 0.0347439 | Nivel 2 | 4.2 | Level : Nivel 2 | 3.6 | 4.05 | 5.5746 | End Elevation | End Elevation | 216.151 | 0 | 0.0127 | 0 | 0.0127 | 0.105
783913 | Nivel 2 | 6 | 9.11551 | 9.12798 | 9.12798 | 0.0347443 | 0.0347439 | Nivel 2 | 4.2 | Level : Nivel 2 | 3.6 | 4.05 | 5.5746 | End Elevation | End Elevation | 216.151 | 0 | 0.0127 | 0 | 0.0127 | 0
783915 | Nivel 2 | 6 | 9.11551 | 9.12798 | 9.12798 | 0.0347443 | 0.0347439 | Nivel 2 | 4.2 | Level : Nivel 2 | 3.6 | 4.05 | 5.5746 | End Elevation | End Elevation | 216.151 | 0 | 0.0127 | 0 | 0.0127 | 0
783917 | Nivel 2 | 6 | 9.11551 | 9.12798 | 9.12798 | 0.0347443 | 0.0347439 | Nivel 2 | 4.2 | Level : Nivel 2 | 3.6 | 4.05 | 5.5746 | End Elevation | End Elevation | 216.151 | 0 | 0.0127 | 0 | 0.0127 | 0
783919 | Nivel 2 | 6 | 9.11551 | 9.12798 | 9.12798 | 0.0347443 | 0.0347439 | Nivel 2 | 4.2 | Level : Nivel 2 | 3.6 | 4.05 | 5.5746 | End Elevation | End Elevation | 216.151 | 0 | 0.0127 | 0 | 0.0127 | 0
783921 | Nivel 2 | 6 | 9.11551 | 9.12798 | 9.12798 | 0.0347443 | 0.0347439 | Nivel 2 | 4.2 | Level : Nivel 2 | 3.6 | 4.05 | 5.5746 | End Elevation | End Elevation | 216.151 | 0 | 0.0127 | 0 | 0.0127 | 0
783923 | Nivel 2 | 6 | 9.11551 | 9.12798 | 9.12798 | 0.0347443 | 0.0347439 | Nivel 2 | 4.2 | Level : Nivel 2 | 3.6 | 4.05 | 5.5746 | End Elevation | End Elevation | 216.151 | 0 | 0.0127 | 0 | 0.0127 | 0
783925 | Nivel 2 | 6 | 9.11551 | 9.12798 | 9.12798 | 0.0347443 | 0.0347439 | Nivel 2 | 4.2 | Level : Nivel 2 | 3.6 | 4.05 | 5.5746 | End Elevation | End Elevation | 216.151 | 0 | 0.0127 | 0 | 0.0127 | 0
783927 | Nivel 2 | 6 | 9.11551 | 9.12798 | 9.12798 | 0.0347443 | 0.0347439 | Nivel 2 | 4.2 | Level : Nivel 2 | 3.6 | 4.05 | 5.5746 | End Elevation | End Elevation | 216.151 | 0 | 0.0127 | 0 | 0.0127 | 0
783929 | Nivel 2 | 6 | 9.11551 | 9.12798 | 9.12798 | 0.0347443 | 0.0347439 | Nivel 2 | 4.2 | Level : Nivel 2 | 3.6 | 4.05 | 5.5746 | End Elevation | End Elevation | 216.151 | 0 | 0.0127 | 0 | 0.0127 | -0.105
783933 | Nivel 2 | 4.8 | 7.15329 | 7.16575 | 7.16576 | 0.0272652 | 0.027268 | Nivel 2 | 4.2 | Level : Nivel 2 | 3.6 | 4.05 | 4.3746 | End Elevation | End Elevation | 169.622 | 0 | 0.0127 | 0 | 0.0127 | 0
783935 | Nivel 2 | 6 | 9.11551 | 9.12798 | 9.12798 | 0.0347443 | 0.0347439 | Nivel 2 | 4.2 | Level : Nivel 2 | 3.6 | 4.05 | 5.5746 | End Elevation | End Elevation | 216.151 | 0 | 0.0127 | 0 | 0.0127 | 0
784390 | Nivel 2 | 3.85 | 5.59986 | 5.61232 | 5.61233 | 0.0213442 | 0.0213464 | Nivel 2 | 4.2 | Level : Nivel 2 | 3.6 | 4.05 | 3.4246 | End Elevation | End Elevation | 132.786 | 0 | 0.0127 | 0 | 0.0127 | 0.105
784467 | Nivel 2 | 4.8 | 7.15329 | 7.16575 | 7.16576 | 0.0272652 | 0.027268 | Nivel 2 | 4.2 | Level : Nivel 2 | 3.6 | 4.05 | 4.3746 | End Elevation | End Elevation | 169.622 | 0 | 0.0127 | 0 | 0.0127 | -0.105
784469 | Nivel 2 | 6 | 9.11551 | 9.12798 | 9.12798 | 0.0347443 | 0.0347439 | Nivel 2 | 4.2 | Level : Nivel 2 | 3.6 | 4.05 | 5.5746 | End Elevation | End Elevation | 216.151 | 0 | 0.0127 | 0 | 0.0127 | -0.105
785027 | Nivel 2 | 8.45 | 13.2934 | 13.3059 | 13.3059 | 0.0506686 | 0.050668 | Nivel 2 | 4.2 | Level : Nivel 2 | 3.6 | 4.05 | 8.1296 | End Elevation |  | 315.219 | 0 | 0.0127 | 0 | 0.0127 | 0
785136 | Nivel 2 | 8.45 | 13.2934 | 13.3059 | 13.3059 | 0.0506686 | 0.050668 | Nivel 2 | 4.2 | Level : Nivel 2 | 3.6 | 4.05 | 8.1296 |  | End Elevation | 315.219 | 0 | 0.0127 | 0 | 0.0127 | 0
790310 | Nivel 2 | 8.45 | 13.2934 | 13.3059 | 13.3059 | 0.0506686 | 0.050668 | Nivel 2 | 4.2 | Level : Nivel 2 | 3.6 | 4.05 | 8.1296 | End Elevation |  | 315.219 | 0 | 0.0127 | 0 | 0.0127 | 0.105
790312 | Nivel 2 | 8.45 | 13.2934 | 13.3059 | 13.3059 | 0.0506686 | 0.050668 | Nivel 2 | 4.2 | Level : Nivel 2 | 3.6 | 4.05 | 8.1296 |  | End Elevation | 315.219 | 0 | 0.0127 | 0 | 0.0127 | 0.105
792814 | Nivel 3 | 4.8 | 7.15329 | 7.16575 | 7.16576 | 0.0272652 | 0.027268 | Nivel 3 | 8.45 | Level : Nivel 3 | 7.85 | 8.3 | 4.3746 | End Elevation | End Elevation | 169.622 | 0 | 0.0127 | 0 | 0.0127 | -0.105
792816 | Nivel 3 | 6 | 9.11551 | 9.12798 | 9.12798 | 0.0347443 | 0.0347439 | Nivel 3 | 8.45 | Level : Nivel 3 | 7.85 | 8.3 | 5.5746 | End Elevation | End Elevation | 216.151 | 0 | 0.0127 | 0 | 0.0127 | -0.105
792916 | Nivel 3 | 6 | 9.11551 | 9.12798 | 9.12798 | 0.0347443 | 0.0347439 | Nivel 3 | 8.45 | Level : Nivel 3 | 7.85 | 8.3 | 5.5746 | End Elevation | End Elevation | 216.151 | 0 | 0.0127 | 0 | 0.0127 | 0
792993 | Nivel 3 | 3.85 | 5.59986 | 5.61232 | 5.61233 | 0.0213442 | 0.0213464 | Nivel 3 | 8.45 | Level : Nivel 3 | 7.85 | 8.3 | 3.4246 | End Elevation | End Elevation | 132.786 | 0 | 0.0127 | 0 | 0.0127 | 0
793970 | Nivel 2 | 4.05 | 5.9269 | 5.93936 | 5.93937 | 0.0225907 | 0.022593 | Nivel 2 | 4.2 | Level : Nivel 2 | 3.6 | 4.05 | 3.6246 | End Elevation | End Elevation | 140.541 | 0 | 0.0127 | 0 | 0.0127 | 0
793972 | Nivel 2 | 4.8 | 7.15329 | 7.16575 | 7.16576 | 0.0272652 | 0.027268 | Nivel 2 | 4.2 | Level : Nivel 2 | 3.6 | 4.05 | 4.3746 | End Elevation | End Elevation | 169.622 | 0 | 0.0127 | 0 | 0.0127 | 0
793974 | Nivel 2 | 6 | 9.11551 | 9.12798 | 9.12798 | 0.0347443 | 0.0347439 | Nivel 2 | 4.2 | Level : Nivel 2 | 3.6 | 4.05 | 5.5746 | End Elevation | End Elevation | 216.151 | 0 | 0.0127 | 0 | 0.0127 | 0
794034 | Nivel 2 | 3.2999 | 4.70034 | 4.71281 | 4.71281 | 0.0179156 | 0.0179175 | Nivel 2 | 4.2 | Level : Nivel 2 | 3.6 | 4.05 | 2.8745 | End Elevation | End Elevation | 111.457 | 0 | 0.0127 | 0 | 0.0127 | 0.105
794036 | Nivel 2 | 3.2999 | 4.70034 | 4.71281 | 4.71281 | 0.0179156 | 0.0179175 | Nivel 2 | 4.2 | Level : Nivel 2 | 3.6 | 4.05 | 2.8745 | End Elevation | End Elevation | 111.457 | 0 | 0.0127 | 0 | 0.0127 | 0
794038 | Nivel 2 | 3.2999 | 4.70034 | 4.71281 | 4.71281 | 0.0179156 | 0.0179175 | Nivel 2 | 4.2 | Level : Nivel 2 | 3.6 | 4.05 | 2.8745 | End Elevation | End Elevation | 111.457 | 0 | 0.0127 | 0 | 0.0127 | -0.105
794139 | Nivel 2 | 4.8 | 7.15329 | 7.16575 | 7.16576 | 0.0272652 | 0.027268 | Nivel 2 | 4.2 | Level : Nivel 2 | 3.6 | 4.05 | 4.3746 | End Elevation | End Elevation | 169.622 | 0 | 0.0127 | 0 | 0.0127 | 0.105
794141 | Nivel 2 | 6 | 9.11551 | 9.12798 | 9.12798 | 0.0347443 | 0.0347439 | Nivel 2 | 4.2 | Level : Nivel 2 | 3.6 | 4.05 | 5.5746 | End Elevation | End Elevation | 216.151 | 0 | 0.0127 | 0 | 0.0127 | 0.105
803641 | Nivel 2 | 8.55 | 13.2852 | 13.2977 | 13.2977 | 0.0506375 | 0.0506426 | Nivel 2 | 4.2 | Level : Nivel 2 | 3.6 | 4.05 | 8.1246 | End Elevation | End Elevation | 315.026 | 0 | 0.0127 | 0 | 0.0127 | -0.105
803700 | Nivel 2 | 2.3 | 3.40053 | 3.413 | 3.413 | 0.0129613 | 0.0129612 | Nivel 2 | 4.2 | Level : Nivel 2 | 3.6 | 4.05 | 2.0796 | End Elevation | End Elevation | 80.635 | 0 | 0.0127 | 0 | 0.0127 | 0
803766 | Nivel 2 | 3.6 | 5.19106 | 5.20353 | 5.20353 | 0.019786 | 0.0197881 | Nivel 2 | 4.2 | Level : Nivel 2 | 3.6 | 4.05 | 3.1746 | End Elevation | End Elevation | 123.093 | 0 | 0.0127 | 0 | 0.0127 | 0
803768 | Nivel 2 | 6 | 9.11551 | 9.12798 | 9.12798 | 0.0347443 | 0.0347439 | Nivel 2 | 4.2 | Level : Nivel 2 | 3.6 | 4.05 | 5.5746 | End Elevation | End Elevation | 216.151 | 0 | 0.0127 | 0 | 0.0127 | 0
803834 | Nivel 2 | 3.6 | 5.19106 | 5.20353 | 5.20353 | 0.019786 | 0.0197881 | Nivel 2 | 4.2 | Level : Nivel 2 | 3.6 | 4.05 | 3.1746 | End Elevation | End Elevation | 123.093 | 0 | 0.0127 | 0 | 0.0127 | 0
803836 | Nivel 2 | 6 | 9.11551 | 9.12798 | 9.12798 | 0.0347443 | 0.0347439 | Nivel 2 | 4.2 | Level : Nivel 2 | 3.6 | 4.05 | 5.5746 | End Elevation | End Elevation | 216.151 | 0 | 0.0127 | 0 | 0.0127 | 0
803887 | Nivel 2 | 3.85 | 5.59986 | 5.61232 | 5.61233 | 0.0213442 | 0.0213464 | Nivel 2 | 4.2 | Level : Nivel 2 | 3.6 | 4.05 | 3.4246 | End Elevation | End Elevation | 132.786 | 0 | 0.0127 | 0 | 0.0127 | 0
803947 | Nivel 2 | 3.85 | 5.76338 | 5.77584 | 5.77584 | 0.0219675 | 0.0219672 | Nivel 2 | 4.2 | Level : Nivel 2 | 3.6 | 4.05 | 3.5246 | End Elevation | End Elevation | 136.664 | 0 | 0.0127 | 0 | 0.0127 | 0.105
804075 | Nivel 2 | 2.3 | 3.40053 | 3.413 | 3.413 | 0.0129613 | 0.0129612 | Nivel 2 | 4.2 | Level : Nivel 2 | 3.6 | 4.05 | 2.0796 | End Elevation | End Elevation | 80.635 | 0 | 0.0127 | 0 | 0.0127 | 0
804143 | Nivel 2 | 8.55 | 13.2852 | 13.2977 | 13.2977 | 0.0506375 | 0.0506426 | Nivel 2 | 4.2 | Level : Nivel 2 | 3.6 | 4.05 | 8.1246 | End Elevation | End Elevation | 315.026 | 0 | 0.0127 | 0 | 0.0127 | -0.105
804212 | Nivel 3 | 3.6 | 5.19106 | 5.20353 | 5.20353 | 0.019786 | 0.0197881 | Nivel 3 | 8.45 | Level : Nivel 3 | 7.85 | 8.3 | 3.1746 | End Elevation | End Elevation | 123.093 | 0 | 0.0127 | 0 | 0.0127 | 0
804214 | Nivel 3 | 6 | 9.11551 | 9.12798 | 9.12798 | 0.0347443 | 0.0347439 | Nivel 3 | 8.45 | Level : Nivel 3 | 7.85 | 8.3 | 5.5746 | End Elevation | End Elevation | 216.151 | 0 | 0.0127 | 0 | 0.0127 | 0
804229 | Nivel 3 | 3.6 | 5.19106 | 5.20353 | 5.20353 | 0.019786 | 0.0197881 | Nivel 3 | 8.45 | Level : Nivel 3 | 7.85 | 8.3 | 3.1746 | End Elevation | End Elevation | 123.093 | 0 | 0.0127 | 0 | 0.0127 | 0
804231 | Nivel 3 | 6 | 9.11551 | 9.12798 | 9.12798 | 0.0347443 | 0.0347439 | Nivel 3 | 8.45 | Level : Nivel 3 | 7.85 | 8.3 | 5.5746 | End Elevation | End Elevation | 216.151 | 0 | 0.0127 | 0 | 0.0127 | 0
804286 | Nivel 3 | 3.85 | 5.59986 | 5.61232 | 5.61233 | 0.0213442 | 0.0213464 | Nivel 3 | 8.45 | Level : Nivel 3 | 7.85 | 8.3 | 3.4246 | End Elevation | End Elevation | 132.786 | 0 | 0.0127 | 0 | 0.0127 | 0
804428 | Nivel 3 | 2.505 | 3.4213 | 3.43377 | 3.43377 | 0.0130405 | 0.0130403 | Nivel 3 | 8.45 | Level : Nivel 3 | 7.85 | 8.3 | 2.0923 | End Elevation | End Elevation | 81.1275 | 0 | 0 | 0 | 0.0127 | 0
804494 | Nivel 3 | 2.505 | 3.4213 | 3.43377 | 3.43377 | 0.0130405 | 0.0130403 | Nivel 3 | 8.45 | Level : Nivel 3 | 7.85 | 8.3 | 2.0923 | End Elevation | End Elevation | 81.1275 | 0 | 0 | 0 | 0.0127 | 0
811742 | Nivel 2 | 3.35 | 4.44689 | 4.45935 | 4.45935 | 0.0169496 | 0.0169494 | Nivel 2 | 4.2 | Level : Nivel 2 | 3.6 | 4.05 | 2.7195 | End Elevation | End Elevation | 105.447 | 0 | 0.0127 | 0 | 0.0127 | 0
811943 | Nivel 2 | 3.35 | 4.44689 | 4.45935 | 4.45935 | 0.0169496 | 0.0169494 | Nivel 2 | 4.2 | Level : Nivel 2 | 3.6 | 4.05 | 2.7195 | End Elevation | End Elevation | 105.447 | 0 | 0.0127 | 0 | 0.0127 | 0
829675 | Nivel 2 | 2.25 | 3.14708 | 3.15954 | 3.15954 | 0.0119953 | 0.0119951 | Nivel 2 | 4.2 | Level : Nivel 2 | 3.6 | 4.05 | 1.9246 | End Elevation | End Elevation | 74.625 | 0 | 0.0127 | 0 | 0.0127 | 0
829979 | Nivel 3 | 2.25 | 3.14708 | 3.15954 | 3.15954 | 0.0119953 | 0.0119951 | Nivel 3 | 8.45 | Level : Nivel 3 | 7.85 | 8.3 | 1.9246 | End Elevation | End Elevation | 74.625 | 0 | 0.0127 | 0 | 0.0127 | 0
830068 | Nivel 2 | 3.75 | 5.59986 | 5.61232 | 5.61232 | 0.0213442 | 0.0213439 | Nivel 2 | 4.2 | Level : Nivel 2 | 3.6 | 4.05 | 3.4246 | End Elevation | End Elevation | 132.786 | 0 | 0.0127 | 0 | 0.0127 | 0
830155 | Nivel 3 | 3.75 | 5.59986 | 5.61232 | 5.61232 | 0.0213442 | 0.0213439 | Nivel 3 | 8.45 | Level : Nivel 3 | 7.85 | 8.3 | 3.4246 | End Elevation | End Elevation | 132.786 | 0 | 0.0127 | 0 | 0.0127 | 0
832186 | Nivel 2 | 3.9319 | 5.78398 | 5.79645 | 5.79645 | 0.022046 | 0.0220457 | Nivel 2 | 4.2 | Level : Nivel 2 | 3.6 | 4.05 | 3.5372 | End Elevation | End Elevation | 137.152 | 0 | 0.0127 | 0 | 0 | -0.105
832387 | Nivel 2 | 4.5 | 6.66273 | 6.6752 | 6.6752 | 0.0253954 | 0.0253951 | Nivel 2 | 4.2 | Level : Nivel 2 | 3.6 | 4.05 | 4.0746 | End Elevation | End Elevation | 157.99 | 0 | 0.0127 | 0 | 0.0127 | 0
832418 | Nivel 2 | 4.5 | 6.66273 | 6.6752 | 6.6752 | 0.0253954 | 0.0253951 | Nivel 2 | 4.2 | Level : Nivel 2 | 3.6 | 4.05 | 4.0746 | End Elevation | End Elevation | 157.99 | 0 | 0.0127 | 0 | 0.0127 | -0.105
835236 | Nivel 3 | 3.75 | 5.59986 | 5.61232 | 5.61232 | 0.0213442 | 0.0213439 | Nivel 3 | 8.45 | Level : Nivel 3 | 7.85 | 8.3 | 3.4246 | End Elevation | End Elevation | 132.786 | 0 | 0.0127 | 0 | 0.0127 | 0.105
835300 | Nivel 2 | 3.75 | 5.59986 | 5.61232 | 5.61232 | 0.0213442 | 0.0213439 | Nivel 2 | 4.2 | Level : Nivel 2 | 3.6 | 4.05 | 3.4246 | End Elevation | End Elevation | 132.786 | 0 | 0.0127 | 0 | 0.0127 | 0.105
900691 | Nivel 2 | 3.85 | 5.76338 | 5.77584 | 5.77584 | 0.0219675 | 0.0219672 | Nivel 2 | 4.2 | Level : Nivel 2 | 3.6 | 4.05 | 3.5246 | End Elevation | End Elevation | 136.664 | 0 | 0.0127 | 0 | 0.0127 | 0.105
902263 | Nivel 2 | 8.45 | 13.3833 | 13.3958 | 13.3958 | 0.0510114 | 0.0510108 | Nivel 2 | 4.2 | Level : Nivel 2 | 3.6 | 4.05 | 8.1846 | End Elevation | End Elevation | 317.352 | 0 | 0.0127 | 1.12744 | 0.0127 | 0
902417 | Nivel 2 | 8.555 | 13.3915 | 13.404 | 13.404 | 0.0510426 | 0.0510419 | Nivel 2 | 4.2 | Level : Nivel 2 | 3.6 | 4.05 | 8.1896 | End Elevation |  | 317.546 | 0 | 0.0127 | 1.12744 | 0.0127 | 0
902694 | Nivel 2 | 1.9499 | 2.68906 | 2.70153 | 2.70153 | 0.0102495 | 0.0102494 | Nivel 2 | 4.2 | Level : Nivel 2 | 3.6 | 4.05 | 1.6445 | End Elevation | End Elevation | 63.7643 | 0 | 0.0127 | 0 | 0.0127 | 0.105
904554 | Nivel 2 | 3.3549 | 5.30978 | 5.32224 | 5.32224 | 0.0202385 | 0.0202383 | Nivel 2 | 4.2 | Level : Nivel 2 | 3.6 | 4.05 | 3.2472 |  |  | 125.908 | 0 |  | 0 | 0.0127 | 0
904620 | Nivel 2 | 3.3549 | 5.30978 | 5.32224 | 5.32224 | 0.0202385 | 0.0202383 | Nivel 2 | 4.2 | Level : Nivel 2 | 3.6 | 4.05 | 3.2472 |  |  | 125.908 | 0 |  | 0 | 0.0127 | 0
904755 | Nivel 2 | 3.3549 | 5.30978 | 5.32224 | 5.32224 | 0.0202385 | 0.0202383 | Nivel 2 | 4.2 | Level : Nivel 2 | 3.6 | 4.05 | 3.2472 |  |  | 125.908 | 0 |  | 0 | 0.0127 | 0
904757 | Nivel 2 | 3.3549 | 5.30978 | 5.32224 | 5.32224 | 0.0202385 | 0.0202383 | Nivel 2 | 4.2 | Level : Nivel 2 | 3.6 | 4.05 | 3.2472 |  |  | 125.908 | 0 |  | 0 | 0.0127 | 0
907028 | Nivel 3 | 8.445 | 13.4569 | 13.4694 | 13.4694 | 0.0512919 | 0.0512971 | Nivel 3 | 8.45 | Level : Nivel 3 | 7.85 | 8.3 | 88.5827 |  |  | 319.097 | 0 | 0.0127 | 0 | 0.0127 | 0.105
907166 | Nivel 3 | 8.445 | 13.2852 | 13.2977 | 13.2977 | 0.0506375 | 0.0506426 | Nivel 3 | 8.45 | Level : Nivel 3 | 7.85 | 8.3 | 8.1246 | End Elevation |  | 315.026 | 0 | 0.0127 | 0 | 0.0127 | 0.105
907239 | Nivel 3 | 3.3449 | 4.48842 | 4.50089 | 4.50089 | 0.0171079 | 0.0171077 | Nivel 3 | 8.45 | Level : Nivel 3 | 7.85 | 8.3 | 2.7449 | End Elevation | End Elevation | 106.432 | 0 | 0 | 0 | 0 | 0
909512 | Nivel 3 | 8.55 | 13.4568 | 13.4692 | 13.4692 | 0.0512913 | 0.0512906 | Nivel 3 | 8.45 | Level : Nivel 3 | 7.85 | 8.3 | 8.2295 |  | End Elevation | 319.093 | 0 | 0.0127 | 0 | 0.0127 | -0.105
909646 | Nivel 3 | 3.3449 | 4.46766 | 4.48012 | 4.48012 | 0.0170287 | 0.0170285 | Nivel 3 | 8.45 | Level : Nivel 3 | 7.85 | 8.3 | 2.7322 | End Elevation | End Elevation | 105.939 | 0 | 0.0127 | 0 | 0 | 0
909717 | Nivel 3 | 8.55 | 13.8047 | 13.8172 | 13.8172 | 0.0526176 | 0.0526169 | Nivel 3 | 8.45 | Level : Nivel 3 | 7.85 | 8.3 | 8.4423 |  |  | 327.344 | 0 | 0.0127 | 0 |  | 0

# IfcBeam: M_W Shapes:W550X210mm (3)
In: Nivel 2
Type - PredefinedType: BEAM; Material: Steel, 45-345
Type - Other - Category: Structural Framing; Family Name: M_W Shapes
Type - Identity Data - Code Name: AISC 14.1; OmniClass Number: 23.25.30.11.14.14; OmniClass Title: Beams; Section Name Key: W12x26; Type Name: W550X210mm
Type - Structural - Section Shape: 6
Type - Structural Analysis - Elastic Modulus strong axis: 0.000547 m3; Elastic Modulus weak axis: 0.0000875 m3; Moment of Inertia strong axis: 0.0000849 m4; Moment of Inertia weak axis: 0.0000072 m4; Nominal Weight: 379.516 kg/s2; Perimeter: 1.25 m; Plastic Modulus strong axis: 0.00061 m3; Plastic Modulus weak axis: 0.000134 m3; Section Area: 0.00494 m2; Torsional Moment of Inertia: 1.25e-07 m4; Warping Constant: 1.63e-07 m6
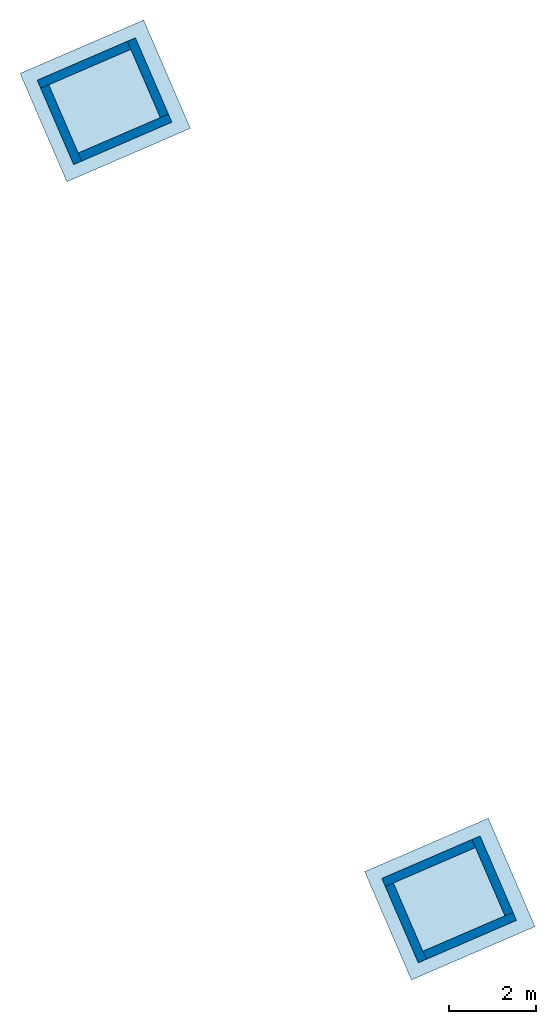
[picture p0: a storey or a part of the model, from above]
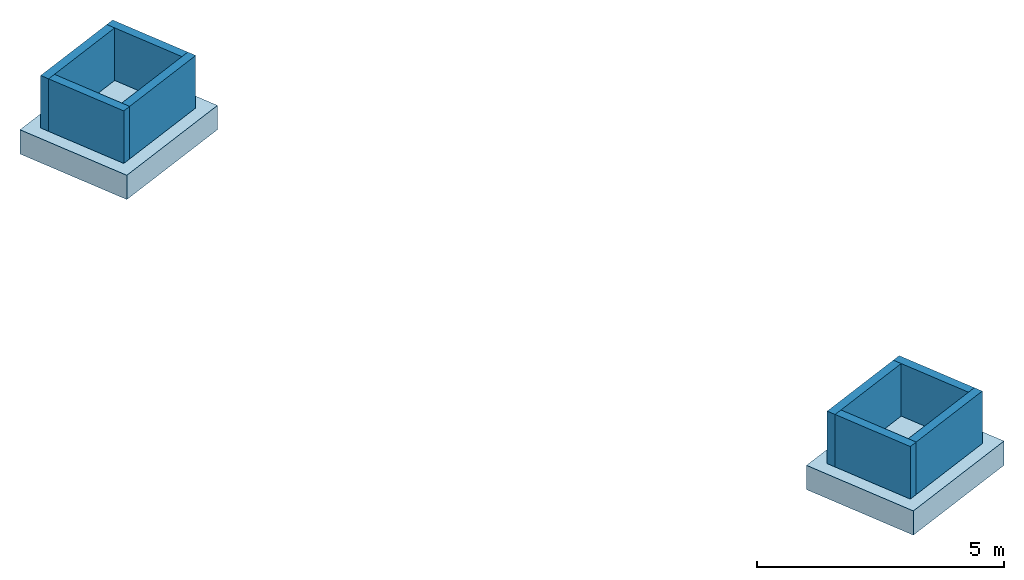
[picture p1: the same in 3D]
Properties of the parts of a building model (IFC4), part 3 of 4

# IfcBeam: M_W Shapes:W550X210mm (3)
Type - Structural Section Geometry - Centroid Horizontal: 0.105 m; Centroid Vertical: 0.275 m; Flange Thickness: 0.00965 m; Height: 0.55 m; Web Fillet: 0.00765 m; Web Thickness: 0.00584 m; Width: 0.21 m
Type - Pset_BeamCommon - LoadBearing: yes
Classification: B103 (FEMAP58); Material: Steel, 45-345; Steel, 45-345
Pset_BeamCommon - IsExternal: no; Slope: 0 deg; Roll: 0 deg; Span: 8.55 m; Reference: M_W Shapes:W550X210mm
Pset_EnvironmentalImpactIndicators - Reference: M_W Shapes:W550X210mm; sets with these values: 2
Qto_BeamBaseQuantities - Length: 8.55 m; CrossSectionArea: 0.00720263 m2; OuterSurfaceArea: 15.5601 m2; GrossSurfaceArea: 15.5745 m2; NetSurfaceArea: 15.5745 m2; GrossVolume: 0.0585185 m3; NetVolume: 0.0585177 m3
Other - Family: M_W Shapes; Family and Type: M_W Shapes: W550X210mm; Type: W550X210mm; Type Id: 902940
Constraints - Cross-Section Rotation: 0 deg; End Level Offset: 0 m; Orientation: Normal; Reference Level: Nivel 2; Start Level Offset: 0 m; Reference Level Elevation: 4.2 m; Work Plane: Level : Nivel 2
Dimensions - Elevation at Bottom: 3.5 m; Elevation at Top: 4.05 m; Length: 8.55 m; Volume: 0.0585177 m3
Materials and Finishes - Structural Material: Steel, 45-345
Phasing - Phase Created: New Construction
Structural - End Attachment Type: End Elevation; Start Attachment Type: End Elevation; Stick Symbol Location: Center of Geometry; Structural Usage: Primary; Cut Length: 8.1246 m; Weight: 315.026 kg
Geometric Position - End Extension: 0 m; Join Status: Both joins enabled; Start Extension: 0 m; y Justification: Origin; yz Justification: Uniform; z Justification: Top; y Offset Value: 0 m; End Join Cutback: 0.0127 m; Start Join Cutback: 0.0127 m; z Offset Value: -0.15 m
AboveGround - AboveGround: yes
Name (M_W Shapes:W550X210mm:...)
766236
783907
783931

# IfcColumn: M_Concrete-Round-Column:450mm (4)
In: d_Fundaciones
Type - PredefinedType: COLUMN; Material: HA
Type - Other - Category: Structural Columns; Family Name: M_Concrete-Round-Column
Type - Dimensions - b: 0.45 m
Type - Identity Data - OmniClass Number: 23.25.30.11.14.11; OmniClass Title: Columns; Type Name: 450mm
Type - Structural - Section Shape: 0
Type - Pset_ColumnCommon - LoadBearing: yes
Classification: B1041 (FEMAP58); Material: HA; HA
Qto_ColumnBaseQuantities - CrossSectionArea: 0.15902 m2
Pset_ColumnCommon - IsExternal: no; Reference: M_Concrete-Round-Column:450mm
Pset_EnvironmentalImpactIndicators - Reference: M_Concrete-Round-Column:450mm; sets with these values: 2
Other - Family: M_Concrete-Round-Column; Family and Type: M_Concrete-Round-Column: 450mm; Type: 450mm; Type Id: 824965
Constraints - Base Level: d_Fundaciones; Base Offset: 0 m; Column Style: Vertical; Level: d_Fundaciones; Moves With Grids: yes; Room Bounding: yes; Top Level: Nivel 2
Materials and Finishes - Structural Material: HA
Phasing - Phase Created: New Construction
Structural - Rebar Cover - Bottom Face: Rebar Cover 1 <25 mm>; Rebar Cover - Other Faces: Rebar Cover 1 <25 mm>; Rebar Cover - Top Face: Rebar Cover 1 <25 mm>
AboveGround - AboveGround: yes
Name (M_Concrete-Round-Column:450mm:...) | Qto_ColumnBaseQuantities, Length (m) = Dimensions, Length (m) | OuterSurfaceArea (m2) | GrossVolume (m3) | NetVolume (m3) = Volume (m3) | Column Location Mark | Top Offset (m)
816376 | 4.1 | 5.79624 | 0.651984 | 0.65206 | A-P1 | -1.05
823253 | 4.1 | 5.79624 | 0.651984 | 0.652064 | A-P2 | -1.05
859135 | 4.38 | 6.19208 | 0.696509 | 0.696595 | P1-P4 | -0.77
859137 | 4.38 | 6.19208 | 0.696509 | 0.696596 | P2-P4 | -0.77

# IfcColumn: M_Concrete-Square-Column:400 x 400mm (175)
Type - PredefinedType: COLUMN; Material: HA
Type - Other - Category: Structural Columns; Family Name: M_Concrete-Square-Column
Type - Data - Sup. en planta: 0.16 m2
Type - Dimensions - b: 0.4 m
Type - Identity Data - OmniClass Number: 23.25.30.11.14.11; OmniClass Title: Columns; Type Name: 400 x 400mm
Type - Structural - Section Shape: 0
Type - Pset_ColumnCommon - LoadBearing: yes
Classification: B1041 (FEMAP58); Material: HA; HA
Pset_ColumnCommon - Reference: M_Concrete-Square-Column:400 x 400mm; IsExternal: no
Pset_EnvironmentalImpactIndicators - Reference: M_Concrete-Square-Column:400 x 400mm; sets with these values: 2
Other - Family: M_Concrete-Square-Column; Family and Type: M_Concrete-Square-Column: 400 x 400mm; Type: 400 x 400mm; Type Id: 227260
Constraints - Base Offset: 0 m; Column Style: Vertical; Moves With Grids: yes; Room Bounding: yes; Top Offset: 0 m
Materials and Finishes - Structural Material: HA
Phasing - Phase Created: New Construction
Structural - Rebar Cover - Other Faces: Rebar Cover 1 <25 mm>
AboveGround - AboveGround: yes
Name (M_Concrete-Square-Column:400 x 400mm:...) | In | Qto_ColumnBaseQuantities, Length (m) | CrossSectionArea (m2) | OuterSurfaceArea (m2) | GrossVolume (m3) | NetVolume (m3) = Volume (m3) | Base Level = Level | Column Location Mark | Top Level | Dimensions, Length (m) | Rebar Cover - Bottom Face
762266 | d_Fundaciones | 4.1 | 0.16 | 6.56 | 0.656 | 0.768 | d_Fundaciones | G-2 | Nivel 2 | 5.15 | Rebar Cover 1 <25 mm>
762268 | d_Fundaciones | 4.1 | 0.16 | 6.56 | 0.656 | 0.768 | d_Fundaciones | F-2 | Nivel 2 | 5.15 | Rebar Cover 1 <25 mm>
762270 | d_Fundaciones | 4.1 | 0.16 | 6.56 | 0.656 | 0.768 | d_Fundaciones | E-2 | Nivel 2 | 5.15 | Rebar Cover 1 <25 mm>
762272 | d_Fundaciones | 4.1 | 0.16 | 6.56 | 0.656 | 0.768 | d_Fundaciones | D-2 | Nivel 2 | 5.15 | Rebar Cover 1 <25 mm>
762274 | d_Fundaciones | 4.1 | 0.16 | 6.56 | 0.656 | 0.768 | d_Fundaciones | C-2 | Nivel 2 | 5.15 | Rebar Cover 1 <25 mm>
762276 | d_Fundaciones | 4.1 | 0.16 | 6.56 | 0.656 | 0.768 | d_Fundaciones | B-2 | Nivel 2 | 5.15 | Rebar Cover 1 <25 mm>
762280 | d_Fundaciones | 4.1 | 0.16 | 6.56 | 0.656 | 0.768 | d_Fundaciones | G-3 | Nivel 2 | 5.15 | Rebar Cover 1 <25 mm>
762282 | d_Fundaciones | 4.1 | 0.16 | 6.56 | 0.656 | 0.768 | d_Fundaciones | F-3 | Nivel 2 | 5.15 | Rebar Cover 1 <25 mm>
762284 | d_Fundaciones | 4.1 | 0.16 | 6.56 | 0.656 | 0.768 | d_Fundaciones | E-3 | Nivel 2 | 5.15 | Rebar Cover 1 <25 mm>
762286 | d_Fundaciones | 4.1 | 0.16 | 6.56 | 0.656 | 0.768 | d_Fundaciones | D-3 | Nivel 2 | 5.15 | Rebar Cover 1 <25 mm>
762288 | d_Fundaciones | 4.1 | 0.16 | 6.56 | 0.656 | 0.768 | d_Fundaciones | C-3 | Nivel 2 | 5.15 | Rebar Cover 1 <25 mm>
762290 | d_Fundaciones | 4.1 | 0.16 | 6.56 | 0.656 | 0.768 | d_Fundaciones | B-3 | Nivel 2 | 5.15 | Rebar Cover 1 <25 mm>
762294 | d_Fundaciones | 4.1 | 0.16 | 6.56 | 0.656 | 0.768 | d_Fundaciones | G-4 | Nivel 2 | 5.15 | Rebar Cover 1 <25 mm>
762296 | d_Fundaciones | 4.1 | 0.16 | 6.56 | 0.656 | 0.768 | d_Fundaciones | F-4 | Nivel 2 | 5.15 | Rebar Cover 1 <25 mm>
762298 | d_Fundaciones | 4.1 | 0.16 | 6.56 | 0.656 | 0.768 | d_Fundaciones | E-4 | Nivel 2 | 5.15 | Rebar Cover 1 <25 mm>
762300 | d_Fundaciones | 4.1 | 0.16 | 6.56 | 0.656 | 0.768 | d_Fundaciones | D-4 | Nivel 2 | 5.15 | Rebar Cover 1 <25 mm>
762302 | d_Fundaciones | 4.1 | 0.16 | 6.56 | 0.656 | 0.768 | d_Fundaciones | C-4 | Nivel 2 | 5.15 | Rebar Cover 1 <25 mm>
762304 | d_Fundaciones | 4.1 | 0.16 | 6.56 | 0.656 | 0.768 | d_Fundaciones | B-4 | Nivel 2 | 5.15 | Rebar Cover 1 <25 mm>
762308 | d_Fundaciones | 4.1 | 0.16 | 6.56 | 0.656 | 0.768 | d_Fundaciones | G-5 | Nivel 2 | 5.15 | Rebar Cover 1 <25 mm>
762310 | d_Fundaciones | 4.1 | 0.16 | 6.56 | 0.656 | 0.768 | d_Fundaciones | F-5 | Nivel 2 | 5.15 | Rebar Cover 1 <25 mm>
762312 | d_Fundaciones | 4.1 | 0.16 | 6.56 | 0.656 | 0.768 | d_Fundaciones | E-5 | Nivel 2 | 5.15 | Rebar Cover 1 <25 mm>
762314 | d_Fundaciones | 4.1 | 0.16 | 6.56 | 0.656 | 0.768 | d_Fundaciones | D-5 | Nivel 2 | 5.15 | Rebar Cover 1 <25 mm>
762316 | d_Fundaciones | 4.1 | 0.16 | 6.56 | 0.656 | 0.768 | d_Fundaciones | C-5 | Nivel 2 | 5.15 | Rebar Cover 1 <25 mm>
762318 | d_Fundaciones | 4.1 | 0.16 | 6.56 | 0.656 | 0.768 | d_Fundaciones | B-5 | Nivel 2 | 5.15 | Rebar Cover 1 <25 mm>
762322 | d_Fundaciones | 4.1 | 0.16 | 6.56 | 0.656 | 0.768 | d_Fundaciones | G-6 | Nivel 2 | 5.15 | Rebar Cover 1 <25 mm>
762324 | d_Fundaciones | 4.1 | 0.16 | 6.56 | 0.656 | 0.768 | d_Fundaciones | F-6 | Nivel 2 | 5.15 | Rebar Cover 1 <25 mm>
762326 | d_Fundaciones | 4.1 | 0.16 | 6.56 | 0.656 | 0.768 | d_Fundaciones | E-6 | Nivel 2 | 5.15 | Rebar Cover 1 <25 mm>
762328 | d_Fundaciones | 4.1 | 0.16 | 6.56 | 0.656 | 0.768 | d_Fundaciones | D-6 | Nivel 2 | 5.15 | Rebar Cover 1 <25 mm>
762330 | d_Fundaciones | 4.1 | 0.16 | 6.56 | 0.656 | 0.768 | d_Fundaciones | C-6 | Nivel 2 | 5.15 | Rebar Cover 1 <25 mm>
762332 | d_Fundaciones | 4.1 | 0.16 | 6.56 | 0.656 | 0.768 | d_Fundaciones | B-6 | Nivel 2 | 5.15 | Rebar Cover 1 <25 mm>
762336 | d_Fundaciones | 4.1 | 0.16 | 6.56 | 0.656 | 0.768 | d_Fundaciones | G-7 | Nivel 2 | 5.15 | Rebar Cover 1 <25 mm>
762338 | d_Fundaciones | 4.1 | 0.16 | 6.56 | 0.656 | 0.768 | d_Fundaciones | F-7 | Nivel 2 | 5.15 | Rebar Cover 1 <25 mm>
762340 | d_Fundaciones | 4.1 | 0.16 | 6.56 | 0.656 | 0.768 | d_Fundaciones | E-7 | Nivel 2 | 5.15 | Rebar Cover 1 <25 mm>
762342 | d_Fundaciones | 4.1 | 0.16 | 6.56 | 0.656 | 0.768 | d_Fundaciones | D-7 | Nivel 2 | 5.15 | Rebar Cover 1 <25 mm>
762344 | d_Fundaciones | 4.1 | 0.16 | 6.56 | 0.656 | 0.768 | d_Fundaciones | C-7 | Nivel 2 | 5.15 | Rebar Cover 1 <25 mm>
762346 | d_Fundaciones | 4.1 | 0.16 | 6.56 | 0.656 | 0.768 | d_Fundaciones | B-7 | Nivel 2 | 5.15 | Rebar Cover 1 <25 mm>
762350 | d_Fundaciones | 5 | 0.16 | 8 | 0.8 | 0.8 | d_Fundaciones | G-8 | Nivel 2 | 5.15 | Rebar Cover 1 <25 mm>
762352 | d_Fundaciones | 5 | 0.16 | 8 | 0.8 | 0.8 | d_Fundaciones | F-8 | Nivel 2 | 5.15 | Rebar Cover 1 <25 mm>
762354 | d_Fundaciones | 5 | 0.16 | 8 | 0.8 | 0.8 | d_Fundaciones | E-8 | Nivel 2 | 5.15 | Rebar Cover 1 <25 mm>
762356 | d_Fundaciones | 5 | 0.16 | 8 | 0.8 | 0.8 | d_Fundaciones | D-8 | Nivel 2 | 5.15 | Rebar Cover 1 <25 mm>
762358 | d_Fundaciones | 5 | 0.16 | 8 | 0.8 | 0.8 | d_Fundaciones | C-8 | Nivel 2 | 5.15 | Rebar Cover 1 <25 mm>
762360 | d_Fundaciones | 5 | 0.16 | 8 | 0.8 | 0.8 | d_Fundaciones | B-8 | Nivel 2 | 5.15 | Rebar Cover 1 <25 mm>
762364 | d_Fundaciones | 5 | 0.16 | 8 | 0.8 | 0.8 | d_Fundaciones | G-9 | Nivel 2 | 5.15 | Rebar Cover 1 <25 mm>
762366 | d_Fundaciones | 5 | 0.16 | 8 | 0.8 | 0.8 | d_Fundaciones | F-9 | Nivel 2 | 5.15 | Rebar Cover 1 <25 mm>
762368 | d_Fundaciones | 5 | 0.16 | 8 | 0.8 | 0.8 | d_Fundaciones | E-9 | Nivel 2 | 5.15 | Rebar Cover 1 <25 mm>
762370 | d_Fundaciones | 5 | 0.16 | 8 | 0.8 | 0.8 | d_Fundaciones | D-9 | Nivel 2 | 5.15 | Rebar Cover 1 <25 mm>
762372 | d_Fundaciones | 5 | 0.16 | 8 | 0.8 | 0.8 | d_Fundaciones | C-9 | Nivel 2 | 5.15 | Rebar Cover 1 <25 mm>
762374 | d_Fundaciones | 5 | 0.16 | 8 | 0.8 | 0.8 | d_Fundaciones | B-9 | Nivel 2 | 5.15 | Rebar Cover 1 <25 mm>
762378 | d_Fundaciones | 5 | 0.16 | 8 | 0.8 | 0.8 | d_Fundaciones | G-10 | Nivel 2 | 5.15 | Rebar Cover 1 <25 mm>
762380 | d_Fundaciones | 5 | 0.16 | 8 | 0.8 | 0.8 | d_Fundaciones | F-10 | Nivel 2 | 5.15 | Rebar Cover 1 <25 mm>
762382 | d_Fundaciones | 5 | 0.16 | 8 | 0.8 | 0.8 | d_Fundaciones | E-10 | Nivel 2 | 5.15 | Rebar Cover 1 <25 mm>
762384 | d_Fundaciones | 5 | 0.16 | 8 | 0.8 | 0.8 | d_Fundaciones | D-10 | Nivel 2 | 5.15 | Rebar Cover 1 <25 mm>
762386 | d_Fundaciones | 5 | 0.16 | 8 | 0.8 | 0.8 | d_Fundaciones | C-10 | Nivel 2 | 5.15 | Rebar Cover 1 <25 mm>
762388 | d_Fundaciones | 5 | 0.16 | 8 | 0.8 | 0.8 | d_Fundaciones | B-10 | Nivel 2 | 5.15 | Rebar Cover 1 <25 mm>
779855 | d_Fundaciones | 5 | 0.16 | 8 | 0.8 | 0.8 | d_Fundaciones | A-8 | Nivel 2 | 5.15 | Rebar Cover 1 <25 mm>
779857 | d_Fundaciones | 5 | 0.16 | 8 | 0.8 | 0.8 | d_Fundaciones | A-9 | Nivel 2 | 5.15 | Rebar Cover 1 <25 mm>
779859 | d_Fundaciones | 5 | 0.16 | 8 | 0.8 | 0.8 | d_Fundaciones | A-10 | Nivel 2 | 5.15 | Rebar Cover 1 <25 mm>
780082 | d_Fundaciones | 4.1 | 0.16 | 6.56 | 0.656 | 0.768 | d_Fundaciones | B'-2 | Nivel 2 | 5.15 | Rebar Cover 1 <25 mm>
780084 | d_Fundaciones | 4.1 | 0.16 | 6.56 | 0.656 | 0.768 | d_Fundaciones | B'-3 | Nivel 2 | 5.15 | Rebar Cover 1 <25 mm>
780086 | d_Fundaciones | 4.1 | 0.16 | 6.56 | 0.656 | 0.768 | d_Fundaciones | B'-4 | Nivel 2 | 5.15 | Rebar Cover 1 <25 mm>
780088 | d_Fundaciones | 4.1 | 0.16 | 6.56 | 0.656 | 0.768 | d_Fundaciones | B'-5 | Nivel 2 | 5.15 | Rebar Cover 1 <25 mm>
780090 | d_Fundaciones | 4.1 | 0.16 | 6.56 | 0.656 | 0.768 | d_Fundaciones | B'-6 | Nivel 2 | 5.15 | Rebar Cover 1 <25 mm>
780092 | d_Fundaciones | 4.1 | 0.16 | 6.56 | 0.656 | 0.768 | d_Fundaciones | B'-7 | Nivel 2 | 5.15 | Rebar Cover 1 <25 mm>
780094 | d_Fundaciones | 5 | 0.16 | 8 | 0.8 | 0.8 | d_Fundaciones | B'-8 | Nivel 2 | 5.15 | Rebar Cover 1 <25 mm>
780096 | d_Fundaciones | 5 | 0.16 | 8 | 0.8 | 0.8 | d_Fundaciones | B'-9 | Nivel 2 | 5.15 | Rebar Cover 1 <25 mm>
780098 | d_Fundaciones | 5 | 0.16 | 8 | 0.8 | 0.8 | d_Fundaciones | B'-10 | Nivel 2 | 5.15 | Rebar Cover 1 <25 mm>
780152 | d_Fundaciones | 5 | 0.16 | 8 | 0.8 | 0.8 | d_Fundaciones | H-8 | Nivel 2 | 5.15 | Rebar Cover 1 <25 mm>
780154 | d_Fundaciones | 5 | 0.16 | 8 | 0.8 | 0.8 | d_Fundaciones | H-9 | Nivel 2 | 5.15 | Rebar Cover 1 <25 mm>
780156 | d_Fundaciones | 5 | 0.16 | 8 | 0.8 | 0.8 | d_Fundaciones | H-10 | Nivel 2 | 5.15 | Rebar Cover 1 <25 mm>
781172 | Nivel 2 | 4.1 | 0.16 | 6.56 | 0.656 | 0.656 | Nivel 2 | G-2 | Nivel 3 | 4.25
781174 | Nivel 2 | 4.1 | 0.16 | 6.56 | 0.656 | 0.656 | Nivel 2 | F-2 | Nivel 3 | 4.25
781178 | Nivel 2 | 4.1 | 0.16 | 6.56 | 0.656 | 0.656 | Nivel 2 | D-2 | Nivel 3 | 4.25
781180 | Nivel 2 | 4.1 | 0.16 | 6.56 | 0.656 | 0.656 | Nivel 2 | C-2 | Nivel 3 | 4.25
781182 | Nivel 2 | 4.1 | 0.16 | 6.56 | 0.656 | 0.656 | Nivel 2 | B-2 | Nivel 3 | 4.25
781184 | Nivel 2 | 4.1 | 0.16 | 6.56 | 0.656 | 0.656 | Nivel 2 | G-3 | Nivel 3 | 4.25
781186 | Nivel 2 | 4.1 | 0.16 | 6.56 | 0.656 | 0.656 | Nivel 2 | F-3 | Nivel 3 | 4.25
781188 | Nivel 2 | 4.1 | 0.16 | 6.56 | 0.656 | 0.656 | Nivel 2 | E-3 | Nivel 3 | 4.25
781190 | Nivel 2 | 4.1 | 0.16 | 6.56 | 0.656 | 0.656 | Nivel 2 | D-3 | Nivel 3 | 4.25
781192 | Nivel 2 | 4.1 | 0.16 | 6.56 | 0.656 | 0.656 | Nivel 2 | C-3 | Nivel 3 | 4.25
781194 | Nivel 2 | 4.1 | 0.16 | 6.56 | 0.656 | 0.656 | Nivel 2 | B-3 | Nivel 3 | 4.25
781196 | Nivel 2 | 4.1 | 0.16 | 6.56 | 0.656 | 0.656 | Nivel 2 | G-4 | Nivel 3 | 4.25
781198 | Nivel 2 | 4.1 | 0.16 | 6.56 | 0.656 | 0.656 | Nivel 2 | F-4 | Nivel 3 | 4.25
781200 | Nivel 2 | 4.1 | 0.16 | 6.56 | 0.656 | 0.656 | Nivel 2 | E-4 | Nivel 3 | 4.25
781202 | Nivel 2 | 4.1 | 0.16 | 6.56 | 0.656 | 0.656 | Nivel 2 | D-4 | Nivel 3 | 4.25
781204 | Nivel 2 | 4.1 | 0.16 | 6.56 | 0.656 | 0.656 | Nivel 2 | C-4 | Nivel 3 | 4.25
781206 | Nivel 2 | 4.1 | 0.16 | 6.56 | 0.656 | 0.656 | Nivel 2 | B-4 | Nivel 3 | 4.25
781208 | Nivel 2 | 4.1 | 0.16 | 6.56 | 0.656 | 0.656 | Nivel 2 | G-5 | Nivel 3 | 4.25
781210 | Nivel 2 | 4.1 | 0.16 | 6.56 | 0.656 | 0.656 | Nivel 2 | F-5 | Nivel 3 | 4.25
781212 | Nivel 2 | 4.1 | 0.16 | 6.56 | 0.656 | 0.656 | Nivel 2 | E-5 | Nivel 3 | 4.25
781214 | Nivel 2 | 4.1 | 0.16 | 6.56 | 0.656 | 0.656 | Nivel 2 | D-5 | Nivel 3 | 4.25
781216 | Nivel 2 | 4.1 | 0.16 | 6.56 | 0.656 | 0.656 | Nivel 2 | C-5 | Nivel 3 | 4.25
781218 | Nivel 2 | 4.1 | 0.16 | 6.56 | 0.656 | 0.656 | Nivel 2 | B-5 | Nivel 3 | 4.25
781220 | Nivel 2 | 4.1 | 0.16 | 6.56 | 0.656 | 0.656 | Nivel 2 | G-6 | Nivel 3 | 4.25
781222 | Nivel 2 | 4.1 | 0.16 | 6.56 | 0.656 | 0.656 | Nivel 2 | F-6 | Nivel 3 | 4.25
781224 | Nivel 2 | 4.1 | 0.16 | 6.56 | 0.656 | 0.656 | Nivel 2 | E-6 | Nivel 3 | 4.25
781226 | Nivel 2 | 4.1 | 0.16 | 6.56 | 0.656 | 0.656 | Nivel 2 | D-6 | Nivel 3 | 4.25
781228 | Nivel 2 | 4.1 | 0.16 | 6.56 | 0.656 | 0.656 | Nivel 2 | C-6 | Nivel 3 | 4.25
781230 | Nivel 2 | 4.1 | 0.16 | 6.56 | 0.656 | 0.656 | Nivel 2 | B-6 | Nivel 3 | 4.25
781232 | Nivel 2 | 4.1 | 0.16 | 6.56 | 0.656 | 0.656 | Nivel 2 | G-7 | Nivel 3 | 4.25
781234 | Nivel 2 | 4.1 | 0.16 | 6.56 | 0.656 | 0.656 | Nivel 2 | F-7 | Nivel 3 | 4.25
781236 | Nivel 2 | 4.1 | 0.16 | 6.56 | 0.656 | 0.656 | Nivel 2 | E-7 | Nivel 3 | 4.25
781238 | Nivel 2 | 4.1 | 0.16 | 6.56 | 0.656 | 0.656 | Nivel 2 | D-7 | Nivel 3 | 4.25
781240 | Nivel 2 | 4.1 | 0.16 | 6.56 | 0.656 | 0.656 | Nivel 2 | C-7 | Nivel 3 | 4.25
781242 | Nivel 2 | 4.1 | 0.16 | 6.56 | 0.656 | 0.656 | Nivel 2 | B-7 | Nivel 3 | 4.25
781244 | Nivel 2 | 4.1 | 0.16 | 6.56 | 0.656 | 0.656 | Nivel 2 | G-8 | Nivel 3 | 4.25
781246 | Nivel 2 | 4.1 | 0.16 | 6.56 | 0.656 | 0.656 | Nivel 2 | F-8 | Nivel 3 | 4.25
781248 | Nivel 2 | 4.1 | 0.16 | 6.56 | 0.656 | 0.656 | Nivel 2 | E-8 | Nivel 3 | 4.25
781250 | Nivel 2 | 4.1 | 0.16 | 6.56 | 0.656 | 0.656 | Nivel 2 | D-8 | Nivel 3 | 4.25
781252 | Nivel 2 | 4.1 | 0.16 | 6.56 | 0.656 | 0.656 | Nivel 2 | C-8 | Nivel 3 | 4.25
781254 | Nivel 2 | 4.1 | 0.16 | 6.56 | 0.656 | 0.656 | Nivel 2 | B-8 | Nivel 3 | 4.25
781256 | Nivel 2 | 4.1 | 0.16 | 6.56 | 0.656 | 0.656 | Nivel 2 | G-9 | Nivel 3 | 4.25
781258 | Nivel 2 | 4.1 | 0.16 | 6.56 | 0.656 | 0.656 | Nivel 2 | F-9 | Nivel 3 | 4.25
781260 | Nivel 2 | 4.1 | 0.16 | 6.56 | 0.656 | 0.656 | Nivel 2 | E-9 | Nivel 3 | 4.25
781262 | Nivel 2 | 4.1 | 0.16 | 6.56 | 0.656 | 0.656 | Nivel 2 | D-9 | Nivel 3 | 4.25
781264 | Nivel 2 | 4.1 | 0.16 | 6.56 | 0.656 | 0.656 | Nivel 2 | C-9 | Nivel 3 | 4.25
781266 | Nivel 2 | 4.1 | 0.16 | 6.56 | 0.656 | 0.656 | Nivel 2 | B-9 | Nivel 3 | 4.25
781268 | Nivel 2 | 4.1 | 0.16 | 6.56 | 0.656 | 0.656 | Nivel 2 | G-10 | Nivel 3 | 4.25
781270 | Nivel 2 | 4.1 | 0.16 | 6.56 | 0.656 | 0.656 | Nivel 2 | F-10 | Nivel 3 | 4.25
781272 | Nivel 2 | 4.1 | 0.16 | 6.56 | 0.656 | 0.656 | Nivel 2 | E-10 | Nivel 3 | 4.25
781274 | Nivel 2 | 4.1 | 0.16 | 6.56 | 0.656 | 0.656 | Nivel 2 | D-10 | Nivel 3 | 4.25
781276 | Nivel 2 | 4.1 | 0.16 | 6.56 | 0.656 | 0.656 | Nivel 2 | C-10 | Nivel 3 | 4.25
781278 | Nivel 2 | 4.1 | 0.16 | 6.56 | 0.656 | 0.656 | Nivel 2 | B-10 | Nivel 3 | 4.25
781288 | Nivel 2 | 4.1 | 0.16 | 6.56 | 0.656 | 0.656 | Nivel 2 | B'-2 | Nivel 3 | 4.25
781290 | Nivel 2 | 4.1 | 0.16 | 6.56 | 0.656 | 0.656 | Nivel 2 | B'-3 | Nivel 3 | 4.25
781292 | Nivel 2 | 4.1 | 0.16 | 6.56 | 0.656 | 0.656 | Nivel 2 | B'-4 | Nivel 3 | 4.25
781294 | Nivel 2 | 4.1 | 0.16 | 6.56 | 0.656 | 0.656 | Nivel 2 | B'-5 | Nivel 3 | 4.25
781296 | Nivel 2 | 4.1 | 0.16 | 6.56 | 0.656 | 0.656 | Nivel 2 | B'-6 | Nivel 3 | 4.25
781298 | Nivel 2 | 4.1 | 0.16 | 6.56 | 0.656 | 0.656 | Nivel 2 | B'-7 | Nivel 3 | 4.25
781300 | Nivel 2 | 4.1 | 0.16 | 6.56 | 0.656 | 0.656 | Nivel 2 | B'-8 | Nivel 3 | 4.25
781302 | Nivel 2 | 4.1 | 0.16 | 6.56 | 0.656 | 0.656 | Nivel 2 | B'-9 | Nivel 3 | 4.25
781304 | Nivel 2 | 4.1 | 0.16 | 6.56 | 0.656 | 0.656 | Nivel 2 | B'-10 | Nivel 3 | 4.25
781306 | Nivel 2 | 4.1 | 0.16 | 6.56 | 0.656 | 0.656 | Nivel 2 | H-8 | Nivel 3 | 4.25
781308 | Nivel 2 | 4.1 | 0.16 | 6.56 | 0.656 | 0.656 | Nivel 2 | H-9 | Nivel 3 | 4.25
781310 | Nivel 2 | 4.1 | 0.16 | 6.56 | 0.656 | 0.656 | Nivel 2 | H-10 | Nivel 3 | 4.25
784538 | d_Fundaciones | 4.25 | 0.16 | 6.8 | 0.68 | 0.792 | d_Fundaciones | A'-6 | Nivel 2 | 5.15 | Rebar Cover 1 <25 mm> | Structural - Rebar Cover - Top Face: Rebar Cover 1 <25 mm>
784571 | d_Fundaciones | 4.25 | 0.16 | 6.8 | 0.68 | 0.792 | d_Fundaciones | A'-5 | Nivel 2 | 5.15 | Rebar Cover 1 <25 mm> | Structural - Rebar Cover - Top Face: Rebar Cover 1 <25 mm>
793427 | Nivel 2 | 4.1 | 0.16 | 6.56 | 0.656 | 0.656 | Nivel 2 | A'-6 | Nivel 3 | 4.25 | Rebar Cover 1 <25 mm>
793429 | Nivel 2 | 4.1 | 0.16 | 6.56 | 0.656 | 0.656 | Nivel 2 | A'-5 | Nivel 3 | 4.25 | Rebar Cover 1 <25 mm>
793476 | Nivel 2 | 4.1 | 0.16 | 6.56 | 0.656 | 0.656 | Nivel 2 | A'-7 | Nivel 3 | 4.25 | Rebar Cover 1 <25 mm>
793635 | d_Fundaciones | 4.25 | 0.16 | 6.8 | 0.68 | 0.792 | d_Fundaciones | A'-7 | Nivel 2 | 5.15 | Rebar Cover 1 <25 mm> | Structural - Rebar Cover - Top Face: Rebar Cover 1 <25 mm>
793662 | d_Fundaciones | 5 | 0.16 | 8 | 0.8 | 0.8 | d_Fundaciones | A'-8 | Nivel 2 | 5.15 | Rebar Cover 1 <25 mm>
793679 | d_Fundaciones | 5 | 0.16 | 8 | 0.8 | 0.8 | d_Fundaciones | A'-9 | Nivel 2 | 5.15 | Rebar Cover 1 <25 mm>
793696 | d_Fundaciones | 5 | 0.16 | 8 | 0.8 | 0.8 | d_Fundaciones | A'-10 | Nivel 2 | 5.15 | Rebar Cover 1 <25 mm>
793731 | Nivel 2 | 4.1 | 0.16 | 6.56 | 0.656 | 0.656 | Nivel 2 | A'-8 | Nivel 3 | 4.25
793742 | Nivel 2 | 4.1 | 0.16 | 6.56 | 0.656 | 0.656 | Nivel 2 | A'-9 | Nivel 3 | 4.25
793755 | Nivel 2 | 4.1 | 0.16 | 6.56 | 0.656 | 0.656 | Nivel 2 | A'-10 | Nivel 3 | 4.25
801763 | d_Fundaciones | 5 | 0.16 | 8 | 0.8 | 0.8 | d_Fundaciones | C-7' | Nivel 2 | 5.15 | Rebar Cover 1 <25 mm>
801765 | d_Fundaciones | 5 | 0.16 | 8 | 0.8 | 0.8 | d_Fundaciones | B-7' | Nivel 2 | 5.15 | Rebar Cover 1 <25 mm>
801767 | d_Fundaciones | 5 | 0.16 | 8 | 0.8 | 0.8 | d_Fundaciones | A-7' | Nivel 2 | 5.15 | Rebar Cover 1 <25 mm>
801769 | d_Fundaciones | 5 | 0.16 | 8 | 0.8 | 0.8 | d_Fundaciones | B'-7' | Nivel 2 | 5.15 | Rebar Cover 1 <25 mm>
801771 | d_Fundaciones | 5 | 0.16 | 8 | 0.8 | 0.8 | d_Fundaciones | A'-7' | Nivel 2 | 5.15 | Rebar Cover 1 <25 mm>
801819 | d_Fundaciones | 5 | 0.16 | 8 | 0.8 | 0.8 | d_Fundaciones | A-7'' | Nivel 2 | 5.15 | Rebar Cover 1 <25 mm>
801821 | d_Fundaciones | 5 | 0.16 | 8 | 0.8 | 0.8 | d_Fundaciones | A'-7'' | Nivel 2 | 5.15 | Rebar Cover 1 <25 mm>
801867 | d_Fundaciones | 4.1 | 0.16 | 6.56 | 0.656 | 0.768 | d_Fundaciones | F-4' | Nivel 2 | 5.15 | Rebar Cover 1 <25 mm>
801913 | d_Fundaciones | 5.15 | 0.16 | 8.24 | 0.824 | 0.824 | d_Fundaciones | F'-4' | Nivel 2 | 5.15 | Rebar Cover 1 <25 mm> | Structural - Rebar Cover - Top Face: Rebar Cover 1 <25 mm>
801948 | d_Fundaciones | 4.1 | 0.16 | 6.56 | 0.656 | 0.768 | d_Fundaciones | C-4' | Nivel 2 | 5.15 | Rebar Cover 1 <25 mm>
801950 | d_Fundaciones | 4.1 | 0.16 | 6.56 | 0.656 | 0.768 | d_Fundaciones | B-4' | Nivel 2 | 5.15 | Rebar Cover 1 <25 mm>
801952 | d_Fundaciones | 4.1 | 0.16 | 6.56 | 0.656 | 0.768 | d_Fundaciones | B'-4' | Nivel 2 | 5.15 | Rebar Cover 1 <25 mm>
801999 | d_Fundaciones | 5 | 0.16 | 8 | 0.8 | 0.8 | d_Fundaciones | F-7' | Nivel 2 | 5.15 | Rebar Cover 1 <25 mm>
802001 | d_Fundaciones | 5.15 | 0.16 | 8.24 | 0.824 | 0.824 | d_Fundaciones | F'-7' | Nivel 2 | 5.15 | Rebar Cover 1 <25 mm> | Structural - Rebar Cover - Top Face: Rebar Cover 1 <25 mm>
802397 | Nivel 2 | 4.1 | 0.16 | 6.56 | 0.656 | 0.656 | Nivel 2 | F-4' | Nivel 3 | 4.25
802412 | Nivel 2 | 4.1 | 0.16 | 6.56 | 0.656 | 0.656 | Nivel 2 | F'-4' | Nivel 3 | 4.25 | Rebar Cover 1 <25 mm>
802481 | Nivel 2 | 4.1 | 0.16 | 6.56 | 0.656 | 0.656 | Nivel 2 | C-4' | Nivel 3 | 4.25
802483 | Nivel 2 | 4.1 | 0.16 | 6.56 | 0.656 | 0.656 | Nivel 2 | B-4' | Nivel 3 | 4.25
802485 | Nivel 2 | 4.1 | 0.16 | 6.56 | 0.656 | 0.656 | Nivel 2 | B'-4' | Nivel 3 | 4.25
802648 | Nivel 2 | 4.1 | 0.16 | 6.56 | 0.656 | 0.656 | Nivel 2 | C-7' | Nivel 3 | 4.25
802650 | Nivel 2 | 4.1 | 0.16 | 6.56 | 0.656 | 0.656 | Nivel 2 | B-7' | Nivel 3 | 4.25
802652 | Nivel 2 | 4.1 | 0.16 | 6.56 | 0.656 | 0.656 | Nivel 2 | B'-7' | Nivel 3 | 4.25
802654 | Nivel 2 | 4.1 | 0.16 | 6.56 | 0.656 | 0.656 | Nivel 2 | A'-7' | Nivel 3 | 4.25
804345 | Nivel 2 | 4.1 | 0.16 | 6.56 | 0.656 | 0.656 | Nivel 2 | F-7' | Nivel 3 | 4.25
804347 | Nivel 2 | 4.1 | 0.16 | 6.56 | 0.656 | 0.656 | Nivel 2 | F'-7' | Nivel 3 | 4.25 | Rebar Cover 1 <25 mm>
811681 | d_Fundaciones | 0.4 | 1.67075 | 3.72 | 0.6683 | 0.7803 | d_Fundaciones | J-4' | Nivel 2 | 5.15 | Rebar Cover 1 <25 mm> | Structural - Rebar Cover - Top Face: Rebar Cover 1 <25 mm>
811900 | d_Fundaciones | 0.4 | 1.67075 | 3.72 | 0.6683 | 0.7803 | d_Fundaciones | J-7' | Nivel 2 | 5.15 | Rebar Cover 1 <25 mm> | Structural - Rebar Cover - Top Face: Rebar Cover 1 <25 mm>
905555 | Nivel 2 | 4.1 | 0.16 | 6.56 | 0.656 | 0.656 | Nivel 2 | J-4' | Nivel 3 | 4.25 | Rebar Cover 1 <25 mm>
909579 | Nivel 2 | 4.1 | 0.16 | 6.56 | 0.656 | 0.656 | Nivel 2 | J-7' | Nivel 3 | 4.25 | Rebar Cover 1 <25 mm>

# IfcColumn: M_W Shapes-Column:HEA 200 (16)
Type - PredefinedType: COLUMN; Material: Steel, 45-345
Type - Other - Category: Structural Columns; Family Name: M_W Shapes-Column
Type - Identity Data - Code Name: AISC 14.1; OmniClass Number: 23.25.30.11.14.11; OmniClass Title: Columns; Section Name Key: W10x33; Type Name: HEA 200
Type - Structural - Section Shape: 6
Type - Structural Analysis - Elastic Modulus strong axis: 0.000574 m3; Elastic Modulus weak axis: 0.000151 m3; Moment of Inertia strong axis: 0.0000712 m4; Moment of Inertia weak axis: 0.0000152 m4; Nominal Weight: 481.505 kg/s2; Perimeter: 1.27 m; Plastic Modulus strong axis: 0.000636 m3; Plastic Modulus weak axis: 0.000229 m3; Section Area: 0.00626 m2; Torsional Moment of Inertia: 2.43e-07 m4; Warping Constant: 2.12e-07 m6
Type - Structural Section Geometry - Centroid Horizontal: 0.1 m; Centroid Vertical: 0.1 m; Flange Thickness: 0.011 m; Height: 0.2 m; Web Fillet: 0.0127 m; Web Thickness: 0.00737 m; Width: 0.2 m
Type - Pset_ColumnCommon - LoadBearing: yes
Classification: B1031 (FEMAP58); Material: Steel, 45-345; Steel, 45-345
Qto_ColumnBaseQuantities - CrossSectionArea: 0.00585042 m2
Pset_ColumnCommon - IsExternal: no; Reference: M_W Shapes-Column:HEA 200
Pset_EnvironmentalImpactIndicators - Reference: M_W Shapes-Column:HEA 200; sets with these values: 2
Other - Family: M_W Shapes-Column; Family and Type: M_W Shapes-Column: HEA 200; Type: HEA 200; Type Id: 195138
Constraints - Base Offset: 0 m; Column Style: Vertical; Moves With Grids: yes; Top Offset: 0 m
Materials and Finishes - Structural Material: Steel, 45-345
Phasing - Phase Created: New Construction
AboveGround - AboveGround: yes
Name (M_W Shapes-Column:HEA 200:...) | In | Qto_ColumnBaseQuantities, Length (m) = Dimensions, Length (m) | OuterSurfaceArea (m2) | GrossVolume (m3) | NetVolume (m3) = Volume (m3) | Base Level = Level | Top Level | Column Location Mark | Weight (kg)
828789 | d_Fundaciones | 5.15 | 5.9918 | 0.0301297 | 0.0301309 | d_Fundaciones | Nivel 2 | C-3(-2.250) | 253.045
829942 | Nivel 2 | 4.25 | 4.94469 | 0.0248643 | 0.0248653 | Nivel 2 | Nivel 3 | C-3(-2.250) | 208.824
830024 | d_Fundaciones | 5.15 | 5.9918 | 0.0301297 | 0.0301309 | d_Fundaciones | Nivel 2 | C-9(2.250) | 253.045
830104 | Nivel 2 | 4.25 | 4.94469 | 0.0248643 | 0.0248653 | Nivel 2 | Nivel 3 | C-9(2.250) | 208.824
834150 | d_Fundaciones | 5.15 | 5.9918 | 0.0301297 | 0.0301309 | d_Fundaciones | Nivel 2 | C-6(2.250) | 253.045
834203 | Nivel 2 | 4.25 | 4.94469 | 0.0248643 | 0.0248653 | Nivel 2 | Nivel 3 | C-6(2.250) | 208.824
834601 | d_Fundaciones | 5.15 | 5.9918 | 0.0301297 | 0.0301309 | d_Fundaciones | Nivel 2 | G-6(2.250) | 253.045
835109 | Nivel 2 | 4.25 | 4.94469 | 0.0248643 | 0.0248653 | Nivel 2 | Nivel 3 | G-6(2.250) | 208.824
915617 | Nivel 1 | 8.5 | 9.88938 | 0.0497286 | 0.0497306 | Nivel 1 | Nivel 3 | C(2.580)-4(3.510) | 417.648 | Group: Model Group:CAJA ASCENSOR (members excluded):916446
915766 | Nivel 1 | 8.5 | 9.88938 | 0.0497286 | 0.0497306 | Nivel 1 | Nivel 3 | C(2.580)-4'(-3.140) | 417.648 | Group: Model Group:CAJA ASCENSOR (members excluded):916446
915863 | Nivel 1 | 8.5 | 9.88938 | 0.0497286 | 0.0497306 | Nivel 1 | Nivel 3 | C(0.335)-4(3.510) | 417.648 | Group: Model Group:CAJA ASCENSOR (members excluded):916446
915865 | Nivel 1 | 8.5 | 9.88938 | 0.0497286 | 0.0497306 | Nivel 1 | Nivel 3 | C(0.335)-4'(-3.140) | 417.648 | Group: Model Group:CAJA ASCENSOR (members excluded):916446
916589 | Nivel 1 | 8.5 | 9.88938 | 0.0497286 | 0.0497306 | Nivel 1 | Nivel 3 | C(2.580)-7''(-0.910) | 417.648 | Group: Model Group:CAJA ASCENSOR (members excluded):916610
916591 | Nivel 1 | 8.5 | 9.88938 | 0.0497286 | 0.0497306 | Nivel 1 | Nivel 3 | C(2.580)-7''(0.990) | 417.648 | Group: Model Group:CAJA ASCENSOR (members excluded):916610
916593 | Nivel 1 | 8.5 | 9.88938 | 0.0497286 | 0.0497306 | Nivel 1 | Nivel 3 | C(0.335)-7''(-0.910) | 417.648 | Group: Model Group:CAJA ASCENSOR (members excluded):916610
916595 | Nivel 1 | 8.5 | 9.88938 | 0.0497286 | 0.0497306 | Nivel 1 | Nivel 3 | C(0.335)-7''(0.990) | 417.648 | Group: Model Group:CAJA ASCENSOR (members excluded):916610

# IfcColumn: M_W Shapes-Column:HEA 280 (2)
In: d_Fundaciones
Type - PredefinedType: COLUMN; Material: Steel, 45-345
Type - Other - Category: Structural Columns; Family Name: M_W Shapes-Column
Type - Identity Data - Code Name: AISC 14.1; OmniClass Number: 23.25.30.11.14.11; OmniClass Title: Columns; Section Name Key: W10x33; Type Name: HEA 280
Type - Structural - Section Shape: 6
Type - Structural Analysis - Elastic Modulus strong axis: 0.000574 m3; Elastic Modulus weak axis: 0.000151 m3; Moment of Inertia strong axis: 0.0000712 m4; Moment of Inertia weak axis: 0.0000152 m4; Nominal Weight: 481.505 kg/s2; Perimeter: 1.27 m; Plastic Modulus strong axis: 0.000636 m3; Plastic Modulus weak axis: 0.000229 m3; Section Area: 0.00626 m2; Torsional Moment of Inertia: 2.43e-07 m4; Warping Constant: 2.12e-07 m6
Type - Structural Section Geometry - Centroid Horizontal: 0.14 m; Centroid Vertical: 0.14 m; Flange Thickness: 0.011 m; Height: 0.28 m; Web Fillet: 0.0127 m; Web Thickness: 0.00737 m; Width: 0.28 m
Type - Pset_ColumnCommon - LoadBearing: yes
Classification: B1031 (FEMAP58); Material: Steel, 45-345; Steel, 45-345
Qto_ColumnBaseQuantities - Length: 5.15 m; CrossSectionArea: 0.00820004 m2; OuterSurfaceArea: 8.4638 m2; GrossVolume: 0.0422302 m3; NetVolume: 0.0422312 m3
Pset_ColumnCommon - IsExternal: no; Reference: M_W Shapes-Column:HEA 280
Pset_EnvironmentalImpactIndicators - Reference: M_W Shapes-Column:HEA 280; sets with these values: 2
Other - Family: M_W Shapes-Column; Family and Type: M_W Shapes-Column: HEA 280; Type: HEA 280; Type Id: 902532
Constraints - Base Level: d_Fundaciones; Base Offset: 0 m; Column Style: Vertical; Level: d_Fundaciones; Moves With Grids: yes; Top Level: Nivel 2; Top Offset: 0 m
Dimensions - Length: 5.15 m; Volume: 0.0422312 m3
Materials and Finishes - Structural Material: Steel, 45-345
Phasing - Phase Created: New Construction
Structural - Weight: 253.045 kg
AboveGround - AboveGround: yes
Name (M_W Shapes-Column:HEA 280:...) | Column Location Mark
902489 | D-4'
902650 | D(-1.950)-4'

# IfcGrid (14)
AboveGround - AboveGround: yes
Name | In
2 x Default Grid | Subterráneo 1
2 x Default Grid | Base MHA ASC
2 x Default Grid | d_Fundaciones
2 x Default Grid | Nivel 1
2 x Default Grid | Nivel 2
2 x Default Grid | Nivel 3
2 x Default Grid | Nivel 4

# IfcGroup: Model Group:CAJA ASCENSOR (2)
Other - Category: Model Groups; Family: Model Group; Family and Type: Model Group: CAJA ASCENSOR; Type: CAJA ASCENSOR; Type Id: 916447
Constraints - Origin Level Offset: 0 m; Reference Level: Base MHA ASC
Other(Type) - Category: Model Groups; Family Name: Model Group
Identity Data(Type) - Type Name: CAJA ASCENSOR
Name (Model Group:CAJA ASCENSOR (members excluded):...)
916446
916610

# IfcMember: M_Concrete-Square-Column:400 x 400mm, M_Concrete-Square-Column:400 x 400mm:781176
In: Nivel 2
Type - PredefinedType: BRACE; Material: HA
Type - Other - Category: Structural Columns; Family Name: M_Concrete-Square-Column
Type - Data - Sup. en planta: 0.16 m2
Type - Dimensions - b: 0.4 m
Type - Identity Data - OmniClass Number: 23.25.30.11.14.11; OmniClass Title: Columns; Type Name: 400 x 400mm
Type - Structural - Section Shape: 0
Type - Pset_ColumnCommon - LoadBearing: yes
Classification: B104 (FEMAP58); Material: HA; HA
Qto_ColumnBaseQuantities - Length: 4.1 m; CrossSectionArea: 0.16 m2; OuterSurfaceArea: 6.56 m2; GrossVolume: 0.656 m3; NetVolume: 0.656 m3
Pset_ColumnCommon - Reference: M_Concrete-Square-Column:400 x 400mm; IsExternal: no
Pset_EnvironmentalImpactIndicators - Reference: M_Concrete-Square-Column:400 x 400mm; sets with these values: 2
Other - Family: M_Concrete-Square-Column; Family and Type: M_Concrete-Square-Column: 400 x 400mm; Type: 400 x 400mm; Type Id: 227260
Constraints - Base Offset: 0 m; Column Style: Vertical; Moves With Grids: yes; Room Bounding: yes; Top Offset: 0 m; Level: Nivel 2; Base Level: Nivel 2; Top Level: Nivel 3; Column Location Mark: E-2
Dimensions - Length: 4.25 m; Volume: 0.656 m3
Materials and Finishes - Structural Material: HA
Phasing - Phase Created: New Construction
Structural - Rebar Cover - Other Faces: Rebar Cover 1 <25 mm>
AboveGround - AboveGround: yes

# IfcMember: M_Double C-Channel:doble T HEB 180 (64)
Type - PredefinedType: BRACE; Material: Steel, 45-345
Type - Other - Category: Structural Framing; Family Name: M_Double C-Channel
Type - Dimensions - bf: 0.09 m; d: 0.18 m; Space: 0 m; tf: 0.0165 m; tw: 0.0182 m
Type - Identity Data - Assembly Code: B10; Assembly Description: Superstructure; OmniClass Number: 23.25.30.11.14.14; OmniClass Title: Beams; Type Name: doble T HEB 180
Type - Structural - Section Shape: 0; A: 0.019 m2; W: 1.46
Type - Pset_BeamCommon - LoadBearing: yes
Classification: B10 Superstructure (Uniformat); B1033 (FEMAP58); Material: Steel, 45-345; Steel, 45-345
Pset_BeamCommon - IsExternal: no; Roll: 0 deg; Reference: M_Double C-Channel:doble T HEB 180
Pset_EnvironmentalImpactIndicators - Reference: M_Double C-Channel:doble T HEB 180; sets with these values: 2
Qto_BeamBaseQuantities - CrossSectionArea: 0.00601286 m2
Other - Family: M_Double C-Channel; Family and Type: M_Double C-Channel: doble T HEB 180; Type: doble T HEB 180; Type Id: 826508
Constraints - Cross-Section Rotation: 0 deg
Materials and Finishes - Structural Material: Steel, 45-345
Phasing - Phase Created: New Construction
Structural - Stick Symbol Location: Center of Geometry; Weight: 0 kg
Geometric Position - End Extension: 0 m; Join Status: Both joins enabled; Start Extension: 0 m; y Justification: Origin; yz Justification: Uniform; z Justification: Top; z Offset Value: 0 m
AboveGround - AboveGround: yes
Name (M_Double C-Channel:doble T HEB 180:...) | In | Span (m) = Qto_BeamBaseQuantities, Length (m) = Dimensions, Length (m) | Slope (deg) | OuterSurfaceArea (m2) | GrossSurfaceArea (m2) | NetSurfaceArea (m2) | GrossVolume (m3) | NetVolume (m3) = Volume (m3) | Start Level Offset (m) | End Level Offset (m) | Reference Level | Reference Level Elevation (m) | End Attachment Type | Start Attachment Type | Structural Usage | Cut Length (m) | End Join Cutback (m) | Start Join Cutback (m) | y Offset Value (m)
826207 | Nivel 1 | 10.2821 | 54.3004 | 6.08924 | 6.10126 | 12.2025 | 0.0560445 | 0.112089 | 0 | 8.35 | Nivel 1 | -0.05 | End Elevation | End Elevation | Primary | 9.32077 | 0.0127 | 0.0127 | 0.11
826867 | Nivel 1 | 10.2821 | 54.3004 | 6.10956 | 6.12159 | 12.2432 | 0.0562316 | 0.112463 | 0 | 8.35 | Nivel 1 | -0.05 | End Elevation | End Elevation | Primary | 9.35188 | -0.0184148 | 0.0127 | -0.11
827679 | Nivel 1 | 9.63133 | 60.1075 | 5.54662 | 5.55865 | 11.1173 | 0.0510503 | 0.102101 | 0 | 8.35 | Nivel 1 | -0.05 | End Elevation | End Elevation | Primary | 8.49019 | 0.0127 | 0.0127 | 0.11
827878 | Nivel 1 | 9.63133 | 60.1075 | 5.54662 | 5.55865 | 11.1173 | 0.0510503 | 0.102101 | 0 | 8.35 | Nivel 1 | -0.05 | End Elevation | End Elevation | Primary | 8.49019 | 0.0127 | 0.0127 | -0.11
828574 | Nivel 1 | 11.0255 | 49.2296 | 6.64982 | 6.66185 | 13.3237 | 0.061204 | 0.122408 | 0 | 8.35 | Nivel 1 | -0.05 | End Elevation | End Elevation | Primary | 10.1789 | 0.0127 | 0.0127 | 0.11
828576 | Nivel 1 | 11.0255 | 49.2296 | 6.64982 | 6.66185 | 13.3237 | 0.061204 | 0.122408 | 0 | 8.35 | Nivel 1 | -0.05 | End Elevation | End Elevation | Primary | 10.1789 | 0.0127 | 0.0127 | -0.11
828705 | Nivel 1 | 11.0255 | 49.2296 | 6.64982 | 6.66185 | 13.3237 | 0.061204 | 0.122408 | 0 | 8.35 | Nivel 1 | -0.05 | End Elevation | End Elevation | Primary | 10.1789 | 0.0127 | 0.0127 | -0.11
828738 | Nivel 1 | 11.0255 | 49.2296 | 6.64982 | 6.66185 | 13.3237 | 0.061204 | 0.122408 | 0 | 8.35 | Nivel 1 | -0.05 | End Elevation | End Elevation | Primary | 10.1789 | 0.0127 | 0.0127 | 0.11
828957 | Nivel 1 | 4.12651 | 62.193 | 2.17021 | 2.18224 | 4.36447 | 0.0199743 | 0.0399487 | 0 | 3.65 | Nivel 1 | -0.05 |  | End Elevation | Primary | 3.32193 | 0.0127 | 0.0127 | 0
829441 | Nivel 1 | 4.08082 | 63.4349 | 2.27437 | 2.28639 | 4.57279 | 0.020933 | 0.041866 | 0 | 3.65 | Nivel 1 | -0.05 |  | End Elevation | Primary | 3.48137 | 0.0127 | 0.0127 | 0
833518 | Nivel 1 | 11.0255 | 49.2296 | 6.64982 | 6.66185 | 13.3237 | 0.061204 | 0.122408 | 0 | 8.35 | Nivel 1 | -0.05 | End Elevation | End Elevation | Primary | 10.1789 | 0.0127 | 0.0127 | 0.11
833576 | Nivel 1 | 11.0255 | 49.2296 | 6.64982 | 6.66185 | 13.3237 | 0.061204 | 0.122408 | 0 | 8.35 | Nivel 1 | -0.05 | End Elevation | End Elevation | Primary | 10.1789 | 0.0127 | 0.0127 | 0.11
833706 | Nivel 1 | 11.0255 | 49.2296 | 6.64982 | 6.66185 | 13.3237 | 0.061204 | 0.122408 | 0 | 8.35 | Nivel 1 | -0.05 | End Elevation | End Elevation | Primary | 10.1789 | 0.0127 | 0.0127 | 0.11
833774 | Nivel 1 | 11.0255 | 49.2296 | 6.64982 | 6.66185 | 13.3237 | 0.061204 | 0.122408 | 0 | 8.35 | Nivel 1 | -0.05 | End Elevation | End Elevation | Primary | 10.1789 | 0.0127 | 0.0127 | 0.11
833869 | Nivel 1 | 11.0255 | 49.2296 | 6.64982 | 6.66185 | 13.3237 | 0.061204 | 0.122408 | 0 | 8.35 | Nivel 1 | -0.05 | End Elevation | End Elevation | Primary | 10.1789 | 0.0127 | 0.0127 | -0.11
833902 | Nivel 1 | 11.0255 | 49.2296 | 6.64982 | 6.66185 | 13.3237 | 0.061204 | 0.122408 | 0 | 8.35 | Nivel 1 | -0.05 | End Elevation | End Elevation | Primary | 10.1789 | 0.0127 | 0.0127 | -0.11
833935 | Nivel 1 | 11.0255 | 49.2296 | 6.64982 | 6.66185 | 13.3237 | 0.061204 | 0.122408 | 0 | 8.35 | Nivel 1 | -0.05 | End Elevation | End Elevation | Primary | 10.1789 | 0.0127 | 0.0127 | -0.11
833968 | Nivel 1 | 11.0255 | 49.2296 | 6.64982 | 6.66185 | 13.3237 | 0.061204 | 0.122408 | 0 | 8.35 | Nivel 1 | -0.05 | End Elevation | End Elevation | Primary | 10.1789 | 0.0127 | 0.0127 | -0.11
834669 | Nivel 1 | 9.63133 | 60.1075 | 5.54662 | 5.55865 | 11.1173 | 0.0510503 | 0.102101 | 0 | 8.35 | Nivel 1 | -0.05 | End Elevation | End Elevation | Other | 8.49019 | 0.0127 | 0.0127 | 0.11
834737 | Nivel 1 | 9.63133 | 60.1075 | 5.54662 | 5.55865 | 11.1173 | 0.0510503 | 0.102101 | 0 | 8.35 | Nivel 1 | -0.05 | End Elevation | End Elevation | Other | 8.49019 | 0.0127 | 0.0127 | -0.11
834941 | Nivel 1 | 9.35381 | 65.8151 | 5.22308 | 5.2351 | 10.4702 | 0.0480725 | 0.096145 | -0.18281 | 8.35 | Nivel 1 | -0.05 | End Elevation | End Elevation | Primary | 7.99494 | 0.0127 | 0.0127 | 0.11
835039 | Nivel 1 | 9.15341 | 65.8151 | 5.22308 | 5.2351 | 10.4702 | 0.0480725 | 0.096145 | 0 | 8.35 | Nivel 1 | -0.05 | End Elevation | End Elevation | Primary | 7.99494 | 0.0127 | 0.0127 | -0.11
835489 | Nivel 1 | 9.63133 | 60.1075 | 5.56695 | 5.57898 | 11.158 | 0.0512374 | 0.102475 | 0 | 8.35 | Nivel 1 | -0.05 | End Elevation | End Elevation | Primary | 8.52131 | -0.0184148 | 0.0127 | -0.11
835582 | Nivel 1 | 9.63133 | 60.1075 | 5.56695 | 5.57898 | 11.158 | 0.0512374 | 0.102475 | 0 | 8.35 | Nivel 1 | -0.05 | End Elevation | End Elevation | Primary | 8.52131 | -0.0184148 | 0.0127 | 0.11
835637 | Nivel 1 | 10.2821 | 54.3004 | 6.10956 | 6.12159 | 12.2432 | 0.0562316 | 0.112463 | 0 | 8.35 | Nivel 1 | -0.05 | End Elevation | End Elevation | Primary | 9.35188 | -0.0184148 | 0.0127 | 0.11
835805 | Nivel 1 | 10.2821 | 54.3004 | 6.10956 | 6.12159 | 12.2432 | 0.0562316 | 0.112463 | 0 | 8.35 | Nivel 1 | -0.05 | End Elevation | End Elevation | Primary | 9.35188 | -0.0184148 | 0.0127 | -0.11
835842 | Nivel 2 | 4.66563 | 65.6323 | 2.45515 | 2.46718 | 4.93435 | 0.0225969 | 0.0451938 | 0 | 4.25 | Nivel 2 | 4.2 | End Elevation |  | Primary | 3.75809 | 0.0127 | 0.0127 | 0
835910 | Nivel 2 | 4.62527 | 66.7607 | 2.56566 | 2.57769 | 5.15538 | 0.023614 | 0.0472281 | 0 | 4.25 | Nivel 2 | 4.2 | End Elevation |  | Primary | 3.92725 | 0.0127 | 0.0127 | 0
899792 | Nivel 1 | 4.36835 | 56.6737 | 2.42058 | 2.43261 | 4.86521 | 0.0222787 | 0.0445574 | 0 | 3.65 | Nivel 1 | -0.05 |  | End Elevation | Primary | 3.70517 | 0.0127 | 0.0127 | 0
899794 | Nivel 1 | 4.36835 | 56.6737 | 2.42058 | 2.43261 | 4.86521 | 0.0222787 | 0.0445574 | 0 | 3.65 | Nivel 1 | -0.05 |  | End Elevation | Primary | 3.70517 | 0.0127 | 0.0127 | 0
899796 | Nivel 2 | 4.88083 | 60.5463 | 2.69808 | 2.71011 | 5.42022 | 0.0248328 | 0.0496656 | 0 | 4.25 | Nivel 2 | 4.2 | End Elevation |  | Primary | 4.12994 | 0.0127 | 0.0127 | 0
899798 | Nivel 2 | 4.88083 | 60.5463 | 2.69808 | 2.71011 | 5.42022 | 0.0248328 | 0.0496656 | 0 | 4.25 | Nivel 2 | 4.2 | End Elevation |  | Primary | 4.12994 | 0.0127 | 0.0127 | 0
899943 | Nivel 1 | 4.36835 | 56.6737 | 2.42058 | 2.43261 | 4.86521 | 0.0222787 | 0.0445574 | 0 | 3.65 | Nivel 1 | -0.05 |  | End Elevation | Primary | 3.70517 | 0.0127 | 0.0127 | 0
899945 | Nivel 1 | 4.36835 | 56.6737 | 2.42058 | 2.43261 | 4.86521 | 0.0222787 | 0.0445574 | 0 | 3.65 | Nivel 1 | -0.05 |  | End Elevation | Primary | 3.70517 | 0.0127 | 0.0127 | 0
899947 | Nivel 2 | 4.88083 | 60.5463 | 2.69808 | 2.71011 | 5.42022 | 0.0248328 | 0.0496656 | 0 | 4.25 | Nivel 2 | 4.2 | End Elevation |  | Primary | 4.12994 | 0.0127 | 0.0127 | 0
899949 | Nivel 2 | 4.88083 | 60.5463 | 2.69808 | 2.71011 | 5.42022 | 0.0248328 | 0.0496656 | 0 | 4.25 | Nivel 2 | 4.2 | End Elevation |  | Primary | 4.12994 | 0.0127 | 0.0127 | 0
899970 | Nivel 1 | 4.36835 | 56.6737 | 2.42058 | 2.43261 | 4.86521 | 0.0222787 | 0.0445574 | 0 | 3.65 | Nivel 1 | -0.05 |  | End Elevation | Primary | 3.70517 | 0.0127 | 0.0127 | 0
899972 | Nivel 1 | 4.36835 | 56.6737 | 2.42058 | 2.43261 | 4.86521 | 0.0222787 | 0.0445574 | 0 | 3.65 | Nivel 1 | -0.05 |  | End Elevation | Primary | 3.70517 | 0.0127 | 0.0127 | 0
899974 | Nivel 2 | 4.88083 | 60.5463 | 2.69808 | 2.71011 | 5.42022 | 0.0248328 | 0.0496656 | 0 | 4.25 | Nivel 2 | 4.2 | End Elevation |  | Primary | 4.12994 | 0.0127 | 0.0127 | 0
899976 | Nivel 2 | 4.88083 | 60.5463 | 2.69808 | 2.71011 | 5.42022 | 0.0248328 | 0.0496656 | 0 | 4.25 | Nivel 2 | 4.2 | End Elevation |  | Primary | 4.12994 | 0.0127 | 0.0127 | 0
900017 | Nivel 1 | 4.12651 | 62.193 | 2.17021 | 2.18224 | 4.36447 | 0.0199743 | 0.0399487 | 0 | 3.65 | Nivel 1 | -0.05 |  | End Elevation | Primary | 3.32193 | 0.0127 | 0.0127 | 0
900019 | Nivel 1 | 4.08082 | 63.4349 | 2.27437 | 2.28639 | 4.57279 | 0.020933 | 0.041866 | 0 | 3.65 | Nivel 1 | -0.05 |  | End Elevation | Primary | 3.48137 | 0.0127 | 0.0127 | 0
900021 | Nivel 2 | 4.66563 | 65.6323 | 2.45515 | 2.46718 | 4.93435 | 0.0225969 | 0.0451938 | 0 | 4.25 | Nivel 2 | 4.2 | End Elevation |  | Primary | 3.75809 | 0.0127 | 0.0127 | 0
900023 | Nivel 2 | 4.62527 | 66.7607 | 2.56566 | 2.57769 | 5.15538 | 0.023614 | 0.0472281 | 0 | 4.25 | Nivel 2 | 4.2 | End Elevation |  | Primary | 3.92725 | 0.0127 | 0.0127 | 0
900047 | Nivel 1 | 4.12651 | 62.193 | 2.17021 | 2.18224 | 4.36447 | 0.0199743 | 0.0399487 | 0 | 3.65 | Nivel 1 | -0.05 |  | End Elevation | Primary | 3.32193 | 0.0127 | 0.0127 | 0
900049 | Nivel 1 | 4.08082 | 63.4349 | 2.27437 | 2.28639 | 4.57279 | 0.020933 | 0.041866 | 0 | 3.65 | Nivel 1 | -0.05 |  | End Elevation | Primary | 3.48137 | 0.0127 | 0.0127 | 0
900051 | Nivel 2 | 4.66563 | 65.6323 | 2.45515 | 2.46718 | 4.93435 | 0.0225969 | 0.0451938 | 0 | 4.25 | Nivel 2 | 4.2 | End Elevation |  | Primary | 3.75809 | 0.0127 | 0.0127 | 0
900053 | Nivel 2 | 4.62527 | 66.7607 | 2.56566 | 2.57769 | 5.15538 | 0.023614 | 0.0472281 | 0 | 4.25 | Nivel 2 | 4.2 | End Elevation |  | Primary | 3.92725 | 0.0127 | 0.0127 | 0
911798 | Nivel 1 | 3.77349 | 70.8451 | 2.45691 | 2.46894 | 4.93788 | 0.0226131 | 0.0452262 | 4.36496 | 7.92953 | Nivel 1 | -0.05 |  |  | Primary | 3.76079 |  | 0.0127 | 0.115
913260 | Nivel 1 | 3.77349 | 69.4446 | 2.45691 | 2.46894 | 4.93788 | 0.0226131 | 0.0452262 | 4.36496 | 7.8982 | Nivel 1 | -0.05 |  |  | Primary | 3.76079 |  | 0.0127 | -0.115
913624 | Nivel 1 | 3.86393 | 70.8451 | 2.31346 | 2.32549 | 4.65098 | 0.0212928 | 0.0425856 | 3.65 | 0 | Nivel 1 | -0.05 | End Elevation |  | Primary | 3.54121 | 0.0349362 |  | -0.115
913747 | Nivel 1 | 3.86393 | 72.154 | 2.28256 | 2.29459 | 4.58917 | 0.0210084 | 0.0420168 | 3.64437 | -0.0336391 | Nivel 1 | -0.05 | End Elevation |  | Primary | 3.49391 | 0.0261583 |  | 0.115
914055 | Nivel 1 | 3.77349 | 70.8451 | 2.45691 | 2.46894 | 4.93788 | 0.0226131 | 0.0452262 | 4.36496 | 7.92953 | Nivel 1 | -0.05 |  |  | Primary | 3.76079 |  | 0.0127 | -0.115
914057 | Nivel 1 | 3.77349 | 69.4446 | 2.45691 | 2.46894 | 4.93788 | 0.0226131 | 0.0452262 | 4.36496 | 7.8982 | Nivel 1 | -0.05 |  |  | Primary | 3.76079 |  | 0.0127 | 0.115
914102 | Nivel 1 | 3.86393 | 70.8451 | 2.31346 | 2.32549 | 4.65098 | 0.0212928 | 0.0425856 | 3.65 | 0 | Nivel 1 | -0.05 | End Elevation |  | Primary | 3.54121 | 0.0349362 |  | 0.115
914104 | Nivel 1 | 3.86393 | 72.154 | 2.28257 | 2.29459 | 4.58919 | 0.0210084 | 0.0420169 | 3.64437 | -0.0336391 | Nivel 1 | -0.05 | End Elevation |  | Primary | 3.49392 | 0.0261583 |  | -0.115
914792 | Nivel 1 | 3.67765 | 66.3295 | 2.3943 | 2.40633 | 4.81266 | 0.0220368 | 0.0440737 | 4.47417 | 7.84242 | Nivel 1 | -0.05 |  |  | Primary | 3.66495 |  | 0.0127 | 0.115
914794 | Nivel 1 | 3.67839 | 66.3295 | 2.39478 | 2.40681 | 4.81362 | 0.0220413 | 0.0440826 | 4.47417 | 7.84309 | Nivel 1 | -0.05 |  |  | Primary | 3.66569 |  | 0.0127 | -0.115
914796 | Nivel 1 | 3.86393 | 69.3701 | 2.36396 | 2.37599 | 4.75197 | 0.0217576 | 0.0435152 | 3.67461 | 0.0584529 | Nivel 1 | -0.05 | End Elevation |  | Primary | 3.6185 | 0.0349362 |  | -0.115
914798 | Nivel 1 | 3.86393 | 69.3701 | 2.3693 | 2.38133 | 4.76265 | 0.0218067 | 0.0436134 | 3.67404 | 0.0578877 | Nivel 1 | -0.05 | End Elevation |  | Primary | 3.62668 | 0.0261583 |  | 0.115
915004 | Nivel 1 | 3.86393 | 69.3701 | 2.36396 | 2.37599 | 4.75197 | 0.0217576 | 0.0435152 | 3.67461 | 0.0584529 | Nivel 1 | -0.05 | End Elevation |  | Primary | 3.6185 | 0.0349362 |  | 0.115
915006 | Nivel 1 | 3.86393 | 69.3701 | 2.3693 | 2.38133 | 4.76265 | 0.0218067 | 0.0436134 | 3.67404 | 0.0578877 | Nivel 1 | -0.05 | End Elevation |  | Primary | 3.62668 | 0.0261583 |  | -0.115
915069 | Nivel 1 | 3.67765 | 66.3295 | 2.3943 | 2.40633 | 4.81266 | 0.0220368 | 0.0440737 | 4.47417 | 7.84242 | Nivel 1 | -0.05 |  |  | Primary | 3.66495 |  | 0.0127 | -0.115
915071 | Nivel 1 | 3.67839 | 66.3295 | 2.39478 | 2.40681 | 4.81362 | 0.0220413 | 0.0440826 | 4.47417 | 7.84309 | Nivel 1 | -0.05 |  |  | Primary | 3.66569 |  | 0.0127 | 0.115

# IfcOpeningElement (27)
PredefinedType: OPENING
Pset_EnvironmentalImpactIndicators - sets with these values: 2
Name | In | Height (m) | Width (m) | Reference | Category | Base Constraint | Base Offset (m) | Top Constraint | Top Offset (m) | Unconnected Height (m) | Phase Created
Floor:Radier - 100mm:514839 | Nivel 1 | 1.50017 | 1.5 | Floor:Radier - 100mm | Lines: <Sketch> | Other - Concrete Cantilever: 0 m; Steel Cantilever: 0 m; Constraints - Defines Constant Height: no; Defines Slope: no; Offset From Base: 0 m; Dimensions - Length: 1.5 m; Slope: 0.0833333
Floor:Losa colaborante 150mm:809659 | Nivel 2 | 0.38 | 1.54975 | Floor:Losa colaborante 150mm | Shaft Openings | Nivel 2 | -0.177117 | Up to level: Nivel 3 | -4.04724 | 0.379876 | New Construction
Floor:Losa colaborante 150mm:809659 | Nivel 2 | 0.36 | 0.9 | Floor:Losa colaborante 150mm | Shaft Openings | Nivel 2 | -0.171089 | Up to level: Nivel 3 | -4.11221 | 0.308879 | New Construction
Floor:Losa colaborante 150mm:809659 | Nivel 2 | 0.5 | 1.5 | Floor:Losa colaborante 150mm | Shaft Openings | Nivel 2 | -0.223006 | Up to level: Nivel 3 | -4.21476 | 0.258248 | New Construction
Floor:Losa colaborante 150mm:809659 | Nivel 2 | 0.4 | 0.88 | Floor:Losa colaborante 150mm | Shaft Openings | Nivel 2 | -0.181176 | Up to level: Nivel 3 | -4.12763 | 0.303541 | New Construction
Floor:Losa colaborante 150mm:809659 | Nivel 3 | 1.5 | 0.8 | Floor:Losa colaborante 150mm | Shaft Openings | Nivel 3 | -0.177902 | Up to level: Nivel 4 | -3.82187 | 0.606037 | New Construction
4 x Floor:Losa colaborante 150mm:809659 | Nivel 3 | 0.3 | 0.3 | Floor:Losa colaborante 150mm | Shaft Openings | Nivel 3 | -0.19 | Up to level: Nivel 4 | -4.2 | 0.24 | New Construction
Floor:Losa colaborante 150mm:809659 | Nivel 2 | 0.36 | 0.9 | Floor:Losa colaborante 150mm | Shaft Openings | Nivel 2 | -0.22096 | Up to level: Nivel 3 | -4.2 | 0.27096 | New Construction
Floor:Losa colaborante 150mm:809659 | Nivel 2 | 0.26 | 0.26 | Floor:Losa colaborante 150mm | Shaft Openings | Nivel 2 | -0.183415 | Up to level: Nivel 3 | -4.20418 | 0.229233 | New Construction
Floor:Losa colaborante 150mm:809659 | Nivel 2 | 3.04 | 0.504374 | Floor:Losa colaborante 150mm | Shaft Openings | Nivel 2 | -0.195769 | Up to level: Nivel 3 | -4.2 | 0.245769 | New Construction
Floor:Losa colaborante 150mm:809659 | Nivel 2 | 2.759 | 2.07899 | Floor:Losa colaborante 150mm | Shaft Openings | Nivel 2 | -0.221425 | Up to level: Nivel 3 | -4.2 | 0.271425 | New Construction
Floor:Losa colaborante 150mm:809659 | Nivel 2 | 2.764 | 1.6 | Floor:Losa colaborante 150mm | Shaft Openings | Nivel 2 | -0.303795 | Up to level: Nivel 3 | -4.2 | 0.353795 | New Construction
Floor:Losa colaborante 150mm:809659 | Nivel 2 | 0.26006 | 0.46 | Floor:Losa colaborante 150mm | Shaft Openings | Nivel 2 | -0.161903 | Up to level: Nivel 3 | -4.2 | 0.211903 | New Construction
Floor:Losa colaborante 150mm:809659 | Nivel 2 | 0.26 | 0.9 | Floor:Losa colaborante 150mm | Shaft Openings | Nivel 2 | -0.177136 | Up to level: Nivel 3 | -4.2 | 0.227136 | New Construction
Floor:Losa colaborante 150mm:809659 | Nivel 2 | 0.315516 | 1.00338 | Floor:Losa colaborante 150mm | Shaft Openings | Nivel 2 | -0.180978 | Up to level: Nivel 3 | -4.2 | 0.230978 | New Construction
Floor:Losa colaborante 150mm:809659 | Nivel 2 | 0.26 | 0.4 | Floor:Losa colaborante 150mm | Shaft Openings | Nivel 2 | -0.179667 | Up to level: Nivel 3 | -3.95479 | 0.474879 | New Construction
Floor:Losa colaborante 150mm:809659 | Nivel 2 | 0.859859 | 1.92551 | Floor:Losa colaborante 150mm | Shaft Openings | Nivel 2 | -0.19 | Up to level: Nivel 3 | -4.2 | 0.24 | New Construction
Floor:Losa colaborante 150mm:809659 | Nivel 3 | 0.25 | 0.4 | Floor:Losa colaborante 150mm | Shaft Openings | Nivel 3 | -0.19 | Up to level: Nivel 4 | -4.2 | 0.24 | New Construction
Floor:Losa colaborante 150mm:809659 | Nivel 3 | 1.3 | 2.08704 | Floor:Losa colaborante 150mm | Shaft Openings | Nivel 3 | -0.19 | Up to level: Nivel 4 | -4.2 | 0.24 | New Construction
Floor:Losa colaborante 150mm:809659 | Nivel 3 | 0.4 | 1.53574 | Floor:Losa colaborante 150mm | Shaft Openings | Nivel 2 | 4.06527 | Up to level: Nivel 3 | 0.024032 | 0.208761 | New Construction
Floor:Losa colaborante 150mm:809659 | Nivel 3 | 0.11 | 0.11 | Floor:Losa colaborante 150mm | Shaft Openings | Nivel 2 | 0 | Up to level: Nivel 3 | 1 | 5.25 | New Construction
Floor:Losa colaborante 150mm:809659 | Nivel 3 | 0.5 | 0.66 | Floor:Losa colaborante 150mm | Shaft Openings | Nivel 3 | -0.19 | Up to level: Nivel 4 | -4.2 | 0.24 | New Construction
Floor:Losa colaborante 150mm:809659 | Nivel 3 | 1.45 | 0.85 | Floor:Losa colaborante 150mm | Shaft Openings | Nivel 3 | -0.19 | Up to level: Nivel 4 | -4.2 | 0.24 | New Construction
Foundation Slab:LosaFundacion 600mm:839035 | d_Fundaciones | 1.5 | 1.5 | Foundation Slab:LosaFundacion 600mm | Lines: <Sketch> | Other - Concrete Cantilever: 0 m; Steel Cantilever: 0 m; Constraints - Defines Constant Height: no; Defines Slope: no; Offset From Base: 0 m; Dimensions - Length: 1.5 m; Slope: 0.0833333

# IfcRailing: Railing:Commercial - Glass w Fixings (2)
In: Nivel 2
Type - Other - Category: Railings; Family Name: Railing
Type - Construction - Angled Joins: Add Vertical/Horizontal Segments; Baluster Offset: 0 m; Landing Height Adjustment: 0 m; Rail Connections: Trim; Railing Height: 1.1 m; Tangent Joins: Extend Rails to Meet; Use Landing Height Adjustment: no
Type - Identity Data - Type Name: Commercial - Glass w Fixings
Type - Top Rail - Height: 1.1 m; Type: Steel - Elipse - 50x35mm; Use Top Rail: yes
Classification: C (FEMAP58); Material: Glass, Metal - Steel, <Unnamed>
Pset_EnvironmentalImpactIndicators - Reference: Railing:Commercial - Glass w Fixings
Pset_RailingCommon - IsExternal: no; Reference: Railing:Commercial - Glass w Fixings; Height: 1.1 m
Qto_RailingBaseQuantities - sets with these values: 2
Other - Family: Railing; Family and Type: Railing: Commercial - Glass w Fixings; Type: Commercial - Glass w Fixings; Type Id: 880283
Constraints - Base Offset: 0 m; Offset from Path: 0 m
Phasing - Phase Created: New Construction
AboveGround - AboveGround: yes
Name (Railing:Commercial - Glass w Fixings:...) | Length (m)
867462 | 13.8388
867629 | 14.1462

# IfcSlab: Borde01:Borde01, Borde01:Borde01:882370
In: Nivel 2
Type - PredefinedType: FLOOR; Material: HA
Type - Other - Category: Floors; Family Name: Borde01
Type - Identity Data - Type Name: Borde01
Type - Materials and Finishes - Structural Material: HA
Pset_EnvironmentalImpactIndicators - Reference: Borde01:Borde01; sets with these values: 2
Pset_SlabCommon - IsExternal: no; Reference: Borde01:Borde01; PitchAngle: 2.98923 deg
Qto_SlabBaseQuantities - Depth: 5.79571 m; Perimeter: 1.62268 m; GrossArea: 0.1125 m2; NetArea: 3.25337 m2; GrossVolume: 0.652017 m3; NetVolume: 0.652017 m3
Other - Family: Borde01; Family and Type: Borde01: Borde01; Type: Borde01; Type Id: 882368
Constraints - Room Bounding: yes; Level: Nivel 2; Moves With Nearby Elements: no
Dimensions - Area: 3.25337 m2; Volume: 0.652017 m3
Phasing - Phase Created: New Construction
Structural - Rebar Cover: Rebar Cover 1 <25 mm>
AboveGround - AboveGround: yes

# IfcSlab: Borde02:Borde02, Borde02:Borde02:882422
In: Nivel 2
Type - PredefinedType: FLOOR; Material: HA
Type - Other - Category: Floors; Family Name: Borde02
Type - Identity Data - Type Name: Borde02
Type - Materials and Finishes - Structural Material: HA
Pset_EnvironmentalImpactIndicators - Reference: Borde02:Borde02; sets with these values: 2
Pset_SlabCommon - IsExternal: no; Reference: Borde02:Borde02
Qto_SlabBaseQuantities - GrossArea: 6.9089 m2; NetArea: 6.9089 m2; NetVolume: 0.941338 m3
Other - Family: Borde02; Family and Type: Borde02: Borde02; Type: Borde02; Type Id: 882420
Constraints - Room Bounding: yes; Level: Nivel 2; Moves With Nearby Elements: no
Dimensions - Area: 6.9089 m2; Volume: 0.941338 m3
Phasing - Phase Created: New Construction
Structural - Rebar Cover: Rebar Cover 1 <25 mm>
AboveGround - AboveGround: yes

# IfcSlab: Borde03:Borde03, Borde03:Borde03:882464
In: Nivel 2
Type - PredefinedType: FLOOR; Material: HA
Type - Other - Category: Floors; Family Name: Borde03
Type - Identity Data - Type Name: Borde03
Type - Materials and Finishes - Structural Material: HA
Pset_EnvironmentalImpactIndicators - Reference: Borde03:Borde03; sets with these values: 2
Pset_SlabCommon - IsExternal: no; Reference: Borde03:Borde03; PitchAngle: 2.98923 deg
Qto_SlabBaseQuantities - Depth: 13.8467 m; Perimeter: 1.62268 m; GrossArea: 0.1125 m2; NetArea: 7.88519 m2; GrossVolume: 1.55775 m3; NetVolume: 1.55775 m3
Other - Family: Borde03; Family and Type: Borde03: Borde03; Type: Borde03; Type Id: 882462
Constraints - Room Bounding: yes; Level: Nivel 2; Moves With Nearby Elements: no
Dimensions - Area: 7.88519 m2; Volume: 1.55775 m3
Phasing - Phase Created: New Construction
Structural - Rebar Cover: Rebar Cover 1 <25 mm>
AboveGround - AboveGround: yes

# IfcSlab: Floor:Losa HA 150mm, Floor:Losa HA 150mm:822723
In: Nivel 2
Type - PredefinedType: FLOOR; Material: HA
Type - Other - Category: Floors; Family Name: Floor
Type - Construction - Function: Interior; Default Thickness: 0.15 m
Type - Graphics - Coarse Scale Fill Color: 0
Type - Identity Data - Type Name: Losa HA 150mm
Type - Materials and Finishes - Structural Material: HA
Type - Analytical Properties - Absorptance: 0.1; Roughness: 1
Classification: C (FEMAP58)
Pset_EnvironmentalImpactIndicators - Reference: Floor:Losa HA 150mm; sets with these values: 2
Pset_SlabCommon - IsExternal: no; Reference: Floor:Losa HA 150mm; PitchAngle: 2.98923 deg; LoadBearing: no
Qto_SlabBaseQuantities - Depth: 0.15 m; Perimeter: 140.727 m; GrossArea: 80.3389 m2; NetArea: 80.4483 m2; GrossVolume: 12.0508 m3; NetVolume: 12.0673 m3
Other - Family: Floor; Family and Type: Floor: Losa HA 150mm; Type: Losa HA 150mm; Type Id: 768037
Constraints - Room Bounding: yes; Height Offset From Level: 0 m; Related to Mass: no; Level: Nivel 2
Dimensions - Area: 80.4483 m2; Perimeter: 42.8935 m; Thickness: 0.15 m; Volume: 12.0673 m3
Phasing - Phase Created: New Construction
Structural - Structural: no
AboveGround - AboveGround: yes

# IfcSlab: Floor:Losa colaborante 150mm (6)
Type - PredefinedType: FLOOR; Material: HA
Type - Other - Category: Floors; Family Name: Floor
Type - Construction - Function: Interior; Default Thickness: 0.15 m
Type - Graphics - Coarse Scale Fill Color: 0
Type - Identity Data - Type Name: Losa colaborante 150mm
Type - Materials and Finishes - Structural Material: HA
Type - Analytical Properties - Absorptance: 0.1; Roughness: 1; Heat Transfer Coefficient (U): 1000000000000000019884624838656 kg/K/s3; Thermal Mass: 0; Thermal Resistance (R): 0 s3*K/kg
Type - Pset_SlabCommon - ThermalTransmittance: 1000000000000000019884624838656 kg/K/s3
Classification: B104 (FEMAP58)
Pset_EnvironmentalImpactIndicators - Reference: Floor:Losa colaborante 150mm; sets with these values: 2
Pset_SlabCommon - IsExternal: no; LoadBearing: yes; PitchAngle: 0 deg; Reference: Floor:Losa colaborante 150mm
Qto_SlabBaseQuantities - HA, Width: 0.15 m; Width: 0.15 m; Depth: 0.15 m
Other - Family: Floor; Family and Type: Floor: Losa colaborante 150mm; Type: Losa colaborante 150mm; Type Id: 809659
Constraints - Room Bounding: yes; Height Offset From Level: 0 m; Related to Mass: no
Dimensions - Core Thickness: 0.15 m; Thickness: 0.15 m
Phasing - Phase Created: New Construction
Structural - Rebar Cover - Bottom Face: Rebar Cover 1 <25 mm>; Rebar Cover - Other Faces: Rebar Cover 1 <25 mm>; Rebar Cover - Top Face: Rebar Cover 1 <25 mm>; Structural: yes
AboveGround - AboveGround: yes
Name (Floor:Losa colaborante 150mm:...) | In | Qto_SlabBaseQuantities, Perimeter (m) | GrossArea (m2) | NetArea (m2) = Area (m2) | GrossVolume (m3) | NetVolume (m3) = Volume (m3) | Level | Elevation at Bottom (m) = Elevation at Bottom Core (m) | Elevation at Bottom Survey (m) | Elevation at Top (m) = Elevation at Top Core (m) | Elevation at Top Survey (m) | Dimensions, Perimeter (m)
781008 | Nivel 2 | 539.37 | 724.555 | 722.54 | 108.683 | 108.381 | Nivel 2 | 4.05 | 321.2 | 4.2 | 321.35 | 164.4
782652 | Nivel 3 | 460.696 | 565.159 | 563.869 | 84.7738 | 84.5803 | Nivel 3 | 8.3 | 325.45 | 8.45 | 325.6 | 140.42
802126 | Nivel 2 | 447.835 | 546.25 | 534.047 | 81.9375 | 80.1071 | Nivel 2 | 4.05 | 321.2 | 4.2 | 321.35 | 136.5
802545 | Nivel 2 | 328.084 | 434.56 | 432.25 | 65.184 | 64.8375 | Nivel 2 | 4.05 | 321.2 | 4.2 | 321.35 | 100 | Qto_SlabBaseQuantities - Length: 11.2 m
802710 | Nivel 3 | 353.346 | 477.68 | 474.777 | 71.652 | 71.2165 | Nivel 3 | 8.3 | 325.45 | 8.45 | 325.6 | 107.7 | Qto_SlabBaseQuantities - Length: 11.2 m
802780 | Nivel 3 | 513.451 | 675.185 | 672.816 | 101.278 | 100.922 | Nivel 3 | 8.3 | 325.45 | 8.45 | 325.6 | 156.5

# IfcSlab: Floor:Radier - 100mm (3)
In: Nivel 1
Type - PredefinedType: FLOOR; Material: HA
Type - Other - Category: Floors; Family Name: Floor
Type - Construction - Default Thickness: 0.2 m; Function: Interior
Type - Graphics - Coarse Scale Fill Color: 0
Type - Identity Data - Type Name: Radier - 100mm
Type - Materials and Finishes - Structural Material: HA
Type - Analytical Properties - Absorptance: 0.1; Roughness: 1
Classification: B104 (FEMAP58)
Pset_EnvironmentalImpactIndicators - Reference: Floor:Radier - 100mm; sets with these values: 2
Pset_SlabCommon - IsExternal: no; LoadBearing: yes; Reference: Floor:Radier - 100mm; PitchAngle: 0 deg
Other - Family: Floor; Family and Type: Floor: Radier - 100mm; Type: Radier - 100mm; Type Id: 514839
Constraints - Room Bounding: yes; Height Offset From Level: 0 m; Level: Nivel 1; Related to Mass: no
Dimensions - Core Thickness: 0.2 m; Elevation at Bottom: -0.25 m; Elevation at Bottom Core: -0.25 m; Elevation at Bottom Survey: 316.9 m; Elevation at Top: -0.05 m; Elevation at Top Core: -0.05 m; Elevation at Top Survey: 317.1 m; Thickness: 0.2 m
Phasing - Phase Created: New Construction
Structural - Rebar Cover - Bottom Face: Rebar Cover 1 <25 mm>; Rebar Cover - Other Faces: Rebar Cover 1 <25 mm>; Rebar Cover - Top Face: Rebar Cover 1 <25 mm>; Structural: yes
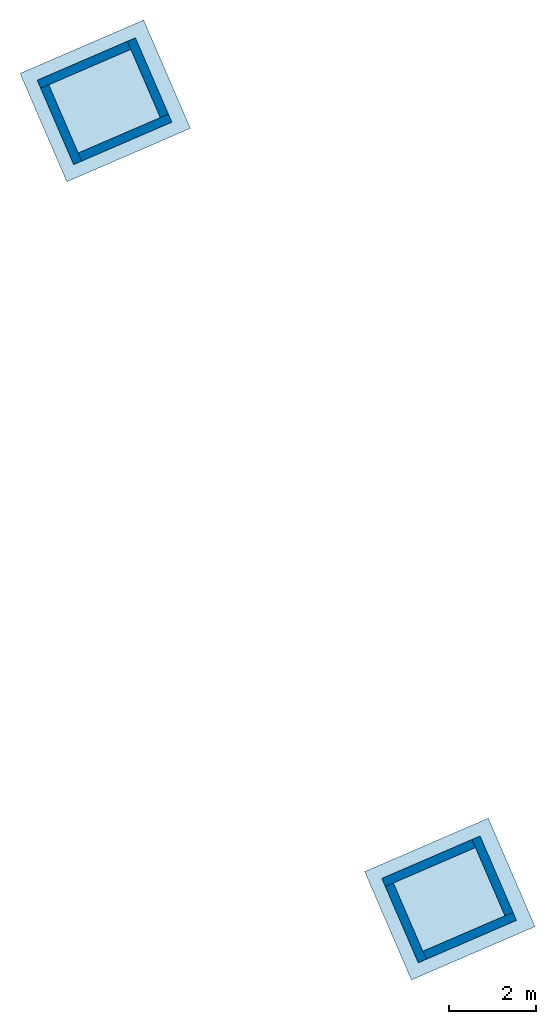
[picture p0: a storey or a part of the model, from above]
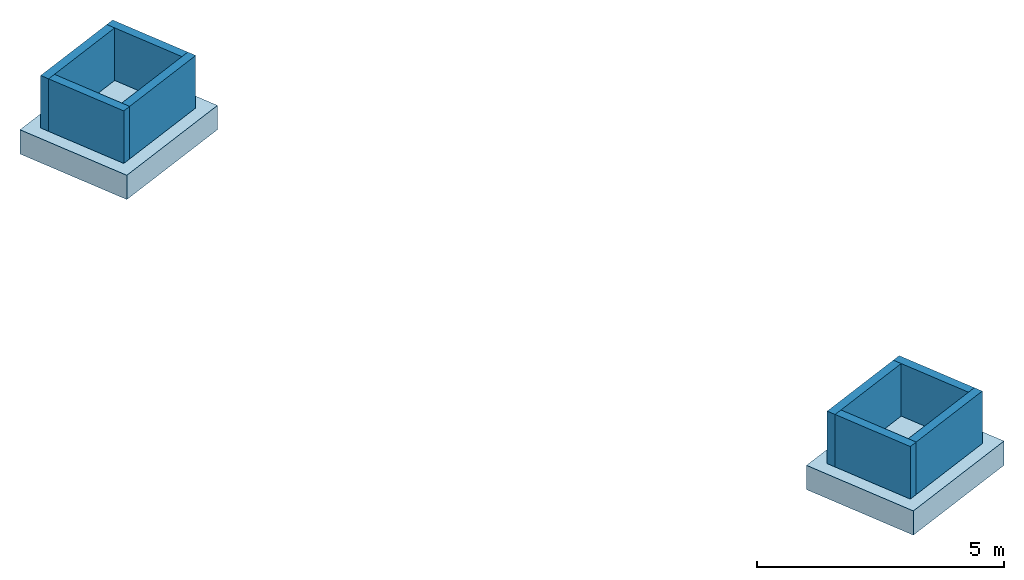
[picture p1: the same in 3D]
Properties of the parts of a building model (IFC4), part 4 of 4

# IfcSlab: Floor:Radier - 100mm (3)
AboveGround - AboveGround: yes
Name (Floor:Radier - 100mm:...) | Depth (m) | Qto_SlabBaseQuantities, Perimeter (m) | GrossArea (m2) | NetArea (m2) = Area (m2) | GrossVolume (m3) | NetVolume (m3) = Volume (m3) | Dimensions, Perimeter (m)
762400 | 0.2 | 373.033 | 477.68 | 475.43 | 95.536 | 95.0859 | 113.7 | Qto_SlabBaseQuantities - Width: 42.65 m; Length: 11.2 m
801468 | 0.2 | 440.288 | 557.038 | 557.038 | 111.408 | 111.408 | 134.2
801633 |  | 513.123 | 741.969 | 741.969 |  | 148.394 | 156.4

# IfcSlab: Foundation Slab:LosaFundacion 600mm (17)
Type - PredefinedType: BASESLAB; Material: HA
Type - Other - Category: Structural Foundations; Family Name: Foundation Slab
Type - Construction - Default Thickness: 0.6 m
Type - Dimensions - Foundation Thickness: 0.6 m
Type - Graphics - Coarse Scale Fill Color: 0
Type - Identity Data - Type Name: LosaFundacion 600mm
Type - Materials and Finishes - Structural Material: HA
Type - Analytical Properties - Absorptance: 0.1; Roughness: 1
Classification: Foundation (FEMAP58)
Pset_EnvironmentalImpactIndicators - Reference: Foundation Slab:LosaFundacion 600mm; sets with these values: 2
Pset_SlabCommon - IsExternal: no; LoadBearing: yes; PitchAngle: 0 deg; Reference: Foundation Slab:LosaFundacion 600mm
Qto_SlabBaseQuantities - Depth: 0.6 m
Other - Family: Foundation Slab; Family and Type: Foundation Slab: LosaFundacion 600mm; Type: LosaFundacion 600mm; Type Id: 839035
Constraints - Height Offset From Level: 0 m; Related to Mass: no
Dimensions - Core Thickness: 0.6 m; Thickness: 0.6 m
Phasing - Phase Created: New Construction
Structural - Rebar Cover - Bottom Face: Rebar Cover 1 <25 mm>; Rebar Cover - Other Faces: Rebar Cover 1 <25 mm>; Rebar Cover - Top Face: Rebar Cover 1 <25 mm>; Structural: yes
Name (Foundation Slab:LosaFundacion 600mm:...) | In | Qto_SlabBaseQuantities, Width (m) = Dimensions, Width (m) | Qto_SlabBaseQuantities, Length (m) = Dimensions, Length (m) | Qto_SlabBaseQuantities, Perimeter (m) | GrossArea (m2) | NetArea (m2) = Area (m2) | GrossVolume (m3) | NetVolume (m3) = Volume (m3) | Level | Elevation at Bottom (m) = Elevation at Bottom Core (m) | Elevation at Bottom Survey (m) | Elevation at Top (m) = Elevation at Top Core (m) | Elevation at Top Survey (m) | Dimensions, Perimeter (m) | AboveGround
838995 | d_Fundaciones | 13.1 | 2.3 | 101.05 | 30.13 | 30.13 | 18.078 | 18.078 | d_Fundaciones | -1.55 | 315.6 | -0.95 | 316.2 | 30.8 | no
840566 | d_Fundaciones | 14.5102 | 9.5 | 224.476 | 73.1468 | 70.8968 | 43.8881 | 42.5381 | d_Fundaciones | -1.55 | 315.6 | -0.95 | 316.2 | 68.4204 | no
841282 | d_Fundaciones | 13.1 | 2.3 | 101.05 | 30.13 | 30.13 | 18.078 | 18.078 | d_Fundaciones | -1.55 | 315.6 | -0.95 | 316.2 | 30.8 | no
841323 | d_Fundaciones | 2.3 | 9.5 | 77.4278 | 21.85 | 21.85 | 13.11 | 13.11 | d_Fundaciones | -1.55 | 315.6 | -0.95 | 316.2 | 23.6 | no
841363 | d_Fundaciones | 2.3 | 9.5 | 77.4278 | 21.85 | 21.85 | 13.11 | 13.11 | d_Fundaciones | -1.55 | 315.6 | -0.95 | 316.2 | 23.6 | no
841404 | d_Fundaciones | 2.3 | 9.5 | 77.4278 | 21.85 | 21.85 | 13.11 | 13.11 | d_Fundaciones | -1.55 | 315.6 | -0.95 | 316.2 | 23.6 | no
841444 | d_Fundaciones | 2.75 | 11.45 | 93.1759 | 27.37 | 27.37 | 16.422 | 16.422 | d_Fundaciones | -1.55 | 315.6 | -0.95 | 316.2 | 28.4 | no
841670 | d_Fundaciones | 2.3 | 9.5 | 77.4278 | 21.85 | 21.85 | 13.11 | 13.11 | d_Fundaciones | -1.55 | 315.6 | -0.95 | 316.2 | 23.6 | no
841711 | d_Fundaciones | 2.3 | 9.5 | 77.4278 | 21.85 | 21.85 | 13.11 | 13.11 | d_Fundaciones | -1.55 | 315.6 | -0.95 | 316.2 | 23.6 | no
841752 | d_Fundaciones | 13.1 | 5.9 | 148.294 | 46.6743 | 46.6743 | 28.0046 | 28.0046 | d_Fundaciones | -1.55 | 315.6 | -0.95 | 316.2 | 45.2 | no
842089 | d_Fundaciones | 14 | 5.9 | 154.199 | 52 | 52 | 31.2 | 31.2 | d_Fundaciones | -1.55 | 315.6 | -0.95 | 316.2 | 47 | no
842541 | d_Fundaciones | 13.1 | 5.9 | 148.294 | 46.69 | 46.69 | 28.014 | 28.014 | d_Fundaciones | -1.55 | 315.6 | -0.95 | 316.2 | 45.2 | no
842896 | d_Fundaciones | 3 | 2.5 | 36.0892 | 7.5 | 7.5 | 4.5 | 4.5 | d_Fundaciones | -1.55 | 315.6 | -0.95 | 316.2 | 11 | no
842937 | d_Fundaciones | 3.85509 | 2.775 | 43.5045 | 7.43009 | 7.43009 | 4.45805 | 4.45805 | d_Fundaciones | -1.55 | 315.6 | -0.95 | 316.2 | 13.2602 | no
842978 | d_Fundaciones | 2.75008 | 2.3 | 33.137 | 6.32517 | 6.32517 | 3.7951 | 3.7951 | d_Fundaciones | -1.55 | 315.6 | -0.95 | 316.2 | 10.1002 | no
915262 | Base MHA ASC | 2.69991 | 3.08 | 37.9259 | 8.31573 | 8.31573 | 4.98944 | 4.98944 | Base MHA ASC | -1.95 | 315.2 | -1.35 | 315.8 | 11.5598 | Group: Model Group:CAJA ASCENSOR (members excluded):916446
916581 | Base MHA ASC | 2.69991 | 3.08 | 37.9259 | 8.31573 | 8.31573 | 4.98944 | 4.98944 | Base MHA ASC | -1.95 | 315.2 | -1.35 | 315.8 | 11.5598 | Group: Model Group:CAJA ASCENSOR (members excluded):916610

# IfcSlab: M_Pile Cap-Rectangular:2300 x 2300 x 600mm (26)
In: Nivel 1
Type - PredefinedType: BASESLAB; Material: HA
Type - Other - Category: Structural Foundations; Family Name: M_Pile Cap-Rectangular
Type - Dimensions - Foundation Thickness: 0.6 m; Length: 2.3 m; Width: 2.3 m
Type - Identity Data - OmniClass Number: 23.25.05.11.11.27; OmniClass Title: Pile Caps; Type Name: 2300 x 2300 x 600mm
Classification: Foundation (FEMAP58)
Pset_EnvironmentalImpactIndicators - Reference: M_Pile Cap-Rectangular:2300 x 2300 x 600mm; sets with these values: 2
Pset_SlabCommon - IsExternal: no; Reference: M_Pile Cap-Rectangular:2300 x 2300 x 600mm
Qto_SlabBaseQuantities - Width: 2.3 m; Length: 2.3 m; Depth: 0.6 m; Perimeter: 9.2 m; GrossArea: 5.29 m2; NetArea: 5.29 m2; GrossVolume: 3.174 m3; NetVolume: 3.174 m3
Other - Family: M_Pile Cap-Rectangular; Family and Type: M_Pile Cap-Rectangular: 2300 x 2300 x 600mm; Type: 2300 x 2300 x 600mm; Type Id: 838471
Constraints - Moves With Grids: yes; Level: Nivel 1; Height Offset From Level: -0.9 m; Host: Level : Nivel 1
Dimensions - Area: 5.29 m2; Elevation at Bottom: -1.55 m; Elevation at Bottom Survey: 315.6 m; Elevation at Top: -0.95 m; Elevation at Top Survey: 316.2 m; Volume: 3.174 m3
Materials and Finishes - Structural Material: HA
Phasing - Phase Created: New Construction
Structural - Rebar Cover - Bottom Face: Rebar Cover 1 <25 mm>; Rebar Cover - Other Faces: Rebar Cover 1 <25 mm>; Rebar Cover - Top Face: Rebar Cover 1 <25 mm>
Name (M_Pile Cap-Rectangular:2300 x 2300 x 600mm:...)
810899
810911
810915
810923
810947
810961
810963
810973
810983
810985
810987
810995
810997
810999
811001
811005
811011
811017
811027
811029
811033
811035
811037
811039
811041
811043

# IfcSlab: M_Pile Cap-Rectangular:2800 x 2800 x 600mm (8)
In: Nivel 1
Type - PredefinedType: BASESLAB; Material: HA
Type - Other - Category: Structural Foundations; Family Name: M_Pile Cap-Rectangular
Type - Dimensions - Foundation Thickness: 0.6 m; Length: 2.8 m; Width: 2.8 m
Type - Identity Data - OmniClass Number: 23.25.05.11.11.27; OmniClass Title: Pile Caps; Type Name: 2800 x 2800 x 600mm
Classification: Foundation (FEMAP58)
Pset_EnvironmentalImpactIndicators - Reference: M_Pile Cap-Rectangular:2800 x 2800 x 600mm; sets with these values: 2
Pset_SlabCommon - IsExternal: no; Reference: M_Pile Cap-Rectangular:2800 x 2800 x 600mm
Qto_SlabBaseQuantities - Width: 2.8 m; Length: 2.8 m; Depth: 0.6 m; Perimeter: 11.2 m; GrossArea: 7.84 m2; NetArea: 7.84 m2; GrossVolume: 4.704 m3; NetVolume: 4.704 m3
Other - Family: M_Pile Cap-Rectangular; Family and Type: M_Pile Cap-Rectangular: 2800 x 2800 x 600mm; Type: 2800 x 2800 x 600mm; Type Id: 896741
Constraints - Moves With Grids: yes; Level: Nivel 1; Height Offset From Level: -0.9 m; Host: Level : Nivel 1
Dimensions - Area: 7.84 m2; Elevation at Bottom: -1.55 m; Elevation at Bottom Survey: 315.6 m; Elevation at Top: -0.95 m; Elevation at Top Survey: 316.2 m; Volume: 4.704 m3
Materials and Finishes - Structural Material: HA
Phasing - Phase Created: New Construction
Structural - Rebar Cover - Bottom Face: Rebar Cover 1 <25 mm>; Rebar Cover - Other Faces: Rebar Cover 1 <25 mm>; Rebar Cover - Top Face: Rebar Cover 1 <25 mm>
Name (M_Pile Cap-Rectangular:2800 x 2800 x 600mm:...)
810891
810905
810907
810941
810943
810971
810977
810979

# IfcSlab: M_Pile Cap-Rectangular:3100 x 3100 x 600mm (3)
In: Nivel 1
Type - PredefinedType: BASESLAB; Material: HA
Type - Other - Category: Structural Foundations; Family Name: M_Pile Cap-Rectangular
Type - Dimensions - Foundation Thickness: 0.6 m; Length: 3.1 m; Width: 3.1 m
Type - Identity Data - OmniClass Number: 23.25.05.11.11.27; OmniClass Title: Pile Caps; Type Name: 3100 x 3100 x 600mm
Classification: Foundation (FEMAP58)
Pset_EnvironmentalImpactIndicators - Reference: M_Pile Cap-Rectangular:3100 x 3100 x 600mm; sets with these values: 2
Pset_SlabCommon - IsExternal: no; Reference: M_Pile Cap-Rectangular:3100 x 3100 x 600mm
Qto_SlabBaseQuantities - Width: 3.1 m; Length: 3.1 m; Depth: 0.6 m; Perimeter: 12.4 m; GrossArea: 9.61 m2; NetArea: 9.61 m2; GrossVolume: 5.766 m3; NetVolume: 5.766 m3
Other - Family: M_Pile Cap-Rectangular; Family and Type: M_Pile Cap-Rectangular: 3100 x 3100 x 600mm; Type: 3100 x 3100 x 600mm; Type Id: 896792
Constraints - Moves With Grids: yes; Level: Nivel 1; Height Offset From Level: -0.9 m; Host: Level : Nivel 1
Dimensions - Area: 9.61 m2; Elevation at Bottom: -1.55 m; Elevation at Bottom Survey: 315.6 m; Elevation at Top: -0.95 m; Elevation at Top Survey: 316.2 m; Volume: 5.766 m3
Materials and Finishes - Structural Material: HA
Phasing - Phase Created: New Construction
Structural - Rebar Cover - Bottom Face: Rebar Cover 1 <25 mm>; Rebar Cover - Other Faces: Rebar Cover 1 <25 mm>; Rebar Cover - Top Face: Rebar Cover 1 <25 mm>
Name (M_Pile Cap-Rectangular:3100 x 3100 x 600mm:...)
810903
810939
810975

# IfcWall: Basic Wall:Contención-HA_200mm (8)
In: Base MHA ASC
Type - PredefinedType: STANDARD
Type - Other - Category: Walls; Family Name: Basic Wall
Type - Construction - Function: Exterior; Width: 0.2 m; Wrapping at Ends: Exterior; Wrapping at Inserts: Exterior
Type - Graphics - Coarse Scale Fill Color: 6974058
Type - Identity Data - Description: Maó calat (gero) e=14 cm; Model: M03; Type Name: Contención-HA_200mm
Type - Materials and Finishes - Structural Material: HA
Type - Analytical Properties - Absorptance: 0.1; Roughness: 1
Type - Pset_ReinforcementBarPitchOfWall - Description: Maó calat (gero) e=14 cm
Classification: B2011 (FEMAP58); Material: HA
Qto_WallBaseQuantities - Height: 1.3 m; Width: 0.2 m
Pset_EnvironmentalImpactIndicators - Reference: Basic Wall:Contención-HA_200mm; sets with these values: 2
Pset_WallCommon - LoadBearing: no; Reference: Basic Wall:Contención-HA_200mm; IsExternal: yes; ExtendToStructure: no
Other - Family: Basic Wall; Family and Type: Basic Wall: Contención-HA_200mm; Type: Contención-HA_200mm; Type Id: 533182
Constraints - Base Offset: 0 m; Room Bounding: yes; Top Offset: 0 m; Related to Mass: no; Base Constraint: Base MHA ASC; Base Extension Distance: 0 m; Base is Attached: no; Location Line: Wall Centerline; Top Constraint: Up to level: Nivel 1; Top Extension Distance: 0 m; Top is Attached: no; Unconnected Height: 1.3 m
Phasing - Phase Created: New Construction
Structural - Structural: no; Structural Usage: Non-bearing
Cross-Section Definition - Cross-Section: Vertical
AboveGround - AboveGround: yes
Name (Basic Wall:Contención-HA_200mm:...) | Qto_WallBaseQuantities, Length (m) = Pset_WallLength, Length (m) = Dimensions, Length (m) | GrossFootprintArea (m2) | GrossVolume (m3) = NetVolume (m3) = Volume (m3) | GrossSideArea (m2) = NetSideArea (m2) = Pset_WallArea, Area (m2) = Dimensions, Area (m2) | Group
915235 | 1.89991 | 0.379982 | 0.493977 | 2.46988 | Model Group:CAJA ASCENSOR (members excluded):916446
915236 | 2.245 | 0.449 | 0.5837 | 2.9185 | Model Group:CAJA ASCENSOR (members excluded):916446
915237 | 1.89991 | 0.379982 | 0.493977 | 2.46988 | Model Group:CAJA ASCENSOR (members excluded):916446
915238 | 2.245 | 0.449 | 0.5837 | 2.9185 | Model Group:CAJA ASCENSOR (members excluded):916446
916575 | 1.89991 | 0.379982 | 0.493977 | 2.46988 | Model Group:CAJA ASCENSOR (members excluded):916610
916576 | 2.245 | 0.449 | 0.5837 | 2.9185 | Model Group:CAJA ASCENSOR (members excluded):916610
916577 | 1.89991 | 0.379982 | 0.493977 | 2.46988 | Model Group:CAJA ASCENSOR (members excluded):916610
916578 | 2.245 | 0.449 | 0.5837 | 2.9185 | Model Group:CAJA ASCENSOR (members excluded):916610
